VERSION 5.8 ;
BUSBITCHARS "[]" ;
DIVIDERCHAR "/" ;
UNITS
    DATABASE MICRONS 1000 ;
END UNITS

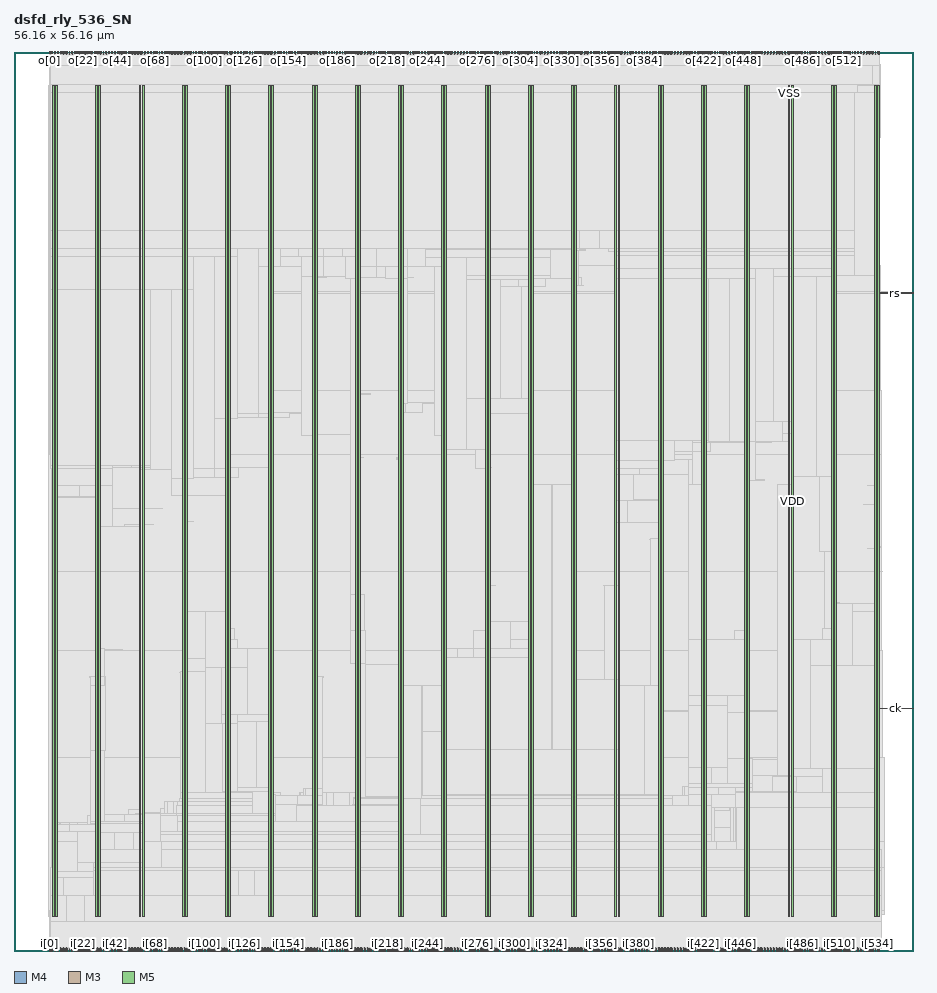
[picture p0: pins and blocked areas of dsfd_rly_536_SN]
MACRO dsfd_rly_536_SN
  FOREIGN dsfd_rly_536_SN 0 0 ;
  CLASS BLOCK ;
  SIZE 56.16 BY 56.16 ;
  PIN ck
    DIRECTION INPUT ;
    USE SIGNAL ;
    PORT
      LAYER M4 ;
        RECT  55.968 15.12 56.16 15.144 ;
    END
    PORT
      LAYER M4 ;
        RECT  54.004 15.12 55.98 15.144 ;
    END
  END ck
  PIN i[0]
    DIRECTION INPUT ;
    USE SIGNAL ;
    PORT
      LAYER M3 ;
        RECT  2.196 0 2.214 0.144 ;
    END
  END i[0]
  PIN i[100]
    DIRECTION INPUT ;
    USE SIGNAL ;
    PORT
      LAYER M3 ;
        RECT  11.88 0 11.898 0.144 ;
    END
  END i[100]
  PIN i[101]
    DIRECTION INPUT ;
    USE SIGNAL ;
    PORT
      LAYER M5 ;
        RECT  11.952 0 11.976 0.192 ;
    END
  END i[101]
  PIN i[102]
    DIRECTION INPUT ;
    USE SIGNAL ;
    PORT
      LAYER M3 ;
        RECT  12.06 0 12.078 0.144 ;
    END
  END i[102]
  PIN i[103]
    DIRECTION INPUT ;
    USE SIGNAL ;
    PORT
      LAYER M5 ;
        RECT  12.144 0 12.168 0.192 ;
    END
  END i[103]
  PIN i[104]
    DIRECTION INPUT ;
    USE SIGNAL ;
    PORT
      LAYER M3 ;
        RECT  12.24 0 12.258 0.144 ;
    END
  END i[104]
  PIN i[105]
    DIRECTION INPUT ;
    USE SIGNAL ;
    PORT
      LAYER M5 ;
        RECT  12.336 0 12.36 0.192 ;
    END
  END i[105]
  PIN i[106]
    DIRECTION INPUT ;
    USE SIGNAL ;
    PORT
      LAYER M3 ;
        RECT  12.456 0 12.474 0.144 ;
    END
  END i[106]
  PIN i[107]
    DIRECTION INPUT ;
    USE SIGNAL ;
    PORT
      LAYER M5 ;
        RECT  12.528 0 12.552 0.192 ;
    END
  END i[107]
  PIN i[108]
    DIRECTION INPUT ;
    USE SIGNAL ;
    PORT
      LAYER M3 ;
        RECT  12.636 0 12.654 0.144 ;
    END
  END i[108]
  PIN i[109]
    DIRECTION INPUT ;
    USE SIGNAL ;
    PORT
      LAYER M5 ;
        RECT  12.72 0 12.744 0.192 ;
    END
  END i[109]
  PIN i[10]
    DIRECTION INPUT ;
    USE SIGNAL ;
    PORT
      LAYER M3 ;
        RECT  3.168 0 3.186 0.144 ;
    END
  END i[10]
  PIN i[110]
    DIRECTION INPUT ;
    USE SIGNAL ;
    PORT
      LAYER M3 ;
        RECT  12.852 0 12.87 0.144 ;
    END
  END i[110]
  PIN i[111]
    DIRECTION INPUT ;
    USE SIGNAL ;
    PORT
      LAYER M5 ;
        RECT  12.912 0 12.936 0.192 ;
    END
  END i[111]
  PIN i[112]
    DIRECTION INPUT ;
    USE SIGNAL ;
    PORT
      LAYER M3 ;
        RECT  13.032 0 13.05 0.144 ;
    END
  END i[112]
  PIN i[113]
    DIRECTION INPUT ;
    USE SIGNAL ;
    PORT
      LAYER M5 ;
        RECT  13.104 0 13.128 0.192 ;
    END
  END i[113]
  PIN i[114]
    DIRECTION INPUT ;
    USE SIGNAL ;
    PORT
      LAYER M3 ;
        RECT  13.212 0 13.23 0.144 ;
    END
  END i[114]
  PIN i[115]
    DIRECTION INPUT ;
    USE SIGNAL ;
    PORT
      LAYER M5 ;
        RECT  13.296 0 13.32 0.192 ;
    END
  END i[115]
  PIN i[116]
    DIRECTION INPUT ;
    USE SIGNAL ;
    PORT
      LAYER M3 ;
        RECT  13.428 0 13.446 0.144 ;
    END
  END i[116]
  PIN i[117]
    DIRECTION INPUT ;
    USE SIGNAL ;
    PORT
      LAYER M5 ;
        RECT  13.536 0 13.56 0.192 ;
    END
  END i[117]
  PIN i[118]
    DIRECTION INPUT ;
    USE SIGNAL ;
    PORT
      LAYER M3 ;
        RECT  13.608 0 13.626 0.144 ;
    END
  END i[118]
  PIN i[119]
    DIRECTION INPUT ;
    USE SIGNAL ;
    PORT
      LAYER M5 ;
        RECT  13.728 0 13.752 0.192 ;
    END
  END i[119]
  PIN i[11]
    DIRECTION INPUT ;
    USE SIGNAL ;
    PORT
      LAYER M5 ;
        RECT  3.264 0 3.288 0.192 ;
    END
  END i[11]
  PIN i[120]
    DIRECTION INPUT ;
    USE SIGNAL ;
    PORT
      LAYER M3 ;
        RECT  13.788 0 13.806 0.144 ;
    END
  END i[120]
  PIN i[121]
    DIRECTION INPUT ;
    USE SIGNAL ;
    PORT
      LAYER M5 ;
        RECT  13.92 0 13.944 0.192 ;
    END
  END i[121]
  PIN i[122]
    DIRECTION INPUT ;
    USE SIGNAL ;
    PORT
      LAYER M3 ;
        RECT  14.004 0 14.022 0.144 ;
    END
  END i[122]
  PIN i[123]
    DIRECTION INPUT ;
    USE SIGNAL ;
    PORT
      LAYER M5 ;
        RECT  14.112 0 14.136 0.192 ;
    END
  END i[123]
  PIN i[124]
    DIRECTION INPUT ;
    USE SIGNAL ;
    PORT
      LAYER M3 ;
        RECT  14.184 0 14.202 0.144 ;
    END
  END i[124]
  PIN i[125]
    DIRECTION INPUT ;
    USE SIGNAL ;
    PORT
      LAYER M5 ;
        RECT  14.304 0 14.328 0.192 ;
    END
  END i[125]
  PIN i[126]
    DIRECTION INPUT ;
    USE SIGNAL ;
    PORT
      LAYER M3 ;
        RECT  14.4 0 14.418 0.144 ;
    END
  END i[126]
  PIN i[127]
    DIRECTION INPUT ;
    USE SIGNAL ;
    PORT
      LAYER M5 ;
        RECT  14.496 0 14.52 0.192 ;
    END
  END i[127]
  PIN i[128]
    DIRECTION INPUT ;
    USE SIGNAL ;
    PORT
      LAYER M3 ;
        RECT  14.58 0 14.598 0.144 ;
    END
  END i[128]
  PIN i[129]
    DIRECTION INPUT ;
    USE SIGNAL ;
    PORT
      LAYER M5 ;
        RECT  14.688 0 14.712 0.192 ;
    END
  END i[129]
  PIN i[12]
    DIRECTION INPUT ;
    USE SIGNAL ;
    PORT
      LAYER M3 ;
        RECT  3.348 0 3.366 0.144 ;
    END
  END i[12]
  PIN i[130]
    DIRECTION INPUT ;
    USE SIGNAL ;
    PORT
      LAYER M3 ;
        RECT  14.76 0 14.778 0.144 ;
    END
  END i[130]
  PIN i[131]
    DIRECTION INPUT ;
    USE SIGNAL ;
    PORT
      LAYER M5 ;
        RECT  14.88 0 14.904 0.192 ;
    END
  END i[131]
  PIN i[132]
    DIRECTION INPUT ;
    USE SIGNAL ;
    PORT
      LAYER M3 ;
        RECT  14.976 0 14.994 0.144 ;
    END
  END i[132]
  PIN i[133]
    DIRECTION INPUT ;
    USE SIGNAL ;
    PORT
      LAYER M5 ;
        RECT  15.072 0 15.096 0.192 ;
    END
  END i[133]
  PIN i[134]
    DIRECTION INPUT ;
    USE SIGNAL ;
    PORT
      LAYER M3 ;
        RECT  15.156 0 15.174 0.144 ;
    END
  END i[134]
  PIN i[135]
    DIRECTION INPUT ;
    USE SIGNAL ;
    PORT
      LAYER M5 ;
        RECT  15.264 0 15.288 0.192 ;
    END
  END i[135]
  PIN i[136]
    DIRECTION INPUT ;
    USE SIGNAL ;
    PORT
      LAYER M3 ;
        RECT  15.336 0 15.354 0.144 ;
    END
  END i[136]
  PIN i[137]
    DIRECTION INPUT ;
    USE SIGNAL ;
    PORT
      LAYER M5 ;
        RECT  15.456 0 15.48 0.192 ;
    END
  END i[137]
  PIN i[138]
    DIRECTION INPUT ;
    USE SIGNAL ;
    PORT
      LAYER M3 ;
        RECT  15.552 0 15.57 0.144 ;
    END
  END i[138]
  PIN i[139]
    DIRECTION INPUT ;
    USE SIGNAL ;
    PORT
      LAYER M5 ;
        RECT  15.648 0 15.672 0.192 ;
    END
  END i[139]
  PIN i[13]
    DIRECTION INPUT ;
    USE SIGNAL ;
    PORT
      LAYER M5 ;
        RECT  3.456 0 3.48 0.192 ;
    END
  END i[13]
  PIN i[140]
    DIRECTION INPUT ;
    USE SIGNAL ;
    PORT
      LAYER M3 ;
        RECT  15.732 0 15.75 0.144 ;
    END
  END i[140]
  PIN i[141]
    DIRECTION INPUT ;
    USE SIGNAL ;
    PORT
      LAYER M5 ;
        RECT  15.84 0 15.864 0.192 ;
    END
  END i[141]
  PIN i[142]
    DIRECTION INPUT ;
    USE SIGNAL ;
    PORT
      LAYER M3 ;
        RECT  15.948 0 15.966 0.144 ;
    END
  END i[142]
  PIN i[143]
    DIRECTION INPUT ;
    USE SIGNAL ;
    PORT
      LAYER M5 ;
        RECT  16.032 0 16.056 0.192 ;
    END
  END i[143]
  PIN i[144]
    DIRECTION INPUT ;
    USE SIGNAL ;
    PORT
      LAYER M3 ;
        RECT  16.128 0 16.146 0.144 ;
    END
  END i[144]
  PIN i[145]
    DIRECTION INPUT ;
    USE SIGNAL ;
    PORT
      LAYER M5 ;
        RECT  16.224 0 16.248 0.192 ;
    END
  END i[145]
  PIN i[146]
    DIRECTION INPUT ;
    USE SIGNAL ;
    PORT
      LAYER M3 ;
        RECT  16.308 0 16.326 0.144 ;
    END
  END i[146]
  PIN i[147]
    DIRECTION INPUT ;
    USE SIGNAL ;
    PORT
      LAYER M5 ;
        RECT  16.416 0 16.44 0.192 ;
    END
  END i[147]
  PIN i[148]
    DIRECTION INPUT ;
    USE SIGNAL ;
    PORT
      LAYER M3 ;
        RECT  16.524 0 16.542 0.144 ;
    END
  END i[148]
  PIN i[149]
    DIRECTION INPUT ;
    USE SIGNAL ;
    PORT
      LAYER M5 ;
        RECT  16.608 0 16.632 0.192 ;
    END
  END i[149]
  PIN i[14]
    DIRECTION INPUT ;
    USE SIGNAL ;
    PORT
      LAYER M3 ;
        RECT  3.564 0 3.582 0.144 ;
    END
  END i[14]
  PIN i[150]
    DIRECTION INPUT ;
    USE SIGNAL ;
    PORT
      LAYER M3 ;
        RECT  16.704 0 16.722 0.144 ;
    END
  END i[150]
  PIN i[151]
    DIRECTION INPUT ;
    USE SIGNAL ;
    PORT
      LAYER M5 ;
        RECT  16.8 0 16.824 0.192 ;
    END
  END i[151]
  PIN i[152]
    DIRECTION INPUT ;
    USE SIGNAL ;
    PORT
      LAYER M3 ;
        RECT  16.884 0 16.902 0.144 ;
    END
  END i[152]
  PIN i[153]
    DIRECTION INPUT ;
    USE SIGNAL ;
    PORT
      LAYER M5 ;
        RECT  16.992 0 17.016 0.192 ;
    END
  END i[153]
  PIN i[154]
    DIRECTION INPUT ;
    USE SIGNAL ;
    PORT
      LAYER M3 ;
        RECT  17.1 0 17.118 0.144 ;
    END
  END i[154]
  PIN i[155]
    DIRECTION INPUT ;
    USE SIGNAL ;
    PORT
      LAYER M5 ;
        RECT  17.184 0 17.208 0.192 ;
    END
  END i[155]
  PIN i[156]
    DIRECTION INPUT ;
    USE SIGNAL ;
    PORT
      LAYER M3 ;
        RECT  17.28 0 17.298 0.144 ;
    END
  END i[156]
  PIN i[157]
    DIRECTION INPUT ;
    USE SIGNAL ;
    PORT
      LAYER M5 ;
        RECT  17.376 0 17.4 0.192 ;
    END
  END i[157]
  PIN i[158]
    DIRECTION INPUT ;
    USE SIGNAL ;
    PORT
      LAYER M3 ;
        RECT  17.496 0 17.514 0.144 ;
    END
  END i[158]
  PIN i[159]
    DIRECTION INPUT ;
    USE SIGNAL ;
    PORT
      LAYER M5 ;
        RECT  17.568 0 17.592 0.192 ;
    END
  END i[159]
  PIN i[15]
    DIRECTION INPUT ;
    USE SIGNAL ;
    PORT
      LAYER M5 ;
        RECT  3.648 0 3.672 0.192 ;
    END
  END i[15]
  PIN i[160]
    DIRECTION INPUT ;
    USE SIGNAL ;
    PORT
      LAYER M3 ;
        RECT  17.676 0 17.694 0.144 ;
    END
  END i[160]
  PIN i[161]
    DIRECTION INPUT ;
    USE SIGNAL ;
    PORT
      LAYER M5 ;
        RECT  17.76 0 17.784 0.192 ;
    END
  END i[161]
  PIN i[162]
    DIRECTION INPUT ;
    USE SIGNAL ;
    PORT
      LAYER M3 ;
        RECT  17.856 0 17.874 0.144 ;
    END
  END i[162]
  PIN i[163]
    DIRECTION INPUT ;
    USE SIGNAL ;
    PORT
      LAYER M5 ;
        RECT  17.952 0 17.976 0.192 ;
    END
  END i[163]
  PIN i[164]
    DIRECTION INPUT ;
    USE SIGNAL ;
    PORT
      LAYER M3 ;
        RECT  18.072 0 18.09 0.144 ;
    END
  END i[164]
  PIN i[165]
    DIRECTION INPUT ;
    USE SIGNAL ;
    PORT
      LAYER M5 ;
        RECT  18.144 0 18.168 0.192 ;
    END
  END i[165]
  PIN i[166]
    DIRECTION INPUT ;
    USE SIGNAL ;
    PORT
      LAYER M3 ;
        RECT  18.252 0 18.27 0.144 ;
    END
  END i[166]
  PIN i[167]
    DIRECTION INPUT ;
    USE SIGNAL ;
    PORT
      LAYER M5 ;
        RECT  18.336 0 18.36 0.192 ;
    END
  END i[167]
  PIN i[168]
    DIRECTION INPUT ;
    USE SIGNAL ;
    PORT
      LAYER M3 ;
        RECT  18.432 0 18.45 0.144 ;
    END
  END i[168]
  PIN i[169]
    DIRECTION INPUT ;
    USE SIGNAL ;
    PORT
      LAYER M5 ;
        RECT  18.528 0 18.552 0.192 ;
    END
  END i[169]
  PIN i[16]
    DIRECTION INPUT ;
    USE SIGNAL ;
    PORT
      LAYER M3 ;
        RECT  3.744 0 3.762 0.144 ;
    END
  END i[16]
  PIN i[170]
    DIRECTION INPUT ;
    USE SIGNAL ;
    PORT
      LAYER M3 ;
        RECT  18.648 0 18.666 0.144 ;
    END
  END i[170]
  PIN i[171]
    DIRECTION INPUT ;
    USE SIGNAL ;
    PORT
      LAYER M5 ;
        RECT  18.72 0 18.744 0.192 ;
    END
  END i[171]
  PIN i[172]
    DIRECTION INPUT ;
    USE SIGNAL ;
    PORT
      LAYER M3 ;
        RECT  18.828 0 18.846 0.144 ;
    END
  END i[172]
  PIN i[173]
    DIRECTION INPUT ;
    USE SIGNAL ;
    PORT
      LAYER M5 ;
        RECT  18.912 0 18.936 0.192 ;
    END
  END i[173]
  PIN i[174]
    DIRECTION INPUT ;
    USE SIGNAL ;
    PORT
      LAYER M3 ;
        RECT  19.044 0 19.062 0.144 ;
    END
  END i[174]
  PIN i[175]
    DIRECTION INPUT ;
    USE SIGNAL ;
    PORT
      LAYER M5 ;
        RECT  19.104 0 19.128 0.192 ;
    END
  END i[175]
  PIN i[176]
    DIRECTION INPUT ;
    USE SIGNAL ;
    PORT
      LAYER M3 ;
        RECT  19.224 0 19.242 0.144 ;
    END
  END i[176]
  PIN i[177]
    DIRECTION INPUT ;
    USE SIGNAL ;
    PORT
      LAYER M5 ;
        RECT  19.296 0 19.32 0.192 ;
    END
  END i[177]
  PIN i[178]
    DIRECTION INPUT ;
    USE SIGNAL ;
    PORT
      LAYER M3 ;
        RECT  19.404 0 19.422 0.144 ;
    END
  END i[178]
  PIN i[179]
    DIRECTION INPUT ;
    USE SIGNAL ;
    PORT
      LAYER M5 ;
        RECT  19.488 0 19.512 0.192 ;
    END
  END i[179]
  PIN i[17]
    DIRECTION INPUT ;
    USE SIGNAL ;
    PORT
      LAYER M5 ;
        RECT  3.84 0 3.864 0.192 ;
    END
  END i[17]
  PIN i[180]
    DIRECTION INPUT ;
    USE SIGNAL ;
    PORT
      LAYER M3 ;
        RECT  19.62 0 19.638 0.144 ;
    END
  END i[180]
  PIN i[181]
    DIRECTION INPUT ;
    USE SIGNAL ;
    PORT
      LAYER M5 ;
        RECT  19.68 0 19.704 0.192 ;
    END
  END i[181]
  PIN i[182]
    DIRECTION INPUT ;
    USE SIGNAL ;
    PORT
      LAYER M3 ;
        RECT  19.8 0 19.818 0.144 ;
    END
  END i[182]
  PIN i[183]
    DIRECTION INPUT ;
    USE SIGNAL ;
    PORT
      LAYER M5 ;
        RECT  19.872 0 19.896 0.192 ;
    END
  END i[183]
  PIN i[184]
    DIRECTION INPUT ;
    USE SIGNAL ;
    PORT
      LAYER M3 ;
        RECT  19.98 0 19.998 0.144 ;
    END
  END i[184]
  PIN i[185]
    DIRECTION INPUT ;
    USE SIGNAL ;
    PORT
      LAYER M5 ;
        RECT  20.112 0 20.136 0.192 ;
    END
  END i[185]
  PIN i[186]
    DIRECTION INPUT ;
    USE SIGNAL ;
    PORT
      LAYER M3 ;
        RECT  20.196 0 20.214 0.144 ;
    END
  END i[186]
  PIN i[187]
    DIRECTION INPUT ;
    USE SIGNAL ;
    PORT
      LAYER M5 ;
        RECT  20.304 0 20.328 0.192 ;
    END
  END i[187]
  PIN i[188]
    DIRECTION INPUT ;
    USE SIGNAL ;
    PORT
      LAYER M3 ;
        RECT  20.376 0 20.394 0.144 ;
    END
  END i[188]
  PIN i[189]
    DIRECTION INPUT ;
    USE SIGNAL ;
    PORT
      LAYER M5 ;
        RECT  20.496 0 20.52 0.192 ;
    END
  END i[189]
  PIN i[18]
    DIRECTION INPUT ;
    USE SIGNAL ;
    PORT
      LAYER M3 ;
        RECT  3.924 0 3.942 0.144 ;
    END
  END i[18]
  PIN i[190]
    DIRECTION INPUT ;
    USE SIGNAL ;
    PORT
      LAYER M3 ;
        RECT  20.592 0 20.61 0.144 ;
    END
  END i[190]
  PIN i[191]
    DIRECTION INPUT ;
    USE SIGNAL ;
    PORT
      LAYER M5 ;
        RECT  20.688 0 20.712 0.192 ;
    END
  END i[191]
  PIN i[192]
    DIRECTION INPUT ;
    USE SIGNAL ;
    PORT
      LAYER M3 ;
        RECT  20.772 0 20.79 0.144 ;
    END
  END i[192]
  PIN i[193]
    DIRECTION INPUT ;
    USE SIGNAL ;
    PORT
      LAYER M5 ;
        RECT  20.88 0 20.904 0.192 ;
    END
  END i[193]
  PIN i[194]
    DIRECTION INPUT ;
    USE SIGNAL ;
    PORT
      LAYER M3 ;
        RECT  20.952 0 20.97 0.144 ;
    END
  END i[194]
  PIN i[195]
    DIRECTION INPUT ;
    USE SIGNAL ;
    PORT
      LAYER M5 ;
        RECT  21.072 0 21.096 0.192 ;
    END
  END i[195]
  PIN i[196]
    DIRECTION INPUT ;
    USE SIGNAL ;
    PORT
      LAYER M3 ;
        RECT  21.168 0 21.186 0.144 ;
    END
  END i[196]
  PIN i[197]
    DIRECTION INPUT ;
    USE SIGNAL ;
    PORT
      LAYER M5 ;
        RECT  21.264 0 21.288 0.192 ;
    END
  END i[197]
  PIN i[198]
    DIRECTION INPUT ;
    USE SIGNAL ;
    PORT
      LAYER M3 ;
        RECT  21.348 0 21.366 0.144 ;
    END
  END i[198]
  PIN i[199]
    DIRECTION INPUT ;
    USE SIGNAL ;
    PORT
      LAYER M5 ;
        RECT  21.456 0 21.48 0.192 ;
    END
  END i[199]
  PIN i[19]
    DIRECTION INPUT ;
    USE SIGNAL ;
    PORT
      LAYER M5 ;
        RECT  4.032 0 4.056 0.192 ;
    END
  END i[19]
  PIN i[1]
    DIRECTION INPUT ;
    USE SIGNAL ;
    PORT
      LAYER M5 ;
        RECT  2.304 0 2.328 0.192 ;
    END
  END i[1]
  PIN i[200]
    DIRECTION INPUT ;
    USE SIGNAL ;
    PORT
      LAYER M3 ;
        RECT  21.528 0 21.546 0.144 ;
    END
  END i[200]
  PIN i[201]
    DIRECTION INPUT ;
    USE SIGNAL ;
    PORT
      LAYER M5 ;
        RECT  21.648 0 21.672 0.192 ;
    END
  END i[201]
  PIN i[202]
    DIRECTION INPUT ;
    USE SIGNAL ;
    PORT
      LAYER M3 ;
        RECT  21.744 0 21.762 0.144 ;
    END
  END i[202]
  PIN i[203]
    DIRECTION INPUT ;
    USE SIGNAL ;
    PORT
      LAYER M5 ;
        RECT  21.84 0 21.864 0.192 ;
    END
  END i[203]
  PIN i[204]
    DIRECTION INPUT ;
    USE SIGNAL ;
    PORT
      LAYER M3 ;
        RECT  21.924 0 21.942 0.144 ;
    END
  END i[204]
  PIN i[205]
    DIRECTION INPUT ;
    USE SIGNAL ;
    PORT
      LAYER M5 ;
        RECT  22.032 0 22.056 0.192 ;
    END
  END i[205]
  PIN i[206]
    DIRECTION INPUT ;
    USE SIGNAL ;
    PORT
      LAYER M3 ;
        RECT  22.14 0 22.158 0.144 ;
    END
  END i[206]
  PIN i[207]
    DIRECTION INPUT ;
    USE SIGNAL ;
    PORT
      LAYER M5 ;
        RECT  22.224 0 22.248 0.192 ;
    END
  END i[207]
  PIN i[208]
    DIRECTION INPUT ;
    USE SIGNAL ;
    PORT
      LAYER M3 ;
        RECT  22.32 0 22.338 0.144 ;
    END
  END i[208]
  PIN i[209]
    DIRECTION INPUT ;
    USE SIGNAL ;
    PORT
      LAYER M5 ;
        RECT  22.416 0 22.44 0.192 ;
    END
  END i[209]
  PIN i[20]
    DIRECTION INPUT ;
    USE SIGNAL ;
    PORT
      LAYER M3 ;
        RECT  4.14 0 4.158 0.144 ;
    END
  END i[20]
  PIN i[210]
    DIRECTION INPUT ;
    USE SIGNAL ;
    PORT
      LAYER M3 ;
        RECT  22.5 0 22.518 0.144 ;
    END
  END i[210]
  PIN i[211]
    DIRECTION INPUT ;
    USE SIGNAL ;
    PORT
      LAYER M5 ;
        RECT  22.608 0 22.632 0.192 ;
    END
  END i[211]
  PIN i[212]
    DIRECTION INPUT ;
    USE SIGNAL ;
    PORT
      LAYER M3 ;
        RECT  22.716 0 22.734 0.144 ;
    END
  END i[212]
  PIN i[213]
    DIRECTION INPUT ;
    USE SIGNAL ;
    PORT
      LAYER M5 ;
        RECT  22.8 0 22.824 0.192 ;
    END
  END i[213]
  PIN i[214]
    DIRECTION INPUT ;
    USE SIGNAL ;
    PORT
      LAYER M3 ;
        RECT  22.896 0 22.914 0.144 ;
    END
  END i[214]
  PIN i[215]
    DIRECTION INPUT ;
    USE SIGNAL ;
    PORT
      LAYER M5 ;
        RECT  22.992 0 23.016 0.192 ;
    END
  END i[215]
  PIN i[216]
    DIRECTION INPUT ;
    USE SIGNAL ;
    PORT
      LAYER M3 ;
        RECT  23.076 0 23.094 0.144 ;
    END
  END i[216]
  PIN i[217]
    DIRECTION INPUT ;
    USE SIGNAL ;
    PORT
      LAYER M5 ;
        RECT  23.184 0 23.208 0.192 ;
    END
  END i[217]
  PIN i[218]
    DIRECTION INPUT ;
    USE SIGNAL ;
    PORT
      LAYER M3 ;
        RECT  23.292 0 23.31 0.144 ;
    END
  END i[218]
  PIN i[219]
    DIRECTION INPUT ;
    USE SIGNAL ;
    PORT
      LAYER M5 ;
        RECT  23.376 0 23.4 0.192 ;
    END
  END i[219]
  PIN i[21]
    DIRECTION INPUT ;
    USE SIGNAL ;
    PORT
      LAYER M5 ;
        RECT  4.224 0 4.248 0.192 ;
    END
  END i[21]
  PIN i[220]
    DIRECTION INPUT ;
    USE SIGNAL ;
    PORT
      LAYER M3 ;
        RECT  23.472 0 23.49 0.144 ;
    END
  END i[220]
  PIN i[221]
    DIRECTION INPUT ;
    USE SIGNAL ;
    PORT
      LAYER M5 ;
        RECT  23.568 0 23.592 0.192 ;
    END
  END i[221]
  PIN i[222]
    DIRECTION INPUT ;
    USE SIGNAL ;
    PORT
      LAYER M3 ;
        RECT  23.688 0 23.706 0.144 ;
    END
  END i[222]
  PIN i[223]
    DIRECTION INPUT ;
    USE SIGNAL ;
    PORT
      LAYER M5 ;
        RECT  23.76 0 23.784 0.192 ;
    END
  END i[223]
  PIN i[224]
    DIRECTION INPUT ;
    USE SIGNAL ;
    PORT
      LAYER M3 ;
        RECT  23.868 0 23.886 0.144 ;
    END
  END i[224]
  PIN i[225]
    DIRECTION INPUT ;
    USE SIGNAL ;
    PORT
      LAYER M5 ;
        RECT  23.952 0 23.976 0.192 ;
    END
  END i[225]
  PIN i[226]
    DIRECTION INPUT ;
    USE SIGNAL ;
    PORT
      LAYER M3 ;
        RECT  24.048 0 24.066 0.144 ;
    END
  END i[226]
  PIN i[227]
    DIRECTION INPUT ;
    USE SIGNAL ;
    PORT
      LAYER M5 ;
        RECT  24.144 0 24.168 0.192 ;
    END
  END i[227]
  PIN i[228]
    DIRECTION INPUT ;
    USE SIGNAL ;
    PORT
      LAYER M3 ;
        RECT  24.264 0 24.282 0.144 ;
    END
  END i[228]
  PIN i[229]
    DIRECTION INPUT ;
    USE SIGNAL ;
    PORT
      LAYER M5 ;
        RECT  24.336 0 24.36 0.192 ;
    END
  END i[229]
  PIN i[22]
    DIRECTION INPUT ;
    USE SIGNAL ;
    PORT
      LAYER M3 ;
        RECT  4.32 0 4.338 0.144 ;
    END
  END i[22]
  PIN i[230]
    DIRECTION INPUT ;
    USE SIGNAL ;
    PORT
      LAYER M3 ;
        RECT  24.444 0 24.462 0.144 ;
    END
  END i[230]
  PIN i[231]
    DIRECTION INPUT ;
    USE SIGNAL ;
    PORT
      LAYER M5 ;
        RECT  24.528 0 24.552 0.192 ;
    END
  END i[231]
  PIN i[232]
    DIRECTION INPUT ;
    USE SIGNAL ;
    PORT
      LAYER M3 ;
        RECT  24.624 0 24.642 0.144 ;
    END
  END i[232]
  PIN i[233]
    DIRECTION INPUT ;
    USE SIGNAL ;
    PORT
      LAYER M5 ;
        RECT  24.72 0 24.744 0.192 ;
    END
  END i[233]
  PIN i[234]
    DIRECTION INPUT ;
    USE SIGNAL ;
    PORT
      LAYER M3 ;
        RECT  24.84 0 24.858 0.144 ;
    END
  END i[234]
  PIN i[235]
    DIRECTION INPUT ;
    USE SIGNAL ;
    PORT
      LAYER M5 ;
        RECT  24.912 0 24.936 0.192 ;
    END
  END i[235]
  PIN i[236]
    DIRECTION INPUT ;
    USE SIGNAL ;
    PORT
      LAYER M3 ;
        RECT  25.02 0 25.038 0.144 ;
    END
  END i[236]
  PIN i[237]
    DIRECTION INPUT ;
    USE SIGNAL ;
    PORT
      LAYER M5 ;
        RECT  25.104 0 25.128 0.192 ;
    END
  END i[237]
  PIN i[238]
    DIRECTION INPUT ;
    USE SIGNAL ;
    PORT
      LAYER M3 ;
        RECT  25.2 0 25.218 0.144 ;
    END
  END i[238]
  PIN i[239]
    DIRECTION INPUT ;
    USE SIGNAL ;
    PORT
      LAYER M5 ;
        RECT  25.296 0 25.32 0.192 ;
    END
  END i[239]
  PIN i[23]
    DIRECTION INPUT ;
    USE SIGNAL ;
    PORT
      LAYER M5 ;
        RECT  4.416 0 4.44 0.192 ;
    END
  END i[23]
  PIN i[240]
    DIRECTION INPUT ;
    USE SIGNAL ;
    PORT
      LAYER M3 ;
        RECT  25.416 0 25.434 0.144 ;
    END
  END i[240]
  PIN i[241]
    DIRECTION INPUT ;
    USE SIGNAL ;
    PORT
      LAYER M5 ;
        RECT  25.488 0 25.512 0.192 ;
    END
  END i[241]
  PIN i[242]
    DIRECTION INPUT ;
    USE SIGNAL ;
    PORT
      LAYER M3 ;
        RECT  25.596 0 25.614 0.144 ;
    END
  END i[242]
  PIN i[243]
    DIRECTION INPUT ;
    USE SIGNAL ;
    PORT
      LAYER M5 ;
        RECT  25.68 0 25.704 0.192 ;
    END
  END i[243]
  PIN i[244]
    DIRECTION INPUT ;
    USE SIGNAL ;
    PORT
      LAYER M3 ;
        RECT  25.812 0 25.83 0.144 ;
    END
  END i[244]
  PIN i[245]
    DIRECTION INPUT ;
    USE SIGNAL ;
    PORT
      LAYER M5 ;
        RECT  25.872 0 25.896 0.192 ;
    END
  END i[245]
  PIN i[246]
    DIRECTION INPUT ;
    USE SIGNAL ;
    PORT
      LAYER M3 ;
        RECT  25.992 0 26.01 0.144 ;
    END
  END i[246]
  PIN i[247]
    DIRECTION INPUT ;
    USE SIGNAL ;
    PORT
      LAYER M5 ;
        RECT  26.064 0 26.088 0.192 ;
    END
  END i[247]
  PIN i[248]
    DIRECTION INPUT ;
    USE SIGNAL ;
    PORT
      LAYER M3 ;
        RECT  26.172 0 26.19 0.144 ;
    END
  END i[248]
  PIN i[249]
    DIRECTION INPUT ;
    USE SIGNAL ;
    PORT
      LAYER M5 ;
        RECT  26.256 0 26.28 0.192 ;
    END
  END i[249]
  PIN i[24]
    DIRECTION INPUT ;
    USE SIGNAL ;
    PORT
      LAYER M3 ;
        RECT  4.536 0 4.554 0.144 ;
    END
  END i[24]
  PIN i[250]
    DIRECTION INPUT ;
    USE SIGNAL ;
    PORT
      LAYER M3 ;
        RECT  26.388 0 26.406 0.144 ;
    END
  END i[250]
  PIN i[251]
    DIRECTION INPUT ;
    USE SIGNAL ;
    PORT
      LAYER M5 ;
        RECT  26.496 0 26.52 0.192 ;
    END
  END i[251]
  PIN i[252]
    DIRECTION INPUT ;
    USE SIGNAL ;
    PORT
      LAYER M3 ;
        RECT  26.568 0 26.586 0.144 ;
    END
  END i[252]
  PIN i[253]
    DIRECTION INPUT ;
    USE SIGNAL ;
    PORT
      LAYER M5 ;
        RECT  26.688 0 26.712 0.192 ;
    END
  END i[253]
  PIN i[254]
    DIRECTION INPUT ;
    USE SIGNAL ;
    PORT
      LAYER M3 ;
        RECT  26.748 0 26.766 0.144 ;
    END
  END i[254]
  PIN i[255]
    DIRECTION INPUT ;
    USE SIGNAL ;
    PORT
      LAYER M5 ;
        RECT  26.88 0 26.904 0.192 ;
    END
  END i[255]
  PIN i[256]
    DIRECTION INPUT ;
    USE SIGNAL ;
    PORT
      LAYER M3 ;
        RECT  26.964 0 26.982 0.144 ;
    END
  END i[256]
  PIN i[257]
    DIRECTION INPUT ;
    USE SIGNAL ;
    PORT
      LAYER M5 ;
        RECT  27.072 0 27.096 0.192 ;
    END
  END i[257]
  PIN i[258]
    DIRECTION INPUT ;
    USE SIGNAL ;
    PORT
      LAYER M3 ;
        RECT  27.144 0 27.162 0.144 ;
    END
  END i[258]
  PIN i[259]
    DIRECTION INPUT ;
    USE SIGNAL ;
    PORT
      LAYER M5 ;
        RECT  27.264 0 27.288 0.192 ;
    END
  END i[259]
  PIN i[25]
    DIRECTION INPUT ;
    USE SIGNAL ;
    PORT
      LAYER M5 ;
        RECT  4.608 0 4.632 0.192 ;
    END
  END i[25]
  PIN i[260]
    DIRECTION INPUT ;
    USE SIGNAL ;
    PORT
      LAYER M3 ;
        RECT  27.36 0 27.378 0.144 ;
    END
  END i[260]
  PIN i[261]
    DIRECTION INPUT ;
    USE SIGNAL ;
    PORT
      LAYER M5 ;
        RECT  27.456 0 27.48 0.192 ;
    END
  END i[261]
  PIN i[262]
    DIRECTION INPUT ;
    USE SIGNAL ;
    PORT
      LAYER M3 ;
        RECT  27.54 0 27.558 0.144 ;
    END
  END i[262]
  PIN i[263]
    DIRECTION INPUT ;
    USE SIGNAL ;
    PORT
      LAYER M5 ;
        RECT  27.648 0 27.672 0.192 ;
    END
  END i[263]
  PIN i[264]
    DIRECTION INPUT ;
    USE SIGNAL ;
    PORT
      LAYER M3 ;
        RECT  27.72 0 27.738 0.144 ;
    END
  END i[264]
  PIN i[265]
    DIRECTION INPUT ;
    USE SIGNAL ;
    PORT
      LAYER M5 ;
        RECT  27.84 0 27.864 0.192 ;
    END
  END i[265]
  PIN i[266]
    DIRECTION INPUT ;
    USE SIGNAL ;
    PORT
      LAYER M3 ;
        RECT  27.936 0 27.954 0.144 ;
    END
  END i[266]
  PIN i[267]
    DIRECTION INPUT ;
    USE SIGNAL ;
    PORT
      LAYER M5 ;
        RECT  28.032 0 28.056 0.192 ;
    END
  END i[267]
  PIN i[268]
    DIRECTION INPUT ;
    USE SIGNAL ;
    PORT
      LAYER M3 ;
        RECT  28.116 0 28.134 0.144 ;
    END
  END i[268]
  PIN i[269]
    DIRECTION INPUT ;
    USE SIGNAL ;
    PORT
      LAYER M5 ;
        RECT  28.224 0 28.248 0.192 ;
    END
  END i[269]
  PIN i[26]
    DIRECTION INPUT ;
    USE SIGNAL ;
    PORT
      LAYER M3 ;
        RECT  4.716 0 4.734 0.144 ;
    END
  END i[26]
  PIN i[270]
    DIRECTION INPUT ;
    USE SIGNAL ;
    PORT
      LAYER M3 ;
        RECT  28.296 0 28.314 0.144 ;
    END
  END i[270]
  PIN i[271]
    DIRECTION INPUT ;
    USE SIGNAL ;
    PORT
      LAYER M5 ;
        RECT  28.416 0 28.44 0.192 ;
    END
  END i[271]
  PIN i[272]
    DIRECTION INPUT ;
    USE SIGNAL ;
    PORT
      LAYER M3 ;
        RECT  28.512 0 28.53 0.144 ;
    END
  END i[272]
  PIN i[273]
    DIRECTION INPUT ;
    USE SIGNAL ;
    PORT
      LAYER M5 ;
        RECT  28.608 0 28.632 0.192 ;
    END
  END i[273]
  PIN i[274]
    DIRECTION INPUT ;
    USE SIGNAL ;
    PORT
      LAYER M3 ;
        RECT  28.692 0 28.71 0.144 ;
    END
  END i[274]
  PIN i[275]
    DIRECTION INPUT ;
    USE SIGNAL ;
    PORT
      LAYER M5 ;
        RECT  28.8 0 28.824 0.192 ;
    END
  END i[275]
  PIN i[276]
    DIRECTION INPUT ;
    USE SIGNAL ;
    PORT
      LAYER M3 ;
        RECT  28.908 0 28.926 0.144 ;
    END
  END i[276]
  PIN i[277]
    DIRECTION INPUT ;
    USE SIGNAL ;
    PORT
      LAYER M5 ;
        RECT  28.992 0 29.016 0.192 ;
    END
  END i[277]
  PIN i[278]
    DIRECTION INPUT ;
    USE SIGNAL ;
    PORT
      LAYER M3 ;
        RECT  29.088 0 29.106 0.144 ;
    END
  END i[278]
  PIN i[279]
    DIRECTION INPUT ;
    USE SIGNAL ;
    PORT
      LAYER M5 ;
        RECT  29.184 0 29.208 0.192 ;
    END
  END i[279]
  PIN i[27]
    DIRECTION INPUT ;
    USE SIGNAL ;
    PORT
      LAYER M5 ;
        RECT  4.8 0 4.824 0.192 ;
    END
  END i[27]
  PIN i[280]
    DIRECTION INPUT ;
    USE SIGNAL ;
    PORT
      LAYER M3 ;
        RECT  29.268 0 29.286 0.144 ;
    END
  END i[280]
  PIN i[281]
    DIRECTION INPUT ;
    USE SIGNAL ;
    PORT
      LAYER M5 ;
        RECT  29.376 0 29.4 0.192 ;
    END
  END i[281]
  PIN i[282]
    DIRECTION INPUT ;
    USE SIGNAL ;
    PORT
      LAYER M3 ;
        RECT  29.484 0 29.502 0.144 ;
    END
  END i[282]
  PIN i[283]
    DIRECTION INPUT ;
    USE SIGNAL ;
    PORT
      LAYER M5 ;
        RECT  29.568 0 29.592 0.192 ;
    END
  END i[283]
  PIN i[284]
    DIRECTION INPUT ;
    USE SIGNAL ;
    PORT
      LAYER M3 ;
        RECT  29.664 0 29.682 0.144 ;
    END
  END i[284]
  PIN i[285]
    DIRECTION INPUT ;
    USE SIGNAL ;
    PORT
      LAYER M5 ;
        RECT  29.76 0 29.784 0.192 ;
    END
  END i[285]
  PIN i[286]
    DIRECTION INPUT ;
    USE SIGNAL ;
    PORT
      LAYER M3 ;
        RECT  29.844 0 29.862 0.144 ;
    END
  END i[286]
  PIN i[287]
    DIRECTION INPUT ;
    USE SIGNAL ;
    PORT
      LAYER M5 ;
        RECT  29.952 0 29.976 0.192 ;
    END
  END i[287]
  PIN i[288]
    DIRECTION INPUT ;
    USE SIGNAL ;
    PORT
      LAYER M3 ;
        RECT  30.06 0 30.078 0.144 ;
    END
  END i[288]
  PIN i[289]
    DIRECTION INPUT ;
    USE SIGNAL ;
    PORT
      LAYER M5 ;
        RECT  30.144 0 30.168 0.192 ;
    END
  END i[289]
  PIN i[28]
    DIRECTION INPUT ;
    USE SIGNAL ;
    PORT
      LAYER M3 ;
        RECT  4.896 0 4.914 0.144 ;
    END
  END i[28]
  PIN i[290]
    DIRECTION INPUT ;
    USE SIGNAL ;
    PORT
      LAYER M3 ;
        RECT  30.24 0 30.258 0.144 ;
    END
  END i[290]
  PIN i[291]
    DIRECTION INPUT ;
    USE SIGNAL ;
    PORT
      LAYER M5 ;
        RECT  30.336 0 30.36 0.192 ;
    END
  END i[291]
  PIN i[292]
    DIRECTION INPUT ;
    USE SIGNAL ;
    PORT
      LAYER M3 ;
        RECT  30.456 0 30.474 0.144 ;
    END
  END i[292]
  PIN i[293]
    DIRECTION INPUT ;
    USE SIGNAL ;
    PORT
      LAYER M5 ;
        RECT  30.528 0 30.552 0.192 ;
    END
  END i[293]
  PIN i[294]
    DIRECTION INPUT ;
    USE SIGNAL ;
    PORT
      LAYER M3 ;
        RECT  30.636 0 30.654 0.144 ;
    END
  END i[294]
  PIN i[295]
    DIRECTION INPUT ;
    USE SIGNAL ;
    PORT
      LAYER M5 ;
        RECT  30.72 0 30.744 0.192 ;
    END
  END i[295]
  PIN i[296]
    DIRECTION INPUT ;
    USE SIGNAL ;
    PORT
      LAYER M3 ;
        RECT  30.816 0 30.834 0.144 ;
    END
  END i[296]
  PIN i[297]
    DIRECTION INPUT ;
    USE SIGNAL ;
    PORT
      LAYER M5 ;
        RECT  30.912 0 30.936 0.192 ;
    END
  END i[297]
  PIN i[298]
    DIRECTION INPUT ;
    USE SIGNAL ;
    PORT
      LAYER M3 ;
        RECT  31.032 0 31.05 0.144 ;
    END
  END i[298]
  PIN i[299]
    DIRECTION INPUT ;
    USE SIGNAL ;
    PORT
      LAYER M5 ;
        RECT  31.104 0 31.128 0.192 ;
    END
  END i[299]
  PIN i[29]
    DIRECTION INPUT ;
    USE SIGNAL ;
    PORT
      LAYER M5 ;
        RECT  4.992 0 5.016 0.192 ;
    END
  END i[29]
  PIN i[2]
    DIRECTION INPUT ;
    USE SIGNAL ;
    PORT
      LAYER M3 ;
        RECT  2.376 0 2.394 0.144 ;
    END
  END i[2]
  PIN i[300]
    DIRECTION INPUT ;
    USE SIGNAL ;
    PORT
      LAYER M3 ;
        RECT  31.212 0 31.23 0.144 ;
    END
  END i[300]
  PIN i[301]
    DIRECTION INPUT ;
    USE SIGNAL ;
    PORT
      LAYER M5 ;
        RECT  31.296 0 31.32 0.192 ;
    END
  END i[301]
  PIN i[302]
    DIRECTION INPUT ;
    USE SIGNAL ;
    PORT
      LAYER M3 ;
        RECT  31.392 0 31.41 0.144 ;
    END
  END i[302]
  PIN i[303]
    DIRECTION INPUT ;
    USE SIGNAL ;
    PORT
      LAYER M5 ;
        RECT  31.488 0 31.512 0.192 ;
    END
  END i[303]
  PIN i[304]
    DIRECTION INPUT ;
    USE SIGNAL ;
    PORT
      LAYER M3 ;
        RECT  31.608 0 31.626 0.144 ;
    END
  END i[304]
  PIN i[305]
    DIRECTION INPUT ;
    USE SIGNAL ;
    PORT
      LAYER M5 ;
        RECT  31.68 0 31.704 0.192 ;
    END
  END i[305]
  PIN i[306]
    DIRECTION INPUT ;
    USE SIGNAL ;
    PORT
      LAYER M3 ;
        RECT  31.788 0 31.806 0.144 ;
    END
  END i[306]
  PIN i[307]
    DIRECTION INPUT ;
    USE SIGNAL ;
    PORT
      LAYER M5 ;
        RECT  31.872 0 31.896 0.192 ;
    END
  END i[307]
  PIN i[308]
    DIRECTION INPUT ;
    USE SIGNAL ;
    PORT
      LAYER M3 ;
        RECT  32.004 0 32.022 0.144 ;
    END
  END i[308]
  PIN i[309]
    DIRECTION INPUT ;
    USE SIGNAL ;
    PORT
      LAYER M5 ;
        RECT  32.064 0 32.088 0.192 ;
    END
  END i[309]
  PIN i[30]
    DIRECTION INPUT ;
    USE SIGNAL ;
    PORT
      LAYER M3 ;
        RECT  5.112 0 5.13 0.144 ;
    END
  END i[30]
  PIN i[310]
    DIRECTION INPUT ;
    USE SIGNAL ;
    PORT
      LAYER M3 ;
        RECT  32.184 0 32.202 0.144 ;
    END
  END i[310]
  PIN i[311]
    DIRECTION INPUT ;
    USE SIGNAL ;
    PORT
      LAYER M5 ;
        RECT  32.256 0 32.28 0.192 ;
    END
  END i[311]
  PIN i[312]
    DIRECTION INPUT ;
    USE SIGNAL ;
    PORT
      LAYER M3 ;
        RECT  32.364 0 32.382 0.144 ;
    END
  END i[312]
  PIN i[313]
    DIRECTION INPUT ;
    USE SIGNAL ;
    PORT
      LAYER M5 ;
        RECT  32.448 0 32.472 0.192 ;
    END
  END i[313]
  PIN i[314]
    DIRECTION INPUT ;
    USE SIGNAL ;
    PORT
      LAYER M3 ;
        RECT  32.58 0 32.598 0.144 ;
    END
  END i[314]
  PIN i[315]
    DIRECTION INPUT ;
    USE SIGNAL ;
    PORT
      LAYER M5 ;
        RECT  32.64 0 32.664 0.192 ;
    END
  END i[315]
  PIN i[316]
    DIRECTION INPUT ;
    USE SIGNAL ;
    PORT
      LAYER M3 ;
        RECT  32.76 0 32.778 0.144 ;
    END
  END i[316]
  PIN i[317]
    DIRECTION INPUT ;
    USE SIGNAL ;
    PORT
      LAYER M5 ;
        RECT  32.832 0 32.856 0.192 ;
    END
  END i[317]
  PIN i[318]
    DIRECTION INPUT ;
    USE SIGNAL ;
    PORT
      LAYER M3 ;
        RECT  32.94 0 32.958 0.144 ;
    END
  END i[318]
  PIN i[319]
    DIRECTION INPUT ;
    USE SIGNAL ;
    PORT
      LAYER M5 ;
        RECT  33.072 0 33.096 0.192 ;
    END
  END i[319]
  PIN i[31]
    DIRECTION INPUT ;
    USE SIGNAL ;
    PORT
      LAYER M5 ;
        RECT  5.184 0 5.208 0.192 ;
    END
  END i[31]
  PIN i[320]
    DIRECTION INPUT ;
    USE SIGNAL ;
    PORT
      LAYER M3 ;
        RECT  33.156 0 33.174 0.144 ;
    END
  END i[320]
  PIN i[321]
    DIRECTION INPUT ;
    USE SIGNAL ;
    PORT
      LAYER M5 ;
        RECT  33.264 0 33.288 0.192 ;
    END
  END i[321]
  PIN i[322]
    DIRECTION INPUT ;
    USE SIGNAL ;
    PORT
      LAYER M3 ;
        RECT  33.336 0 33.354 0.144 ;
    END
  END i[322]
  PIN i[323]
    DIRECTION INPUT ;
    USE SIGNAL ;
    PORT
      LAYER M5 ;
        RECT  33.456 0 33.48 0.192 ;
    END
  END i[323]
  PIN i[324]
    DIRECTION INPUT ;
    USE SIGNAL ;
    PORT
      LAYER M3 ;
        RECT  33.552 0 33.57 0.144 ;
    END
  END i[324]
  PIN i[325]
    DIRECTION INPUT ;
    USE SIGNAL ;
    PORT
      LAYER M5 ;
        RECT  33.648 0 33.672 0.192 ;
    END
  END i[325]
  PIN i[326]
    DIRECTION INPUT ;
    USE SIGNAL ;
    PORT
      LAYER M3 ;
        RECT  33.732 0 33.75 0.144 ;
    END
  END i[326]
  PIN i[327]
    DIRECTION INPUT ;
    USE SIGNAL ;
    PORT
      LAYER M5 ;
        RECT  33.84 0 33.864 0.192 ;
    END
  END i[327]
  PIN i[328]
    DIRECTION INPUT ;
    USE SIGNAL ;
    PORT
      LAYER M3 ;
        RECT  33.912 0 33.93 0.144 ;
    END
  END i[328]
  PIN i[329]
    DIRECTION INPUT ;
    USE SIGNAL ;
    PORT
      LAYER M5 ;
        RECT  34.032 0 34.056 0.192 ;
    END
  END i[329]
  PIN i[32]
    DIRECTION INPUT ;
    USE SIGNAL ;
    PORT
      LAYER M3 ;
        RECT  5.292 0 5.31 0.144 ;
    END
  END i[32]
  PIN i[330]
    DIRECTION INPUT ;
    USE SIGNAL ;
    PORT
      LAYER M3 ;
        RECT  34.128 0 34.146 0.144 ;
    END
  END i[330]
  PIN i[331]
    DIRECTION INPUT ;
    USE SIGNAL ;
    PORT
      LAYER M5 ;
        RECT  34.224 0 34.248 0.192 ;
    END
  END i[331]
  PIN i[332]
    DIRECTION INPUT ;
    USE SIGNAL ;
    PORT
      LAYER M3 ;
        RECT  34.308 0 34.326 0.144 ;
    END
  END i[332]
  PIN i[333]
    DIRECTION INPUT ;
    USE SIGNAL ;
    PORT
      LAYER M5 ;
        RECT  34.416 0 34.44 0.192 ;
    END
  END i[333]
  PIN i[334]
    DIRECTION INPUT ;
    USE SIGNAL ;
    PORT
      LAYER M3 ;
        RECT  34.488 0 34.506 0.144 ;
    END
  END i[334]
  PIN i[335]
    DIRECTION INPUT ;
    USE SIGNAL ;
    PORT
      LAYER M5 ;
        RECT  34.608 0 34.632 0.192 ;
    END
  END i[335]
  PIN i[336]
    DIRECTION INPUT ;
    USE SIGNAL ;
    PORT
      LAYER M3 ;
        RECT  34.704 0 34.722 0.144 ;
    END
  END i[336]
  PIN i[337]
    DIRECTION INPUT ;
    USE SIGNAL ;
    PORT
      LAYER M5 ;
        RECT  34.8 0 34.824 0.192 ;
    END
  END i[337]
  PIN i[338]
    DIRECTION INPUT ;
    USE SIGNAL ;
    PORT
      LAYER M3 ;
        RECT  34.884 0 34.902 0.144 ;
    END
  END i[338]
  PIN i[339]
    DIRECTION INPUT ;
    USE SIGNAL ;
    PORT
      LAYER M5 ;
        RECT  34.992 0 35.016 0.192 ;
    END
  END i[339]
  PIN i[33]
    DIRECTION INPUT ;
    USE SIGNAL ;
    PORT
      LAYER M5 ;
        RECT  5.376 0 5.4 0.192 ;
    END
  END i[33]
  PIN i[340]
    DIRECTION INPUT ;
    USE SIGNAL ;
    PORT
      LAYER M3 ;
        RECT  35.1 0 35.118 0.144 ;
    END
  END i[340]
  PIN i[341]
    DIRECTION INPUT ;
    USE SIGNAL ;
    PORT
      LAYER M5 ;
        RECT  35.184 0 35.208 0.192 ;
    END
  END i[341]
  PIN i[342]
    DIRECTION INPUT ;
    USE SIGNAL ;
    PORT
      LAYER M3 ;
        RECT  35.28 0 35.298 0.144 ;
    END
  END i[342]
  PIN i[343]
    DIRECTION INPUT ;
    USE SIGNAL ;
    PORT
      LAYER M5 ;
        RECT  35.376 0 35.4 0.192 ;
    END
  END i[343]
  PIN i[344]
    DIRECTION INPUT ;
    USE SIGNAL ;
    PORT
      LAYER M3 ;
        RECT  35.46 0 35.478 0.144 ;
    END
  END i[344]
  PIN i[345]
    DIRECTION INPUT ;
    USE SIGNAL ;
    PORT
      LAYER M5 ;
        RECT  35.568 0 35.592 0.192 ;
    END
  END i[345]
  PIN i[346]
    DIRECTION INPUT ;
    USE SIGNAL ;
    PORT
      LAYER M3 ;
        RECT  35.676 0 35.694 0.144 ;
    END
  END i[346]
  PIN i[347]
    DIRECTION INPUT ;
    USE SIGNAL ;
    PORT
      LAYER M5 ;
        RECT  35.76 0 35.784 0.192 ;
    END
  END i[347]
  PIN i[348]
    DIRECTION INPUT ;
    USE SIGNAL ;
    PORT
      LAYER M3 ;
        RECT  35.856 0 35.874 0.144 ;
    END
  END i[348]
  PIN i[349]
    DIRECTION INPUT ;
    USE SIGNAL ;
    PORT
      LAYER M5 ;
        RECT  35.952 0 35.976 0.192 ;
    END
  END i[349]
  PIN i[34]
    DIRECTION INPUT ;
    USE SIGNAL ;
    PORT
      LAYER M3 ;
        RECT  5.472 0 5.49 0.144 ;
    END
  END i[34]
  PIN i[350]
    DIRECTION INPUT ;
    USE SIGNAL ;
    PORT
      LAYER M3 ;
        RECT  36.036 0 36.054 0.144 ;
    END
  END i[350]
  PIN i[351]
    DIRECTION INPUT ;
    USE SIGNAL ;
    PORT
      LAYER M5 ;
        RECT  36.144 0 36.168 0.192 ;
    END
  END i[351]
  PIN i[352]
    DIRECTION INPUT ;
    USE SIGNAL ;
    PORT
      LAYER M3 ;
        RECT  36.252 0 36.27 0.144 ;
    END
  END i[352]
  PIN i[353]
    DIRECTION INPUT ;
    USE SIGNAL ;
    PORT
      LAYER M5 ;
        RECT  36.336 0 36.36 0.192 ;
    END
  END i[353]
  PIN i[354]
    DIRECTION INPUT ;
    USE SIGNAL ;
    PORT
      LAYER M3 ;
        RECT  36.432 0 36.45 0.144 ;
    END
  END i[354]
  PIN i[355]
    DIRECTION INPUT ;
    USE SIGNAL ;
    PORT
      LAYER M5 ;
        RECT  36.528 0 36.552 0.192 ;
    END
  END i[355]
  PIN i[356]
    DIRECTION INPUT ;
    USE SIGNAL ;
    PORT
      LAYER M3 ;
        RECT  36.648 0 36.666 0.144 ;
    END
  END i[356]
  PIN i[357]
    DIRECTION INPUT ;
    USE SIGNAL ;
    PORT
      LAYER M5 ;
        RECT  36.72 0 36.744 0.192 ;
    END
  END i[357]
  PIN i[358]
    DIRECTION INPUT ;
    USE SIGNAL ;
    PORT
      LAYER M3 ;
        RECT  36.828 0 36.846 0.144 ;
    END
  END i[358]
  PIN i[359]
    DIRECTION INPUT ;
    USE SIGNAL ;
    PORT
      LAYER M5 ;
        RECT  36.912 0 36.936 0.192 ;
    END
  END i[359]
  PIN i[35]
    DIRECTION INPUT ;
    USE SIGNAL ;
    PORT
      LAYER M5 ;
        RECT  5.568 0 5.592 0.192 ;
    END
  END i[35]
  PIN i[360]
    DIRECTION INPUT ;
    USE SIGNAL ;
    PORT
      LAYER M3 ;
        RECT  37.008 0 37.026 0.144 ;
    END
  END i[360]
  PIN i[361]
    DIRECTION INPUT ;
    USE SIGNAL ;
    PORT
      LAYER M5 ;
        RECT  37.104 0 37.128 0.192 ;
    END
  END i[361]
  PIN i[362]
    DIRECTION INPUT ;
    USE SIGNAL ;
    PORT
      LAYER M3 ;
        RECT  37.224 0 37.242 0.144 ;
    END
  END i[362]
  PIN i[363]
    DIRECTION INPUT ;
    USE SIGNAL ;
    PORT
      LAYER M5 ;
        RECT  37.296 0 37.32 0.192 ;
    END
  END i[363]
  PIN i[364]
    DIRECTION INPUT ;
    USE SIGNAL ;
    PORT
      LAYER M3 ;
        RECT  37.404 0 37.422 0.144 ;
    END
  END i[364]
  PIN i[365]
    DIRECTION INPUT ;
    USE SIGNAL ;
    PORT
      LAYER M5 ;
        RECT  37.488 0 37.512 0.192 ;
    END
  END i[365]
  PIN i[366]
    DIRECTION INPUT ;
    USE SIGNAL ;
    PORT
      LAYER M3 ;
        RECT  37.584 0 37.602 0.144 ;
    END
  END i[366]
  PIN i[367]
    DIRECTION INPUT ;
    USE SIGNAL ;
    PORT
      LAYER M5 ;
        RECT  37.68 0 37.704 0.192 ;
    END
  END i[367]
  PIN i[368]
    DIRECTION INPUT ;
    USE SIGNAL ;
    PORT
      LAYER M3 ;
        RECT  37.8 0 37.818 0.144 ;
    END
  END i[368]
  PIN i[369]
    DIRECTION INPUT ;
    USE SIGNAL ;
    PORT
      LAYER M5 ;
        RECT  37.872 0 37.896 0.192 ;
    END
  END i[369]
  PIN i[36]
    DIRECTION INPUT ;
    USE SIGNAL ;
    PORT
      LAYER M3 ;
        RECT  5.688 0 5.706 0.144 ;
    END
  END i[36]
  PIN i[370]
    DIRECTION INPUT ;
    USE SIGNAL ;
    PORT
      LAYER M3 ;
        RECT  37.98 0 37.998 0.144 ;
    END
  END i[370]
  PIN i[371]
    DIRECTION INPUT ;
    USE SIGNAL ;
    PORT
      LAYER M5 ;
        RECT  38.064 0 38.088 0.192 ;
    END
  END i[371]
  PIN i[372]
    DIRECTION INPUT ;
    USE SIGNAL ;
    PORT
      LAYER M3 ;
        RECT  38.16 0 38.178 0.144 ;
    END
  END i[372]
  PIN i[373]
    DIRECTION INPUT ;
    USE SIGNAL ;
    PORT
      LAYER M5 ;
        RECT  38.256 0 38.28 0.192 ;
    END
  END i[373]
  PIN i[374]
    DIRECTION INPUT ;
    USE SIGNAL ;
    PORT
      LAYER M3 ;
        RECT  38.376 0 38.394 0.144 ;
    END
  END i[374]
  PIN i[375]
    DIRECTION INPUT ;
    USE SIGNAL ;
    PORT
      LAYER M5 ;
        RECT  38.448 0 38.472 0.192 ;
    END
  END i[375]
  PIN i[376]
    DIRECTION INPUT ;
    USE SIGNAL ;
    PORT
      LAYER M3 ;
        RECT  38.556 0 38.574 0.144 ;
    END
  END i[376]
  PIN i[377]
    DIRECTION INPUT ;
    USE SIGNAL ;
    PORT
      LAYER M5 ;
        RECT  38.64 0 38.664 0.192 ;
    END
  END i[377]
  PIN i[378]
    DIRECTION INPUT ;
    USE SIGNAL ;
    PORT
      LAYER M3 ;
        RECT  38.772 0 38.79 0.144 ;
    END
  END i[378]
  PIN i[379]
    DIRECTION INPUT ;
    USE SIGNAL ;
    PORT
      LAYER M5 ;
        RECT  38.832 0 38.856 0.192 ;
    END
  END i[379]
  PIN i[37]
    DIRECTION INPUT ;
    USE SIGNAL ;
    PORT
      LAYER M5 ;
        RECT  5.76 0 5.784 0.192 ;
    END
  END i[37]
  PIN i[380]
    DIRECTION INPUT ;
    USE SIGNAL ;
    PORT
      LAYER M3 ;
        RECT  38.952 0 38.97 0.144 ;
    END
  END i[380]
  PIN i[381]
    DIRECTION INPUT ;
    USE SIGNAL ;
    PORT
      LAYER M5 ;
        RECT  39.024 0 39.048 0.192 ;
    END
  END i[381]
  PIN i[382]
    DIRECTION INPUT ;
    USE SIGNAL ;
    PORT
      LAYER M3 ;
        RECT  39.132 0 39.15 0.144 ;
    END
  END i[382]
  PIN i[383]
    DIRECTION INPUT ;
    USE SIGNAL ;
    PORT
      LAYER M5 ;
        RECT  39.216 0 39.24 0.192 ;
    END
  END i[383]
  PIN i[384]
    DIRECTION INPUT ;
    USE SIGNAL ;
    PORT
      LAYER M3 ;
        RECT  39.348 0 39.366 0.144 ;
    END
  END i[384]
  PIN i[385]
    DIRECTION INPUT ;
    USE SIGNAL ;
    PORT
      LAYER M5 ;
        RECT  39.456 0 39.48 0.192 ;
    END
  END i[385]
  PIN i[386]
    DIRECTION INPUT ;
    USE SIGNAL ;
    PORT
      LAYER M3 ;
        RECT  39.528 0 39.546 0.144 ;
    END
  END i[386]
  PIN i[387]
    DIRECTION INPUT ;
    USE SIGNAL ;
    PORT
      LAYER M5 ;
        RECT  39.648 0 39.672 0.192 ;
    END
  END i[387]
  PIN i[388]
    DIRECTION INPUT ;
    USE SIGNAL ;
    PORT
      LAYER M3 ;
        RECT  39.708 0 39.726 0.144 ;
    END
  END i[388]
  PIN i[389]
    DIRECTION INPUT ;
    USE SIGNAL ;
    PORT
      LAYER M5 ;
        RECT  39.84 0 39.864 0.192 ;
    END
  END i[389]
  PIN i[38]
    DIRECTION INPUT ;
    USE SIGNAL ;
    PORT
      LAYER M3 ;
        RECT  5.868 0 5.886 0.144 ;
    END
  END i[38]
  PIN i[390]
    DIRECTION INPUT ;
    USE SIGNAL ;
    PORT
      LAYER M3 ;
        RECT  39.924 0 39.942 0.144 ;
    END
  END i[390]
  PIN i[391]
    DIRECTION INPUT ;
    USE SIGNAL ;
    PORT
      LAYER M5 ;
        RECT  40.032 0 40.056 0.192 ;
    END
  END i[391]
  PIN i[392]
    DIRECTION INPUT ;
    USE SIGNAL ;
    PORT
      LAYER M3 ;
        RECT  40.104 0 40.122 0.144 ;
    END
  END i[392]
  PIN i[393]
    DIRECTION INPUT ;
    USE SIGNAL ;
    PORT
      LAYER M5 ;
        RECT  40.224 0 40.248 0.192 ;
    END
  END i[393]
  PIN i[394]
    DIRECTION INPUT ;
    USE SIGNAL ;
    PORT
      LAYER M3 ;
        RECT  40.32 0 40.338 0.144 ;
    END
  END i[394]
  PIN i[395]
    DIRECTION INPUT ;
    USE SIGNAL ;
    PORT
      LAYER M5 ;
        RECT  40.416 0 40.44 0.192 ;
    END
  END i[395]
  PIN i[396]
    DIRECTION INPUT ;
    USE SIGNAL ;
    PORT
      LAYER M3 ;
        RECT  40.5 0 40.518 0.144 ;
    END
  END i[396]
  PIN i[397]
    DIRECTION INPUT ;
    USE SIGNAL ;
    PORT
      LAYER M5 ;
        RECT  40.608 0 40.632 0.192 ;
    END
  END i[397]
  PIN i[398]
    DIRECTION INPUT ;
    USE SIGNAL ;
    PORT
      LAYER M3 ;
        RECT  40.68 0 40.698 0.144 ;
    END
  END i[398]
  PIN i[399]
    DIRECTION INPUT ;
    USE SIGNAL ;
    PORT
      LAYER M5 ;
        RECT  40.8 0 40.824 0.192 ;
    END
  END i[399]
  PIN i[39]
    DIRECTION INPUT ;
    USE SIGNAL ;
    PORT
      LAYER M5 ;
        RECT  5.952 0 5.976 0.192 ;
    END
  END i[39]
  PIN i[3]
    DIRECTION INPUT ;
    USE SIGNAL ;
    PORT
      LAYER M5 ;
        RECT  2.496 0 2.52 0.192 ;
    END
  END i[3]
  PIN i[400]
    DIRECTION INPUT ;
    USE SIGNAL ;
    PORT
      LAYER M3 ;
        RECT  40.896 0 40.914 0.144 ;
    END
  END i[400]
  PIN i[401]
    DIRECTION INPUT ;
    USE SIGNAL ;
    PORT
      LAYER M5 ;
        RECT  40.992 0 41.016 0.192 ;
    END
  END i[401]
  PIN i[402]
    DIRECTION INPUT ;
    USE SIGNAL ;
    PORT
      LAYER M3 ;
        RECT  41.076 0 41.094 0.144 ;
    END
  END i[402]
  PIN i[403]
    DIRECTION INPUT ;
    USE SIGNAL ;
    PORT
      LAYER M5 ;
        RECT  41.184 0 41.208 0.192 ;
    END
  END i[403]
  PIN i[404]
    DIRECTION INPUT ;
    USE SIGNAL ;
    PORT
      LAYER M3 ;
        RECT  41.256 0 41.274 0.144 ;
    END
  END i[404]
  PIN i[405]
    DIRECTION INPUT ;
    USE SIGNAL ;
    PORT
      LAYER M5 ;
        RECT  41.376 0 41.4 0.192 ;
    END
  END i[405]
  PIN i[406]
    DIRECTION INPUT ;
    USE SIGNAL ;
    PORT
      LAYER M3 ;
        RECT  41.472 0 41.49 0.144 ;
    END
  END i[406]
  PIN i[407]
    DIRECTION INPUT ;
    USE SIGNAL ;
    PORT
      LAYER M5 ;
        RECT  41.568 0 41.592 0.192 ;
    END
  END i[407]
  PIN i[408]
    DIRECTION INPUT ;
    USE SIGNAL ;
    PORT
      LAYER M3 ;
        RECT  41.652 0 41.67 0.144 ;
    END
  END i[408]
  PIN i[409]
    DIRECTION INPUT ;
    USE SIGNAL ;
    PORT
      LAYER M5 ;
        RECT  41.76 0 41.784 0.192 ;
    END
  END i[409]
  PIN i[40]
    DIRECTION INPUT ;
    USE SIGNAL ;
    PORT
      LAYER M3 ;
        RECT  6.084 0 6.102 0.144 ;
    END
  END i[40]
  PIN i[410]
    DIRECTION INPUT ;
    USE SIGNAL ;
    PORT
      LAYER M3 ;
        RECT  41.868 0 41.886 0.144 ;
    END
  END i[410]
  PIN i[411]
    DIRECTION INPUT ;
    USE SIGNAL ;
    PORT
      LAYER M5 ;
        RECT  41.952 0 41.976 0.192 ;
    END
  END i[411]
  PIN i[412]
    DIRECTION INPUT ;
    USE SIGNAL ;
    PORT
      LAYER M3 ;
        RECT  42.048 0 42.066 0.144 ;
    END
  END i[412]
  PIN i[413]
    DIRECTION INPUT ;
    USE SIGNAL ;
    PORT
      LAYER M5 ;
        RECT  42.144 0 42.168 0.192 ;
    END
  END i[413]
  PIN i[414]
    DIRECTION INPUT ;
    USE SIGNAL ;
    PORT
      LAYER M3 ;
        RECT  42.228 0 42.246 0.144 ;
    END
  END i[414]
  PIN i[415]
    DIRECTION INPUT ;
    USE SIGNAL ;
    PORT
      LAYER M5 ;
        RECT  42.336 0 42.36 0.192 ;
    END
  END i[415]
  PIN i[416]
    DIRECTION INPUT ;
    USE SIGNAL ;
    PORT
      LAYER M3 ;
        RECT  42.444 0 42.462 0.144 ;
    END
  END i[416]
  PIN i[417]
    DIRECTION INPUT ;
    USE SIGNAL ;
    PORT
      LAYER M5 ;
        RECT  42.528 0 42.552 0.192 ;
    END
  END i[417]
  PIN i[418]
    DIRECTION INPUT ;
    USE SIGNAL ;
    PORT
      LAYER M3 ;
        RECT  42.624 0 42.642 0.144 ;
    END
  END i[418]
  PIN i[419]
    DIRECTION INPUT ;
    USE SIGNAL ;
    PORT
      LAYER M5 ;
        RECT  42.72 0 42.744 0.192 ;
    END
  END i[419]
  PIN i[41]
    DIRECTION INPUT ;
    USE SIGNAL ;
    PORT
      LAYER M5 ;
        RECT  6.144 0 6.168 0.192 ;
    END
  END i[41]
  PIN i[420]
    DIRECTION INPUT ;
    USE SIGNAL ;
    PORT
      LAYER M3 ;
        RECT  42.804 0 42.822 0.144 ;
    END
  END i[420]
  PIN i[421]
    DIRECTION INPUT ;
    USE SIGNAL ;
    PORT
      LAYER M5 ;
        RECT  42.912 0 42.936 0.192 ;
    END
  END i[421]
  PIN i[422]
    DIRECTION INPUT ;
    USE SIGNAL ;
    PORT
      LAYER M3 ;
        RECT  43.02 0 43.038 0.144 ;
    END
  END i[422]
  PIN i[423]
    DIRECTION INPUT ;
    USE SIGNAL ;
    PORT
      LAYER M5 ;
        RECT  43.104 0 43.128 0.192 ;
    END
  END i[423]
  PIN i[424]
    DIRECTION INPUT ;
    USE SIGNAL ;
    PORT
      LAYER M3 ;
        RECT  43.2 0 43.218 0.144 ;
    END
  END i[424]
  PIN i[425]
    DIRECTION INPUT ;
    USE SIGNAL ;
    PORT
      LAYER M5 ;
        RECT  43.296 0 43.32 0.192 ;
    END
  END i[425]
  PIN i[426]
    DIRECTION INPUT ;
    USE SIGNAL ;
    PORT
      LAYER M3 ;
        RECT  43.416 0 43.434 0.144 ;
    END
  END i[426]
  PIN i[427]
    DIRECTION INPUT ;
    USE SIGNAL ;
    PORT
      LAYER M5 ;
        RECT  43.488 0 43.512 0.192 ;
    END
  END i[427]
  PIN i[428]
    DIRECTION INPUT ;
    USE SIGNAL ;
    PORT
      LAYER M3 ;
        RECT  43.596 0 43.614 0.144 ;
    END
  END i[428]
  PIN i[429]
    DIRECTION INPUT ;
    USE SIGNAL ;
    PORT
      LAYER M5 ;
        RECT  43.68 0 43.704 0.192 ;
    END
  END i[429]
  PIN i[42]
    DIRECTION INPUT ;
    USE SIGNAL ;
    PORT
      LAYER M3 ;
        RECT  6.264 0 6.282 0.144 ;
    END
  END i[42]
  PIN i[430]
    DIRECTION INPUT ;
    USE SIGNAL ;
    PORT
      LAYER M3 ;
        RECT  43.776 0 43.794 0.144 ;
    END
  END i[430]
  PIN i[431]
    DIRECTION INPUT ;
    USE SIGNAL ;
    PORT
      LAYER M5 ;
        RECT  43.872 0 43.896 0.192 ;
    END
  END i[431]
  PIN i[432]
    DIRECTION INPUT ;
    USE SIGNAL ;
    PORT
      LAYER M3 ;
        RECT  43.992 0 44.01 0.144 ;
    END
  END i[432]
  PIN i[433]
    DIRECTION INPUT ;
    USE SIGNAL ;
    PORT
      LAYER M5 ;
        RECT  44.064 0 44.088 0.192 ;
    END
  END i[433]
  PIN i[434]
    DIRECTION INPUT ;
    USE SIGNAL ;
    PORT
      LAYER M3 ;
        RECT  44.172 0 44.19 0.144 ;
    END
  END i[434]
  PIN i[435]
    DIRECTION INPUT ;
    USE SIGNAL ;
    PORT
      LAYER M5 ;
        RECT  44.256 0 44.28 0.192 ;
    END
  END i[435]
  PIN i[436]
    DIRECTION INPUT ;
    USE SIGNAL ;
    PORT
      LAYER M3 ;
        RECT  44.352 0 44.37 0.144 ;
    END
  END i[436]
  PIN i[437]
    DIRECTION INPUT ;
    USE SIGNAL ;
    PORT
      LAYER M5 ;
        RECT  44.448 0 44.472 0.192 ;
    END
  END i[437]
  PIN i[438]
    DIRECTION INPUT ;
    USE SIGNAL ;
    PORT
      LAYER M3 ;
        RECT  44.568 0 44.586 0.144 ;
    END
  END i[438]
  PIN i[439]
    DIRECTION INPUT ;
    USE SIGNAL ;
    PORT
      LAYER M5 ;
        RECT  44.64 0 44.664 0.192 ;
    END
  END i[439]
  PIN i[43]
    DIRECTION INPUT ;
    USE SIGNAL ;
    PORT
      LAYER M5 ;
        RECT  6.336 0 6.36 0.192 ;
    END
  END i[43]
  PIN i[440]
    DIRECTION INPUT ;
    USE SIGNAL ;
    PORT
      LAYER M3 ;
        RECT  44.748 0 44.766 0.144 ;
    END
  END i[440]
  PIN i[441]
    DIRECTION INPUT ;
    USE SIGNAL ;
    PORT
      LAYER M5 ;
        RECT  44.832 0 44.856 0.192 ;
    END
  END i[441]
  PIN i[442]
    DIRECTION INPUT ;
    USE SIGNAL ;
    PORT
      LAYER M3 ;
        RECT  44.964 0 44.982 0.144 ;
    END
  END i[442]
  PIN i[443]
    DIRECTION INPUT ;
    USE SIGNAL ;
    PORT
      LAYER M5 ;
        RECT  45.024 0 45.048 0.192 ;
    END
  END i[443]
  PIN i[444]
    DIRECTION INPUT ;
    USE SIGNAL ;
    PORT
      LAYER M3 ;
        RECT  45.144 0 45.162 0.144 ;
    END
  END i[444]
  PIN i[445]
    DIRECTION INPUT ;
    USE SIGNAL ;
    PORT
      LAYER M5 ;
        RECT  45.216 0 45.24 0.192 ;
    END
  END i[445]
  PIN i[446]
    DIRECTION INPUT ;
    USE SIGNAL ;
    PORT
      LAYER M3 ;
        RECT  45.324 0 45.342 0.144 ;
    END
  END i[446]
  PIN i[447]
    DIRECTION INPUT ;
    USE SIGNAL ;
    PORT
      LAYER M5 ;
        RECT  45.408 0 45.432 0.192 ;
    END
  END i[447]
  PIN i[448]
    DIRECTION INPUT ;
    USE SIGNAL ;
    PORT
      LAYER M3 ;
        RECT  45.54 0 45.558 0.144 ;
    END
  END i[448]
  PIN i[449]
    DIRECTION INPUT ;
    USE SIGNAL ;
    PORT
      LAYER M5 ;
        RECT  45.6 0 45.624 0.192 ;
    END
  END i[449]
  PIN i[44]
    DIRECTION INPUT ;
    USE SIGNAL ;
    PORT
      LAYER M3 ;
        RECT  6.444 0 6.462 0.144 ;
    END
  END i[44]
  PIN i[450]
    DIRECTION INPUT ;
    USE SIGNAL ;
    PORT
      LAYER M3 ;
        RECT  45.72 0 45.738 0.144 ;
    END
  END i[450]
  PIN i[451]
    DIRECTION INPUT ;
    USE SIGNAL ;
    PORT
      LAYER M5 ;
        RECT  45.792 0 45.816 0.192 ;
    END
  END i[451]
  PIN i[452]
    DIRECTION INPUT ;
    USE SIGNAL ;
    PORT
      LAYER M3 ;
        RECT  45.9 0 45.918 0.144 ;
    END
  END i[452]
  PIN i[453]
    DIRECTION INPUT ;
    USE SIGNAL ;
    PORT
      LAYER M5 ;
        RECT  46.032 0 46.056 0.192 ;
    END
  END i[453]
  PIN i[454]
    DIRECTION INPUT ;
    USE SIGNAL ;
    PORT
      LAYER M3 ;
        RECT  46.116 0 46.134 0.144 ;
    END
  END i[454]
  PIN i[455]
    DIRECTION INPUT ;
    USE SIGNAL ;
    PORT
      LAYER M5 ;
        RECT  46.224 0 46.248 0.192 ;
    END
  END i[455]
  PIN i[456]
    DIRECTION INPUT ;
    USE SIGNAL ;
    PORT
      LAYER M3 ;
        RECT  46.296 0 46.314 0.144 ;
    END
  END i[456]
  PIN i[457]
    DIRECTION INPUT ;
    USE SIGNAL ;
    PORT
      LAYER M5 ;
        RECT  46.416 0 46.44 0.192 ;
    END
  END i[457]
  PIN i[458]
    DIRECTION INPUT ;
    USE SIGNAL ;
    PORT
      LAYER M3 ;
        RECT  46.512 0 46.53 0.144 ;
    END
  END i[458]
  PIN i[459]
    DIRECTION INPUT ;
    USE SIGNAL ;
    PORT
      LAYER M5 ;
        RECT  46.608 0 46.632 0.192 ;
    END
  END i[459]
  PIN i[45]
    DIRECTION INPUT ;
    USE SIGNAL ;
    PORT
      LAYER M5 ;
        RECT  6.528 0 6.552 0.192 ;
    END
  END i[45]
  PIN i[460]
    DIRECTION INPUT ;
    USE SIGNAL ;
    PORT
      LAYER M3 ;
        RECT  46.692 0 46.71 0.144 ;
    END
  END i[460]
  PIN i[461]
    DIRECTION INPUT ;
    USE SIGNAL ;
    PORT
      LAYER M5 ;
        RECT  46.8 0 46.824 0.192 ;
    END
  END i[461]
  PIN i[462]
    DIRECTION INPUT ;
    USE SIGNAL ;
    PORT
      LAYER M3 ;
        RECT  46.872 0 46.89 0.144 ;
    END
  END i[462]
  PIN i[463]
    DIRECTION INPUT ;
    USE SIGNAL ;
    PORT
      LAYER M5 ;
        RECT  46.992 0 47.016 0.192 ;
    END
  END i[463]
  PIN i[464]
    DIRECTION INPUT ;
    USE SIGNAL ;
    PORT
      LAYER M3 ;
        RECT  47.088 0 47.106 0.144 ;
    END
  END i[464]
  PIN i[465]
    DIRECTION INPUT ;
    USE SIGNAL ;
    PORT
      LAYER M5 ;
        RECT  47.184 0 47.208 0.192 ;
    END
  END i[465]
  PIN i[466]
    DIRECTION INPUT ;
    USE SIGNAL ;
    PORT
      LAYER M3 ;
        RECT  47.268 0 47.286 0.144 ;
    END
  END i[466]
  PIN i[467]
    DIRECTION INPUT ;
    USE SIGNAL ;
    PORT
      LAYER M5 ;
        RECT  47.376 0 47.4 0.192 ;
    END
  END i[467]
  PIN i[468]
    DIRECTION INPUT ;
    USE SIGNAL ;
    PORT
      LAYER M3 ;
        RECT  47.448 0 47.466 0.144 ;
    END
  END i[468]
  PIN i[469]
    DIRECTION INPUT ;
    USE SIGNAL ;
    PORT
      LAYER M5 ;
        RECT  47.568 0 47.592 0.192 ;
    END
  END i[469]
  PIN i[46]
    DIRECTION INPUT ;
    USE SIGNAL ;
    PORT
      LAYER M3 ;
        RECT  6.66 0 6.678 0.144 ;
    END
  END i[46]
  PIN i[470]
    DIRECTION INPUT ;
    USE SIGNAL ;
    PORT
      LAYER M3 ;
        RECT  47.664 0 47.682 0.144 ;
    END
  END i[470]
  PIN i[471]
    DIRECTION INPUT ;
    USE SIGNAL ;
    PORT
      LAYER M5 ;
        RECT  47.76 0 47.784 0.192 ;
    END
  END i[471]
  PIN i[472]
    DIRECTION INPUT ;
    USE SIGNAL ;
    PORT
      LAYER M3 ;
        RECT  47.844 0 47.862 0.144 ;
    END
  END i[472]
  PIN i[473]
    DIRECTION INPUT ;
    USE SIGNAL ;
    PORT
      LAYER M5 ;
        RECT  47.952 0 47.976 0.192 ;
    END
  END i[473]
  PIN i[474]
    DIRECTION INPUT ;
    USE SIGNAL ;
    PORT
      LAYER M3 ;
        RECT  48.06 0 48.078 0.144 ;
    END
  END i[474]
  PIN i[475]
    DIRECTION INPUT ;
    USE SIGNAL ;
    PORT
      LAYER M5 ;
        RECT  48.144 0 48.168 0.192 ;
    END
  END i[475]
  PIN i[476]
    DIRECTION INPUT ;
    USE SIGNAL ;
    PORT
      LAYER M3 ;
        RECT  48.24 0 48.258 0.144 ;
    END
  END i[476]
  PIN i[477]
    DIRECTION INPUT ;
    USE SIGNAL ;
    PORT
      LAYER M5 ;
        RECT  48.336 0 48.36 0.192 ;
    END
  END i[477]
  PIN i[478]
    DIRECTION INPUT ;
    USE SIGNAL ;
    PORT
      LAYER M3 ;
        RECT  48.42 0 48.438 0.144 ;
    END
  END i[478]
  PIN i[479]
    DIRECTION INPUT ;
    USE SIGNAL ;
    PORT
      LAYER M5 ;
        RECT  48.528 0 48.552 0.192 ;
    END
  END i[479]
  PIN i[47]
    DIRECTION INPUT ;
    USE SIGNAL ;
    PORT
      LAYER M5 ;
        RECT  6.72 0 6.744 0.192 ;
    END
  END i[47]
  PIN i[480]
    DIRECTION INPUT ;
    USE SIGNAL ;
    PORT
      LAYER M3 ;
        RECT  48.636 0 48.654 0.144 ;
    END
  END i[480]
  PIN i[481]
    DIRECTION INPUT ;
    USE SIGNAL ;
    PORT
      LAYER M5 ;
        RECT  48.72 0 48.744 0.192 ;
    END
  END i[481]
  PIN i[482]
    DIRECTION INPUT ;
    USE SIGNAL ;
    PORT
      LAYER M3 ;
        RECT  48.816 0 48.834 0.144 ;
    END
  END i[482]
  PIN i[483]
    DIRECTION INPUT ;
    USE SIGNAL ;
    PORT
      LAYER M5 ;
        RECT  48.912 0 48.936 0.192 ;
    END
  END i[483]
  PIN i[484]
    DIRECTION INPUT ;
    USE SIGNAL ;
    PORT
      LAYER M3 ;
        RECT  48.996 0 49.014 0.144 ;
    END
  END i[484]
  PIN i[485]
    DIRECTION INPUT ;
    USE SIGNAL ;
    PORT
      LAYER M5 ;
        RECT  49.104 0 49.128 0.192 ;
    END
  END i[485]
  PIN i[486]
    DIRECTION INPUT ;
    USE SIGNAL ;
    PORT
      LAYER M3 ;
        RECT  49.212 0 49.23 0.144 ;
    END
  END i[486]
  PIN i[487]
    DIRECTION INPUT ;
    USE SIGNAL ;
    PORT
      LAYER M5 ;
        RECT  49.296 0 49.32 0.192 ;
    END
  END i[487]
  PIN i[488]
    DIRECTION INPUT ;
    USE SIGNAL ;
    PORT
      LAYER M3 ;
        RECT  49.392 0 49.41 0.144 ;
    END
  END i[488]
  PIN i[489]
    DIRECTION INPUT ;
    USE SIGNAL ;
    PORT
      LAYER M5 ;
        RECT  49.488 0 49.512 0.192 ;
    END
  END i[489]
  PIN i[48]
    DIRECTION INPUT ;
    USE SIGNAL ;
    PORT
      LAYER M3 ;
        RECT  6.84 0 6.858 0.144 ;
    END
  END i[48]
  PIN i[490]
    DIRECTION INPUT ;
    USE SIGNAL ;
    PORT
      LAYER M3 ;
        RECT  49.608 0 49.626 0.144 ;
    END
  END i[490]
  PIN i[491]
    DIRECTION INPUT ;
    USE SIGNAL ;
    PORT
      LAYER M5 ;
        RECT  49.68 0 49.704 0.192 ;
    END
  END i[491]
  PIN i[492]
    DIRECTION INPUT ;
    USE SIGNAL ;
    PORT
      LAYER M3 ;
        RECT  49.788 0 49.806 0.144 ;
    END
  END i[492]
  PIN i[493]
    DIRECTION INPUT ;
    USE SIGNAL ;
    PORT
      LAYER M5 ;
        RECT  49.872 0 49.896 0.192 ;
    END
  END i[493]
  PIN i[494]
    DIRECTION INPUT ;
    USE SIGNAL ;
    PORT
      LAYER M3 ;
        RECT  49.968 0 49.986 0.144 ;
    END
  END i[494]
  PIN i[495]
    DIRECTION INPUT ;
    USE SIGNAL ;
    PORT
      LAYER M5 ;
        RECT  50.064 0 50.088 0.192 ;
    END
  END i[495]
  PIN i[496]
    DIRECTION INPUT ;
    USE SIGNAL ;
    PORT
      LAYER M3 ;
        RECT  50.184 0 50.202 0.144 ;
    END
  END i[496]
  PIN i[497]
    DIRECTION INPUT ;
    USE SIGNAL ;
    PORT
      LAYER M5 ;
        RECT  50.256 0 50.28 0.192 ;
    END
  END i[497]
  PIN i[498]
    DIRECTION INPUT ;
    USE SIGNAL ;
    PORT
      LAYER M3 ;
        RECT  50.364 0 50.382 0.144 ;
    END
  END i[498]
  PIN i[499]
    DIRECTION INPUT ;
    USE SIGNAL ;
    PORT
      LAYER M5 ;
        RECT  50.448 0 50.472 0.192 ;
    END
  END i[499]
  PIN i[49]
    DIRECTION INPUT ;
    USE SIGNAL ;
    PORT
      LAYER M5 ;
        RECT  6.912 0 6.936 0.192 ;
    END
  END i[49]
  PIN i[4]
    DIRECTION INPUT ;
    USE SIGNAL ;
    PORT
      LAYER M3 ;
        RECT  2.592 0 2.61 0.144 ;
    END
  END i[4]
  PIN i[500]
    DIRECTION INPUT ;
    USE SIGNAL ;
    PORT
      LAYER M3 ;
        RECT  50.544 0 50.562 0.144 ;
    END
  END i[500]
  PIN i[501]
    DIRECTION INPUT ;
    USE SIGNAL ;
    PORT
      LAYER M5 ;
        RECT  50.64 0 50.664 0.192 ;
    END
  END i[501]
  PIN i[502]
    DIRECTION INPUT ;
    USE SIGNAL ;
    PORT
      LAYER M3 ;
        RECT  50.76 0 50.778 0.144 ;
    END
  END i[502]
  PIN i[503]
    DIRECTION INPUT ;
    USE SIGNAL ;
    PORT
      LAYER M5 ;
        RECT  50.832 0 50.856 0.192 ;
    END
  END i[503]
  PIN i[504]
    DIRECTION INPUT ;
    USE SIGNAL ;
    PORT
      LAYER M3 ;
        RECT  50.94 0 50.958 0.144 ;
    END
  END i[504]
  PIN i[505]
    DIRECTION INPUT ;
    USE SIGNAL ;
    PORT
      LAYER M5 ;
        RECT  51.024 0 51.048 0.192 ;
    END
  END i[505]
  PIN i[506]
    DIRECTION INPUT ;
    USE SIGNAL ;
    PORT
      LAYER M3 ;
        RECT  51.12 0 51.138 0.144 ;
    END
  END i[506]
  PIN i[507]
    DIRECTION INPUT ;
    USE SIGNAL ;
    PORT
      LAYER M5 ;
        RECT  51.216 0 51.24 0.192 ;
    END
  END i[507]
  PIN i[508]
    DIRECTION INPUT ;
    USE SIGNAL ;
    PORT
      LAYER M3 ;
        RECT  51.336 0 51.354 0.144 ;
    END
  END i[508]
  PIN i[509]
    DIRECTION INPUT ;
    USE SIGNAL ;
    PORT
      LAYER M5 ;
        RECT  51.408 0 51.432 0.192 ;
    END
  END i[509]
  PIN i[50]
    DIRECTION INPUT ;
    USE SIGNAL ;
    PORT
      LAYER M3 ;
        RECT  7.02 0 7.038 0.144 ;
    END
  END i[50]
  PIN i[510]
    DIRECTION INPUT ;
    USE SIGNAL ;
    PORT
      LAYER M3 ;
        RECT  51.516 0 51.534 0.144 ;
    END
  END i[510]
  PIN i[511]
    DIRECTION INPUT ;
    USE SIGNAL ;
    PORT
      LAYER M5 ;
        RECT  51.6 0 51.624 0.192 ;
    END
  END i[511]
  PIN i[512]
    DIRECTION INPUT ;
    USE SIGNAL ;
    PORT
      LAYER M3 ;
        RECT  51.732 0 51.75 0.144 ;
    END
  END i[512]
  PIN i[513]
    DIRECTION INPUT ;
    USE SIGNAL ;
    PORT
      LAYER M5 ;
        RECT  51.792 0 51.816 0.192 ;
    END
  END i[513]
  PIN i[514]
    DIRECTION INPUT ;
    USE SIGNAL ;
    PORT
      LAYER M3 ;
        RECT  51.912 0 51.93 0.144 ;
    END
  END i[514]
  PIN i[515]
    DIRECTION INPUT ;
    USE SIGNAL ;
    PORT
      LAYER M5 ;
        RECT  51.984 0 52.008 0.192 ;
    END
  END i[515]
  PIN i[516]
    DIRECTION INPUT ;
    USE SIGNAL ;
    PORT
      LAYER M3 ;
        RECT  52.092 0 52.11 0.144 ;
    END
  END i[516]
  PIN i[517]
    DIRECTION INPUT ;
    USE SIGNAL ;
    PORT
      LAYER M5 ;
        RECT  52.176 0 52.2 0.192 ;
    END
  END i[517]
  PIN i[518]
    DIRECTION INPUT ;
    USE SIGNAL ;
    PORT
      LAYER M3 ;
        RECT  52.308 0 52.326 0.144 ;
    END
  END i[518]
  PIN i[519]
    DIRECTION INPUT ;
    USE SIGNAL ;
    PORT
      LAYER M5 ;
        RECT  52.416 0 52.44 0.192 ;
    END
  END i[519]
  PIN i[51]
    DIRECTION INPUT ;
    USE SIGNAL ;
    PORT
      LAYER M5 ;
        RECT  7.152 0 7.176 0.192 ;
    END
  END i[51]
  PIN i[520]
    DIRECTION INPUT ;
    USE SIGNAL ;
    PORT
      LAYER M3 ;
        RECT  52.488 0 52.506 0.144 ;
    END
  END i[520]
  PIN i[521]
    DIRECTION INPUT ;
    USE SIGNAL ;
    PORT
      LAYER M5 ;
        RECT  52.608 0 52.632 0.192 ;
    END
  END i[521]
  PIN i[522]
    DIRECTION INPUT ;
    USE SIGNAL ;
    PORT
      LAYER M3 ;
        RECT  52.668 0 52.686 0.144 ;
    END
  END i[522]
  PIN i[523]
    DIRECTION INPUT ;
    USE SIGNAL ;
    PORT
      LAYER M5 ;
        RECT  52.8 0 52.824 0.192 ;
    END
  END i[523]
  PIN i[524]
    DIRECTION INPUT ;
    USE SIGNAL ;
    PORT
      LAYER M3 ;
        RECT  52.884 0 52.902 0.144 ;
    END
  END i[524]
  PIN i[525]
    DIRECTION INPUT ;
    USE SIGNAL ;
    PORT
      LAYER M5 ;
        RECT  52.992 0 53.016 0.192 ;
    END
  END i[525]
  PIN i[526]
    DIRECTION INPUT ;
    USE SIGNAL ;
    PORT
      LAYER M3 ;
        RECT  53.064 0 53.082 0.144 ;
    END
  END i[526]
  PIN i[527]
    DIRECTION INPUT ;
    USE SIGNAL ;
    PORT
      LAYER M5 ;
        RECT  53.184 0 53.208 0.192 ;
    END
  END i[527]
  PIN i[528]
    DIRECTION INPUT ;
    USE SIGNAL ;
    PORT
      LAYER M3 ;
        RECT  53.28 0 53.298 0.144 ;
    END
  END i[528]
  PIN i[529]
    DIRECTION INPUT ;
    USE SIGNAL ;
    PORT
      LAYER M5 ;
        RECT  53.376 0 53.4 0.192 ;
    END
  END i[529]
  PIN i[52]
    DIRECTION INPUT ;
    USE SIGNAL ;
    PORT
      LAYER M3 ;
        RECT  7.236 0 7.254 0.144 ;
    END
  END i[52]
  PIN i[530]
    DIRECTION INPUT ;
    USE SIGNAL ;
    PORT
      LAYER M3 ;
        RECT  53.46 0 53.478 0.144 ;
    END
  END i[530]
  PIN i[531]
    DIRECTION INPUT ;
    USE SIGNAL ;
    PORT
      LAYER M5 ;
        RECT  53.568 0 53.592 0.192 ;
    END
  END i[531]
  PIN i[532]
    DIRECTION INPUT ;
    USE SIGNAL ;
    PORT
      LAYER M3 ;
        RECT  53.64 0 53.658 0.144 ;
    END
  END i[532]
  PIN i[533]
    DIRECTION INPUT ;
    USE SIGNAL ;
    PORT
      LAYER M5 ;
        RECT  53.76 0 53.784 0.192 ;
    END
  END i[533]
  PIN i[534]
    DIRECTION INPUT ;
    USE SIGNAL ;
    PORT
      LAYER M3 ;
        RECT  53.856 0 53.874 0.144 ;
    END
  END i[534]
  PIN i[535]
    DIRECTION INPUT ;
    USE SIGNAL ;
    PORT
      LAYER M5 ;
        RECT  53.952 0 53.976 0.192 ;
    END
  END i[535]
  PIN i[53]
    DIRECTION INPUT ;
    USE SIGNAL ;
    PORT
      LAYER M5 ;
        RECT  7.344 0 7.368 0.192 ;
    END
  END i[53]
  PIN i[54]
    DIRECTION INPUT ;
    USE SIGNAL ;
    PORT
      LAYER M3 ;
        RECT  7.416 0 7.434 0.144 ;
    END
  END i[54]
  PIN i[55]
    DIRECTION INPUT ;
    USE SIGNAL ;
    PORT
      LAYER M5 ;
        RECT  7.536 0 7.56 0.192 ;
    END
  END i[55]
  PIN i[56]
    DIRECTION INPUT ;
    USE SIGNAL ;
    PORT
      LAYER M3 ;
        RECT  7.632 0 7.65 0.144 ;
    END
  END i[56]
  PIN i[57]
    DIRECTION INPUT ;
    USE SIGNAL ;
    PORT
      LAYER M5 ;
        RECT  7.728 0 7.752 0.192 ;
    END
  END i[57]
  PIN i[58]
    DIRECTION INPUT ;
    USE SIGNAL ;
    PORT
      LAYER M3 ;
        RECT  7.812 0 7.83 0.144 ;
    END
  END i[58]
  PIN i[59]
    DIRECTION INPUT ;
    USE SIGNAL ;
    PORT
      LAYER M5 ;
        RECT  7.92 0 7.944 0.192 ;
    END
  END i[59]
  PIN i[5]
    DIRECTION INPUT ;
    USE SIGNAL ;
    PORT
      LAYER M5 ;
        RECT  2.688 0 2.712 0.192 ;
    END
  END i[5]
  PIN i[60]
    DIRECTION INPUT ;
    USE SIGNAL ;
    PORT
      LAYER M3 ;
        RECT  7.992 0 8.01 0.144 ;
    END
  END i[60]
  PIN i[61]
    DIRECTION INPUT ;
    USE SIGNAL ;
    PORT
      LAYER M5 ;
        RECT  8.112 0 8.136 0.192 ;
    END
  END i[61]
  PIN i[62]
    DIRECTION INPUT ;
    USE SIGNAL ;
    PORT
      LAYER M3 ;
        RECT  8.208 0 8.226 0.144 ;
    END
  END i[62]
  PIN i[63]
    DIRECTION INPUT ;
    USE SIGNAL ;
    PORT
      LAYER M5 ;
        RECT  8.304 0 8.328 0.192 ;
    END
  END i[63]
  PIN i[64]
    DIRECTION INPUT ;
    USE SIGNAL ;
    PORT
      LAYER M3 ;
        RECT  8.388 0 8.406 0.144 ;
    END
  END i[64]
  PIN i[65]
    DIRECTION INPUT ;
    USE SIGNAL ;
    PORT
      LAYER M5 ;
        RECT  8.496 0 8.52 0.192 ;
    END
  END i[65]
  PIN i[66]
    DIRECTION INPUT ;
    USE SIGNAL ;
    PORT
      LAYER M3 ;
        RECT  8.568 0 8.586 0.144 ;
    END
  END i[66]
  PIN i[67]
    DIRECTION INPUT ;
    USE SIGNAL ;
    PORT
      LAYER M5 ;
        RECT  8.688 0 8.712 0.192 ;
    END
  END i[67]
  PIN i[68]
    DIRECTION INPUT ;
    USE SIGNAL ;
    PORT
      LAYER M3 ;
        RECT  8.784 0 8.802 0.144 ;
    END
  END i[68]
  PIN i[69]
    DIRECTION INPUT ;
    USE SIGNAL ;
    PORT
      LAYER M5 ;
        RECT  8.88 0 8.904 0.192 ;
    END
  END i[69]
  PIN i[6]
    DIRECTION INPUT ;
    USE SIGNAL ;
    PORT
      LAYER M3 ;
        RECT  2.772 0 2.79 0.144 ;
    END
  END i[6]
  PIN i[70]
    DIRECTION INPUT ;
    USE SIGNAL ;
    PORT
      LAYER M3 ;
        RECT  8.964 0 8.982 0.144 ;
    END
  END i[70]
  PIN i[71]
    DIRECTION INPUT ;
    USE SIGNAL ;
    PORT
      LAYER M5 ;
        RECT  9.072 0 9.096 0.192 ;
    END
  END i[71]
  PIN i[72]
    DIRECTION INPUT ;
    USE SIGNAL ;
    PORT
      LAYER M3 ;
        RECT  9.18 0 9.198 0.144 ;
    END
  END i[72]
  PIN i[73]
    DIRECTION INPUT ;
    USE SIGNAL ;
    PORT
      LAYER M5 ;
        RECT  9.264 0 9.288 0.192 ;
    END
  END i[73]
  PIN i[74]
    DIRECTION INPUT ;
    USE SIGNAL ;
    PORT
      LAYER M3 ;
        RECT  9.36 0 9.378 0.144 ;
    END
  END i[74]
  PIN i[75]
    DIRECTION INPUT ;
    USE SIGNAL ;
    PORT
      LAYER M5 ;
        RECT  9.456 0 9.48 0.192 ;
    END
  END i[75]
  PIN i[76]
    DIRECTION INPUT ;
    USE SIGNAL ;
    PORT
      LAYER M3 ;
        RECT  9.54 0 9.558 0.144 ;
    END
  END i[76]
  PIN i[77]
    DIRECTION INPUT ;
    USE SIGNAL ;
    PORT
      LAYER M5 ;
        RECT  9.648 0 9.672 0.192 ;
    END
  END i[77]
  PIN i[78]
    DIRECTION INPUT ;
    USE SIGNAL ;
    PORT
      LAYER M3 ;
        RECT  9.756 0 9.774 0.144 ;
    END
  END i[78]
  PIN i[79]
    DIRECTION INPUT ;
    USE SIGNAL ;
    PORT
      LAYER M5 ;
        RECT  9.84 0 9.864 0.192 ;
    END
  END i[79]
  PIN i[7]
    DIRECTION INPUT ;
    USE SIGNAL ;
    PORT
      LAYER M5 ;
        RECT  2.88 0 2.904 0.192 ;
    END
  END i[7]
  PIN i[80]
    DIRECTION INPUT ;
    USE SIGNAL ;
    PORT
      LAYER M3 ;
        RECT  9.936 0 9.954 0.144 ;
    END
  END i[80]
  PIN i[81]
    DIRECTION INPUT ;
    USE SIGNAL ;
    PORT
      LAYER M5 ;
        RECT  10.032 0 10.056 0.192 ;
    END
  END i[81]
  PIN i[82]
    DIRECTION INPUT ;
    USE SIGNAL ;
    PORT
      LAYER M3 ;
        RECT  10.116 0 10.134 0.144 ;
    END
  END i[82]
  PIN i[83]
    DIRECTION INPUT ;
    USE SIGNAL ;
    PORT
      LAYER M5 ;
        RECT  10.224 0 10.248 0.192 ;
    END
  END i[83]
  PIN i[84]
    DIRECTION INPUT ;
    USE SIGNAL ;
    PORT
      LAYER M3 ;
        RECT  10.332 0 10.35 0.144 ;
    END
  END i[84]
  PIN i[85]
    DIRECTION INPUT ;
    USE SIGNAL ;
    PORT
      LAYER M5 ;
        RECT  10.416 0 10.44 0.192 ;
    END
  END i[85]
  PIN i[86]
    DIRECTION INPUT ;
    USE SIGNAL ;
    PORT
      LAYER M3 ;
        RECT  10.512 0 10.53 0.144 ;
    END
  END i[86]
  PIN i[87]
    DIRECTION INPUT ;
    USE SIGNAL ;
    PORT
      LAYER M5 ;
        RECT  10.608 0 10.632 0.192 ;
    END
  END i[87]
  PIN i[88]
    DIRECTION INPUT ;
    USE SIGNAL ;
    PORT
      LAYER M3 ;
        RECT  10.728 0 10.746 0.144 ;
    END
  END i[88]
  PIN i[89]
    DIRECTION INPUT ;
    USE SIGNAL ;
    PORT
      LAYER M5 ;
        RECT  10.8 0 10.824 0.192 ;
    END
  END i[89]
  PIN i[8]
    DIRECTION INPUT ;
    USE SIGNAL ;
    PORT
      LAYER M3 ;
        RECT  2.988 0 3.006 0.144 ;
    END
  END i[8]
  PIN i[90]
    DIRECTION INPUT ;
    USE SIGNAL ;
    PORT
      LAYER M3 ;
        RECT  10.908 0 10.926 0.144 ;
    END
  END i[90]
  PIN i[91]
    DIRECTION INPUT ;
    USE SIGNAL ;
    PORT
      LAYER M5 ;
        RECT  10.992 0 11.016 0.192 ;
    END
  END i[91]
  PIN i[92]
    DIRECTION INPUT ;
    USE SIGNAL ;
    PORT
      LAYER M3 ;
        RECT  11.088 0 11.106 0.144 ;
    END
  END i[92]
  PIN i[93]
    DIRECTION INPUT ;
    USE SIGNAL ;
    PORT
      LAYER M5 ;
        RECT  11.184 0 11.208 0.192 ;
    END
  END i[93]
  PIN i[94]
    DIRECTION INPUT ;
    USE SIGNAL ;
    PORT
      LAYER M3 ;
        RECT  11.304 0 11.322 0.144 ;
    END
  END i[94]
  PIN i[95]
    DIRECTION INPUT ;
    USE SIGNAL ;
    PORT
      LAYER M5 ;
        RECT  11.376 0 11.4 0.192 ;
    END
  END i[95]
  PIN i[96]
    DIRECTION INPUT ;
    USE SIGNAL ;
    PORT
      LAYER M3 ;
        RECT  11.484 0 11.502 0.144 ;
    END
  END i[96]
  PIN i[97]
    DIRECTION INPUT ;
    USE SIGNAL ;
    PORT
      LAYER M5 ;
        RECT  11.568 0 11.592 0.192 ;
    END
  END i[97]
  PIN i[98]
    DIRECTION INPUT ;
    USE SIGNAL ;
    PORT
      LAYER M3 ;
        RECT  11.664 0 11.682 0.144 ;
    END
  END i[98]
  PIN i[99]
    DIRECTION INPUT ;
    USE SIGNAL ;
    PORT
      LAYER M5 ;
        RECT  11.76 0 11.784 0.192 ;
    END
  END i[99]
  PIN i[9]
    DIRECTION INPUT ;
    USE SIGNAL ;
    PORT
      LAYER M5 ;
        RECT  3.072 0 3.096 0.192 ;
    END
  END i[9]
  PIN o[0]
    DIRECTION OUTPUT ;
    USE SIGNAL ;
    PORT
      LAYER M3 ;
        RECT  2.196 56.016 2.214 56.16 ;
    END
  END o[0]
  PIN o[100]
    DIRECTION OUTPUT ;
    USE SIGNAL ;
    PORT
      LAYER M3 ;
        RECT  11.88 56.016 11.898 56.16 ;
    END
  END o[100]
  PIN o[101]
    DIRECTION OUTPUT ;
    USE SIGNAL ;
    PORT
      LAYER M5 ;
        RECT  11.952 55.968 11.976 56.16 ;
    END
  END o[101]
  PIN o[102]
    DIRECTION OUTPUT ;
    USE SIGNAL ;
    PORT
      LAYER M3 ;
        RECT  12.06 56.016 12.078 56.16 ;
    END
  END o[102]
  PIN o[103]
    DIRECTION OUTPUT ;
    USE SIGNAL ;
    PORT
      LAYER M5 ;
        RECT  12.144 55.968 12.168 56.16 ;
    END
  END o[103]
  PIN o[104]
    DIRECTION OUTPUT ;
    USE SIGNAL ;
    PORT
      LAYER M3 ;
        RECT  12.24 56.016 12.258 56.16 ;
    END
  END o[104]
  PIN o[105]
    DIRECTION OUTPUT ;
    USE SIGNAL ;
    PORT
      LAYER M5 ;
        RECT  12.336 55.968 12.36 56.16 ;
    END
  END o[105]
  PIN o[106]
    DIRECTION OUTPUT ;
    USE SIGNAL ;
    PORT
      LAYER M3 ;
        RECT  12.456 56.016 12.474 56.16 ;
    END
  END o[106]
  PIN o[107]
    DIRECTION OUTPUT ;
    USE SIGNAL ;
    PORT
      LAYER M5 ;
        RECT  12.528 55.968 12.552 56.16 ;
    END
  END o[107]
  PIN o[108]
    DIRECTION OUTPUT ;
    USE SIGNAL ;
    PORT
      LAYER M3 ;
        RECT  12.636 56.016 12.654 56.16 ;
    END
  END o[108]
  PIN o[109]
    DIRECTION OUTPUT ;
    USE SIGNAL ;
    PORT
      LAYER M5 ;
        RECT  12.72 55.968 12.744 56.16 ;
    END
  END o[109]
  PIN o[10]
    DIRECTION OUTPUT ;
    USE SIGNAL ;
    PORT
      LAYER M3 ;
        RECT  3.168 56.016 3.186 56.16 ;
    END
  END o[10]
  PIN o[110]
    DIRECTION OUTPUT ;
    USE SIGNAL ;
    PORT
      LAYER M3 ;
        RECT  12.852 56.016 12.87 56.16 ;
    END
  END o[110]
  PIN o[111]
    DIRECTION OUTPUT ;
    USE SIGNAL ;
    PORT
      LAYER M5 ;
        RECT  12.912 55.968 12.936 56.16 ;
    END
  END o[111]
  PIN o[112]
    DIRECTION OUTPUT ;
    USE SIGNAL ;
    PORT
      LAYER M3 ;
        RECT  13.032 56.016 13.05 56.16 ;
    END
  END o[112]
  PIN o[113]
    DIRECTION OUTPUT ;
    USE SIGNAL ;
    PORT
      LAYER M5 ;
        RECT  13.104 55.968 13.128 56.16 ;
    END
  END o[113]
  PIN o[114]
    DIRECTION OUTPUT ;
    USE SIGNAL ;
    PORT
      LAYER M3 ;
        RECT  13.212 56.016 13.23 56.16 ;
    END
  END o[114]
  PIN o[115]
    DIRECTION OUTPUT ;
    USE SIGNAL ;
    PORT
      LAYER M5 ;
        RECT  13.296 55.968 13.32 56.16 ;
    END
  END o[115]
  PIN o[116]
    DIRECTION OUTPUT ;
    USE SIGNAL ;
    PORT
      LAYER M3 ;
        RECT  13.428 56.016 13.446 56.16 ;
    END
  END o[116]
  PIN o[117]
    DIRECTION OUTPUT ;
    USE SIGNAL ;
    PORT
      LAYER M5 ;
        RECT  13.536 55.968 13.56 56.16 ;
    END
  END o[117]
  PIN o[118]
    DIRECTION OUTPUT ;
    USE SIGNAL ;
    PORT
      LAYER M3 ;
        RECT  13.608 56.016 13.626 56.16 ;
    END
  END o[118]
  PIN o[119]
    DIRECTION OUTPUT ;
    USE SIGNAL ;
    PORT
      LAYER M5 ;
        RECT  13.728 55.968 13.752 56.16 ;
    END
  END o[119]
  PIN o[11]
    DIRECTION OUTPUT ;
    USE SIGNAL ;
    PORT
      LAYER M5 ;
        RECT  3.264 55.968 3.288 56.16 ;
    END
  END o[11]
  PIN o[120]
    DIRECTION OUTPUT ;
    USE SIGNAL ;
    PORT
      LAYER M3 ;
        RECT  13.788 56.016 13.806 56.16 ;
    END
  END o[120]
  PIN o[121]
    DIRECTION OUTPUT ;
    USE SIGNAL ;
    PORT
      LAYER M5 ;
        RECT  13.92 55.968 13.944 56.16 ;
    END
  END o[121]
  PIN o[122]
    DIRECTION OUTPUT ;
    USE SIGNAL ;
    PORT
      LAYER M3 ;
        RECT  14.004 56.016 14.022 56.16 ;
    END
  END o[122]
  PIN o[123]
    DIRECTION OUTPUT ;
    USE SIGNAL ;
    PORT
      LAYER M5 ;
        RECT  14.112 55.968 14.136 56.16 ;
    END
  END o[123]
  PIN o[124]
    DIRECTION OUTPUT ;
    USE SIGNAL ;
    PORT
      LAYER M3 ;
        RECT  14.184 56.016 14.202 56.16 ;
    END
  END o[124]
  PIN o[125]
    DIRECTION OUTPUT ;
    USE SIGNAL ;
    PORT
      LAYER M5 ;
        RECT  14.304 55.968 14.328 56.16 ;
    END
  END o[125]
  PIN o[126]
    DIRECTION OUTPUT ;
    USE SIGNAL ;
    PORT
      LAYER M3 ;
        RECT  14.4 56.016 14.418 56.16 ;
    END
  END o[126]
  PIN o[127]
    DIRECTION OUTPUT ;
    USE SIGNAL ;
    PORT
      LAYER M5 ;
        RECT  14.496 55.968 14.52 56.16 ;
    END
  END o[127]
  PIN o[128]
    DIRECTION OUTPUT ;
    USE SIGNAL ;
    PORT
      LAYER M3 ;
        RECT  14.58 56.016 14.598 56.16 ;
    END
  END o[128]
  PIN o[129]
    DIRECTION OUTPUT ;
    USE SIGNAL ;
    PORT
      LAYER M5 ;
        RECT  14.688 55.968 14.712 56.16 ;
    END
  END o[129]
  PIN o[12]
    DIRECTION OUTPUT ;
    USE SIGNAL ;
    PORT
      LAYER M3 ;
        RECT  3.348 56.016 3.366 56.16 ;
    END
  END o[12]
  PIN o[130]
    DIRECTION OUTPUT ;
    USE SIGNAL ;
    PORT
      LAYER M3 ;
        RECT  14.76 56.016 14.778 56.16 ;
    END
  END o[130]
  PIN o[131]
    DIRECTION OUTPUT ;
    USE SIGNAL ;
    PORT
      LAYER M5 ;
        RECT  14.88 55.968 14.904 56.16 ;
    END
  END o[131]
  PIN o[132]
    DIRECTION OUTPUT ;
    USE SIGNAL ;
    PORT
      LAYER M3 ;
        RECT  14.976 56.016 14.994 56.16 ;
    END
  END o[132]
  PIN o[133]
    DIRECTION OUTPUT ;
    USE SIGNAL ;
    PORT
      LAYER M5 ;
        RECT  15.072 55.968 15.096 56.16 ;
    END
  END o[133]
  PIN o[134]
    DIRECTION OUTPUT ;
    USE SIGNAL ;
    PORT
      LAYER M3 ;
        RECT  15.156 56.016 15.174 56.16 ;
    END
  END o[134]
  PIN o[135]
    DIRECTION OUTPUT ;
    USE SIGNAL ;
    PORT
      LAYER M5 ;
        RECT  15.264 55.968 15.288 56.16 ;
    END
  END o[135]
  PIN o[136]
    DIRECTION OUTPUT ;
    USE SIGNAL ;
    PORT
      LAYER M3 ;
        RECT  15.336 56.016 15.354 56.16 ;
    END
  END o[136]
  PIN o[137]
    DIRECTION OUTPUT ;
    USE SIGNAL ;
    PORT
      LAYER M5 ;
        RECT  15.456 55.968 15.48 56.16 ;
    END
  END o[137]
  PIN o[138]
    DIRECTION OUTPUT ;
    USE SIGNAL ;
    PORT
      LAYER M3 ;
        RECT  15.552 56.016 15.57 56.16 ;
    END
  END o[138]
  PIN o[139]
    DIRECTION OUTPUT ;
    USE SIGNAL ;
    PORT
      LAYER M5 ;
        RECT  15.648 55.968 15.672 56.16 ;
    END
  END o[139]
  PIN o[13]
    DIRECTION OUTPUT ;
    USE SIGNAL ;
    PORT
      LAYER M5 ;
        RECT  3.456 55.968 3.48 56.16 ;
    END
  END o[13]
  PIN o[140]
    DIRECTION OUTPUT ;
    USE SIGNAL ;
    PORT
      LAYER M3 ;
        RECT  15.732 56.016 15.75 56.16 ;
    END
  END o[140]
  PIN o[141]
    DIRECTION OUTPUT ;
    USE SIGNAL ;
    PORT
      LAYER M5 ;
        RECT  15.84 55.968 15.864 56.16 ;
    END
  END o[141]
  PIN o[142]
    DIRECTION OUTPUT ;
    USE SIGNAL ;
    PORT
      LAYER M3 ;
        RECT  15.948 56.016 15.966 56.16 ;
    END
  END o[142]
  PIN o[143]
    DIRECTION OUTPUT ;
    USE SIGNAL ;
    PORT
      LAYER M5 ;
        RECT  16.032 55.968 16.056 56.16 ;
    END
  END o[143]
  PIN o[144]
    DIRECTION OUTPUT ;
    USE SIGNAL ;
    PORT
      LAYER M3 ;
        RECT  16.128 56.016 16.146 56.16 ;
    END
  END o[144]
  PIN o[145]
    DIRECTION OUTPUT ;
    USE SIGNAL ;
    PORT
      LAYER M5 ;
        RECT  16.224 55.968 16.248 56.16 ;
    END
  END o[145]
  PIN o[146]
    DIRECTION OUTPUT ;
    USE SIGNAL ;
    PORT
      LAYER M3 ;
        RECT  16.308 56.016 16.326 56.16 ;
    END
  END o[146]
  PIN o[147]
    DIRECTION OUTPUT ;
    USE SIGNAL ;
    PORT
      LAYER M5 ;
        RECT  16.416 55.968 16.44 56.16 ;
    END
  END o[147]
  PIN o[148]
    DIRECTION OUTPUT ;
    USE SIGNAL ;
    PORT
      LAYER M3 ;
        RECT  16.524 56.016 16.542 56.16 ;
    END
  END o[148]
  PIN o[149]
    DIRECTION OUTPUT ;
    USE SIGNAL ;
    PORT
      LAYER M5 ;
        RECT  16.608 55.968 16.632 56.16 ;
    END
  END o[149]
  PIN o[14]
    DIRECTION OUTPUT ;
    USE SIGNAL ;
    PORT
      LAYER M3 ;
        RECT  3.564 56.016 3.582 56.16 ;
    END
  END o[14]
  PIN o[150]
    DIRECTION OUTPUT ;
    USE SIGNAL ;
    PORT
      LAYER M3 ;
        RECT  16.704 56.016 16.722 56.16 ;
    END
  END o[150]
  PIN o[151]
    DIRECTION OUTPUT ;
    USE SIGNAL ;
    PORT
      LAYER M5 ;
        RECT  16.8 55.968 16.824 56.16 ;
    END
  END o[151]
  PIN o[152]
    DIRECTION OUTPUT ;
    USE SIGNAL ;
    PORT
      LAYER M3 ;
        RECT  16.884 56.016 16.902 56.16 ;
    END
  END o[152]
  PIN o[153]
    DIRECTION OUTPUT ;
    USE SIGNAL ;
    PORT
      LAYER M5 ;
        RECT  16.992 55.968 17.016 56.16 ;
    END
  END o[153]
  PIN o[154]
    DIRECTION OUTPUT ;
    USE SIGNAL ;
    PORT
      LAYER M3 ;
        RECT  17.1 56.016 17.118 56.16 ;
    END
  END o[154]
  PIN o[155]
    DIRECTION OUTPUT ;
    USE SIGNAL ;
    PORT
      LAYER M5 ;
        RECT  17.184 55.968 17.208 56.16 ;
    END
  END o[155]
  PIN o[156]
    DIRECTION OUTPUT ;
    USE SIGNAL ;
    PORT
      LAYER M3 ;
        RECT  17.28 56.016 17.298 56.16 ;
    END
  END o[156]
  PIN o[157]
    DIRECTION OUTPUT ;
    USE SIGNAL ;
    PORT
      LAYER M5 ;
        RECT  17.376 55.968 17.4 56.16 ;
    END
  END o[157]
  PIN o[158]
    DIRECTION OUTPUT ;
    USE SIGNAL ;
    PORT
      LAYER M3 ;
        RECT  17.496 56.016 17.514 56.16 ;
    END
  END o[158]
  PIN o[159]
    DIRECTION OUTPUT ;
    USE SIGNAL ;
    PORT
      LAYER M5 ;
        RECT  17.568 55.968 17.592 56.16 ;
    END
  END o[159]
  PIN o[15]
    DIRECTION OUTPUT ;
    USE SIGNAL ;
    PORT
      LAYER M5 ;
        RECT  3.648 55.968 3.672 56.16 ;
    END
  END o[15]
  PIN o[160]
    DIRECTION OUTPUT ;
    USE SIGNAL ;
    PORT
      LAYER M3 ;
        RECT  17.676 56.016 17.694 56.16 ;
    END
  END o[160]
  PIN o[161]
    DIRECTION OUTPUT ;
    USE SIGNAL ;
    PORT
      LAYER M5 ;
        RECT  17.76 55.968 17.784 56.16 ;
    END
  END o[161]
  PIN o[162]
    DIRECTION OUTPUT ;
    USE SIGNAL ;
    PORT
      LAYER M3 ;
        RECT  17.856 56.016 17.874 56.16 ;
    END
  END o[162]
  PIN o[163]
    DIRECTION OUTPUT ;
    USE SIGNAL ;
    PORT
      LAYER M5 ;
        RECT  17.952 55.968 17.976 56.16 ;
    END
  END o[163]
  PIN o[164]
    DIRECTION OUTPUT ;
    USE SIGNAL ;
    PORT
      LAYER M3 ;
        RECT  18.072 56.016 18.09 56.16 ;
    END
  END o[164]
  PIN o[165]
    DIRECTION OUTPUT ;
    USE SIGNAL ;
    PORT
      LAYER M5 ;
        RECT  18.144 55.968 18.168 56.16 ;
    END
  END o[165]
  PIN o[166]
    DIRECTION OUTPUT ;
    USE SIGNAL ;
    PORT
      LAYER M3 ;
        RECT  18.252 56.016 18.27 56.16 ;
    END
  END o[166]
  PIN o[167]
    DIRECTION OUTPUT ;
    USE SIGNAL ;
    PORT
      LAYER M5 ;
        RECT  18.336 55.968 18.36 56.16 ;
    END
  END o[167]
  PIN o[168]
    DIRECTION OUTPUT ;
    USE SIGNAL ;
    PORT
      LAYER M3 ;
        RECT  18.432 56.016 18.45 56.16 ;
    END
  END o[168]
  PIN o[169]
    DIRECTION OUTPUT ;
    USE SIGNAL ;
    PORT
      LAYER M5 ;
        RECT  18.528 55.968 18.552 56.16 ;
    END
  END o[169]
  PIN o[16]
    DIRECTION OUTPUT ;
    USE SIGNAL ;
    PORT
      LAYER M3 ;
        RECT  3.744 56.016 3.762 56.16 ;
    END
  END o[16]
  PIN o[170]
    DIRECTION OUTPUT ;
    USE SIGNAL ;
    PORT
      LAYER M3 ;
        RECT  18.648 56.016 18.666 56.16 ;
    END
  END o[170]
  PIN o[171]
    DIRECTION OUTPUT ;
    USE SIGNAL ;
    PORT
      LAYER M5 ;
        RECT  18.72 55.968 18.744 56.16 ;
    END
  END o[171]
  PIN o[172]
    DIRECTION OUTPUT ;
    USE SIGNAL ;
    PORT
      LAYER M3 ;
        RECT  18.828 56.016 18.846 56.16 ;
    END
  END o[172]
  PIN o[173]
    DIRECTION OUTPUT ;
    USE SIGNAL ;
    PORT
      LAYER M5 ;
        RECT  18.912 55.968 18.936 56.16 ;
    END
  END o[173]
  PIN o[174]
    DIRECTION OUTPUT ;
    USE SIGNAL ;
    PORT
      LAYER M3 ;
        RECT  19.044 56.016 19.062 56.16 ;
    END
  END o[174]
  PIN o[175]
    DIRECTION OUTPUT ;
    USE SIGNAL ;
    PORT
      LAYER M5 ;
        RECT  19.104 55.968 19.128 56.16 ;
    END
  END o[175]
  PIN o[176]
    DIRECTION OUTPUT ;
    USE SIGNAL ;
    PORT
      LAYER M3 ;
        RECT  19.224 56.016 19.242 56.16 ;
    END
  END o[176]
  PIN o[177]
    DIRECTION OUTPUT ;
    USE SIGNAL ;
    PORT
      LAYER M5 ;
        RECT  19.296 55.968 19.32 56.16 ;
    END
  END o[177]
  PIN o[178]
    DIRECTION OUTPUT ;
    USE SIGNAL ;
    PORT
      LAYER M3 ;
        RECT  19.404 56.016 19.422 56.16 ;
    END
  END o[178]
  PIN o[179]
    DIRECTION OUTPUT ;
    USE SIGNAL ;
    PORT
      LAYER M5 ;
        RECT  19.488 55.968 19.512 56.16 ;
    END
  END o[179]
  PIN o[17]
    DIRECTION OUTPUT ;
    USE SIGNAL ;
    PORT
      LAYER M5 ;
        RECT  3.84 55.968 3.864 56.16 ;
    END
  END o[17]
  PIN o[180]
    DIRECTION OUTPUT ;
    USE SIGNAL ;
    PORT
      LAYER M3 ;
        RECT  19.62 56.016 19.638 56.16 ;
    END
  END o[180]
  PIN o[181]
    DIRECTION OUTPUT ;
    USE SIGNAL ;
    PORT
      LAYER M5 ;
        RECT  19.68 55.968 19.704 56.16 ;
    END
  END o[181]
  PIN o[182]
    DIRECTION OUTPUT ;
    USE SIGNAL ;
    PORT
      LAYER M3 ;
        RECT  19.8 56.016 19.818 56.16 ;
    END
  END o[182]
  PIN o[183]
    DIRECTION OUTPUT ;
    USE SIGNAL ;
    PORT
      LAYER M5 ;
        RECT  19.872 55.968 19.896 56.16 ;
    END
  END o[183]
  PIN o[184]
    DIRECTION OUTPUT ;
    USE SIGNAL ;
    PORT
      LAYER M3 ;
        RECT  19.98 56.016 19.998 56.16 ;
    END
  END o[184]
  PIN o[185]
    DIRECTION OUTPUT ;
    USE SIGNAL ;
    PORT
      LAYER M5 ;
        RECT  20.112 55.968 20.136 56.16 ;
    END
  END o[185]
  PIN o[186]
    DIRECTION OUTPUT ;
    USE SIGNAL ;
    PORT
      LAYER M3 ;
        RECT  20.196 56.016 20.214 56.16 ;
    END
  END o[186]
  PIN o[187]
    DIRECTION OUTPUT ;
    USE SIGNAL ;
    PORT
      LAYER M5 ;
        RECT  20.304 55.968 20.328 56.16 ;
    END
  END o[187]
  PIN o[188]
    DIRECTION OUTPUT ;
    USE SIGNAL ;
    PORT
      LAYER M3 ;
        RECT  20.376 56.016 20.394 56.16 ;
    END
  END o[188]
  PIN o[189]
    DIRECTION OUTPUT ;
    USE SIGNAL ;
    PORT
      LAYER M5 ;
        RECT  20.496 55.968 20.52 56.16 ;
    END
  END o[189]
  PIN o[18]
    DIRECTION OUTPUT ;
    USE SIGNAL ;
    PORT
      LAYER M3 ;
        RECT  3.924 56.016 3.942 56.16 ;
    END
  END o[18]
  PIN o[190]
    DIRECTION OUTPUT ;
    USE SIGNAL ;
    PORT
      LAYER M3 ;
        RECT  20.592 56.016 20.61 56.16 ;
    END
  END o[190]
  PIN o[191]
    DIRECTION OUTPUT ;
    USE SIGNAL ;
    PORT
      LAYER M5 ;
        RECT  20.688 55.968 20.712 56.16 ;
    END
  END o[191]
  PIN o[192]
    DIRECTION OUTPUT ;
    USE SIGNAL ;
    PORT
      LAYER M3 ;
        RECT  20.772 56.016 20.79 56.16 ;
    END
  END o[192]
  PIN o[193]
    DIRECTION OUTPUT ;
    USE SIGNAL ;
    PORT
      LAYER M5 ;
        RECT  20.88 55.968 20.904 56.16 ;
    END
  END o[193]
  PIN o[194]
    DIRECTION OUTPUT ;
    USE SIGNAL ;
    PORT
      LAYER M3 ;
        RECT  20.952 56.016 20.97 56.16 ;
    END
  END o[194]
  PIN o[195]
    DIRECTION OUTPUT ;
    USE SIGNAL ;
    PORT
      LAYER M5 ;
        RECT  21.072 55.968 21.096 56.16 ;
    END
  END o[195]
  PIN o[196]
    DIRECTION OUTPUT ;
    USE SIGNAL ;
    PORT
      LAYER M3 ;
        RECT  21.168 56.016 21.186 56.16 ;
    END
  END o[196]
  PIN o[197]
    DIRECTION OUTPUT ;
    USE SIGNAL ;
    PORT
      LAYER M5 ;
        RECT  21.264 55.968 21.288 56.16 ;
    END
  END o[197]
  PIN o[198]
    DIRECTION OUTPUT ;
    USE SIGNAL ;
    PORT
      LAYER M3 ;
        RECT  21.348 56.016 21.366 56.16 ;
    END
  END o[198]
  PIN o[199]
    DIRECTION OUTPUT ;
    USE SIGNAL ;
    PORT
      LAYER M5 ;
        RECT  21.456 55.968 21.48 56.16 ;
    END
  END o[199]
  PIN o[19]
    DIRECTION OUTPUT ;
    USE SIGNAL ;
    PORT
      LAYER M5 ;
        RECT  4.032 55.968 4.056 56.16 ;
    END
  END o[19]
  PIN o[1]
    DIRECTION OUTPUT ;
    USE SIGNAL ;
    PORT
      LAYER M5 ;
        RECT  2.304 55.968 2.328 56.16 ;
    END
  END o[1]
  PIN o[200]
    DIRECTION OUTPUT ;
    USE SIGNAL ;
    PORT
      LAYER M3 ;
        RECT  21.528 56.016 21.546 56.16 ;
    END
  END o[200]
  PIN o[201]
    DIRECTION OUTPUT ;
    USE SIGNAL ;
    PORT
      LAYER M5 ;
        RECT  21.648 55.968 21.672 56.16 ;
    END
  END o[201]
  PIN o[202]
    DIRECTION OUTPUT ;
    USE SIGNAL ;
    PORT
      LAYER M3 ;
        RECT  21.744 56.016 21.762 56.16 ;
    END
  END o[202]
  PIN o[203]
    DIRECTION OUTPUT ;
    USE SIGNAL ;
    PORT
      LAYER M5 ;
        RECT  21.84 55.968 21.864 56.16 ;
    END
  END o[203]
  PIN o[204]
    DIRECTION OUTPUT ;
    USE SIGNAL ;
    PORT
      LAYER M3 ;
        RECT  21.924 56.016 21.942 56.16 ;
    END
  END o[204]
  PIN o[205]
    DIRECTION OUTPUT ;
    USE SIGNAL ;
    PORT
      LAYER M5 ;
        RECT  22.032 55.968 22.056 56.16 ;
    END
  END o[205]
  PIN o[206]
    DIRECTION OUTPUT ;
    USE SIGNAL ;
    PORT
      LAYER M3 ;
        RECT  22.14 56.016 22.158 56.16 ;
    END
  END o[206]
  PIN o[207]
    DIRECTION OUTPUT ;
    USE SIGNAL ;
    PORT
      LAYER M5 ;
        RECT  22.224 55.968 22.248 56.16 ;
    END
  END o[207]
  PIN o[208]
    DIRECTION OUTPUT ;
    USE SIGNAL ;
    PORT
      LAYER M3 ;
        RECT  22.32 56.016 22.338 56.16 ;
    END
  END o[208]
  PIN o[209]
    DIRECTION OUTPUT ;
    USE SIGNAL ;
    PORT
      LAYER M5 ;
        RECT  22.416 55.968 22.44 56.16 ;
    END
  END o[209]
  PIN o[20]
    DIRECTION OUTPUT ;
    USE SIGNAL ;
    PORT
      LAYER M3 ;
        RECT  4.14 56.016 4.158 56.16 ;
    END
  END o[20]
  PIN o[210]
    DIRECTION OUTPUT ;
    USE SIGNAL ;
    PORT
      LAYER M3 ;
        RECT  22.5 56.016 22.518 56.16 ;
    END
  END o[210]
  PIN o[211]
    DIRECTION OUTPUT ;
    USE SIGNAL ;
    PORT
      LAYER M5 ;
        RECT  22.608 55.968 22.632 56.16 ;
    END
  END o[211]
  PIN o[212]
    DIRECTION OUTPUT ;
    USE SIGNAL ;
    PORT
      LAYER M3 ;
        RECT  22.716 56.016 22.734 56.16 ;
    END
  END o[212]
  PIN o[213]
    DIRECTION OUTPUT ;
    USE SIGNAL ;
    PORT
      LAYER M5 ;
        RECT  22.8 55.968 22.824 56.16 ;
    END
  END o[213]
  PIN o[214]
    DIRECTION OUTPUT ;
    USE SIGNAL ;
    PORT
      LAYER M3 ;
        RECT  22.896 56.016 22.914 56.16 ;
    END
  END o[214]
  PIN o[215]
    DIRECTION OUTPUT ;
    USE SIGNAL ;
    PORT
      LAYER M5 ;
        RECT  22.992 55.968 23.016 56.16 ;
    END
  END o[215]
  PIN o[216]
    DIRECTION OUTPUT ;
    USE SIGNAL ;
    PORT
      LAYER M3 ;
        RECT  23.076 56.016 23.094 56.16 ;
    END
  END o[216]
  PIN o[217]
    DIRECTION OUTPUT ;
    USE SIGNAL ;
    PORT
      LAYER M5 ;
        RECT  23.184 55.968 23.208 56.16 ;
    END
  END o[217]
  PIN o[218]
    DIRECTION OUTPUT ;
    USE SIGNAL ;
    PORT
      LAYER M3 ;
        RECT  23.292 56.016 23.31 56.16 ;
    END
  END o[218]
  PIN o[219]
    DIRECTION OUTPUT ;
    USE SIGNAL ;
    PORT
      LAYER M5 ;
        RECT  23.376 55.968 23.4 56.16 ;
    END
  END o[219]
  PIN o[21]
    DIRECTION OUTPUT ;
    USE SIGNAL ;
    PORT
      LAYER M5 ;
        RECT  4.224 55.968 4.248 56.16 ;
    END
  END o[21]
  PIN o[220]
    DIRECTION OUTPUT ;
    USE SIGNAL ;
    PORT
      LAYER M3 ;
        RECT  23.472 56.016 23.49 56.16 ;
    END
  END o[220]
  PIN o[221]
    DIRECTION OUTPUT ;
    USE SIGNAL ;
    PORT
      LAYER M5 ;
        RECT  23.568 55.968 23.592 56.16 ;
    END
  END o[221]
  PIN o[222]
    DIRECTION OUTPUT ;
    USE SIGNAL ;
    PORT
      LAYER M3 ;
        RECT  23.688 56.016 23.706 56.16 ;
    END
  END o[222]
  PIN o[223]
    DIRECTION OUTPUT ;
    USE SIGNAL ;
    PORT
      LAYER M5 ;
        RECT  23.76 55.968 23.784 56.16 ;
    END
  END o[223]
  PIN o[224]
    DIRECTION OUTPUT ;
    USE SIGNAL ;
    PORT
      LAYER M3 ;
        RECT  23.868 56.016 23.886 56.16 ;
    END
  END o[224]
  PIN o[225]
    DIRECTION OUTPUT ;
    USE SIGNAL ;
    PORT
      LAYER M5 ;
        RECT  23.952 55.968 23.976 56.16 ;
    END
  END o[225]
  PIN o[226]
    DIRECTION OUTPUT ;
    USE SIGNAL ;
    PORT
      LAYER M3 ;
        RECT  24.048 56.016 24.066 56.16 ;
    END
  END o[226]
  PIN o[227]
    DIRECTION OUTPUT ;
    USE SIGNAL ;
    PORT
      LAYER M5 ;
        RECT  24.144 55.968 24.168 56.16 ;
    END
  END o[227]
  PIN o[228]
    DIRECTION OUTPUT ;
    USE SIGNAL ;
    PORT
      LAYER M3 ;
        RECT  24.264 56.016 24.282 56.16 ;
    END
  END o[228]
  PIN o[229]
    DIRECTION OUTPUT ;
    USE SIGNAL ;
    PORT
      LAYER M5 ;
        RECT  24.336 55.968 24.36 56.16 ;
    END
  END o[229]
  PIN o[22]
    DIRECTION OUTPUT ;
    USE SIGNAL ;
    PORT
      LAYER M3 ;
        RECT  4.32 56.016 4.338 56.16 ;
    END
  END o[22]
  PIN o[230]
    DIRECTION OUTPUT ;
    USE SIGNAL ;
    PORT
      LAYER M3 ;
        RECT  24.444 56.016 24.462 56.16 ;
    END
  END o[230]
  PIN o[231]
    DIRECTION OUTPUT ;
    USE SIGNAL ;
    PORT
      LAYER M5 ;
        RECT  24.528 55.968 24.552 56.16 ;
    END
  END o[231]
  PIN o[232]
    DIRECTION OUTPUT ;
    USE SIGNAL ;
    PORT
      LAYER M3 ;
        RECT  24.624 56.016 24.642 56.16 ;
    END
  END o[232]
  PIN o[233]
    DIRECTION OUTPUT ;
    USE SIGNAL ;
    PORT
      LAYER M5 ;
        RECT  24.72 55.968 24.744 56.16 ;
    END
  END o[233]
  PIN o[234]
    DIRECTION OUTPUT ;
    USE SIGNAL ;
    PORT
      LAYER M3 ;
        RECT  24.84 56.016 24.858 56.16 ;
    END
  END o[234]
  PIN o[235]
    DIRECTION OUTPUT ;
    USE SIGNAL ;
    PORT
      LAYER M5 ;
        RECT  24.912 55.968 24.936 56.16 ;
    END
  END o[235]
  PIN o[236]
    DIRECTION OUTPUT ;
    USE SIGNAL ;
    PORT
      LAYER M3 ;
        RECT  25.02 56.016 25.038 56.16 ;
    END
  END o[236]
  PIN o[237]
    DIRECTION OUTPUT ;
    USE SIGNAL ;
    PORT
      LAYER M5 ;
        RECT  25.104 55.968 25.128 56.16 ;
    END
  END o[237]
  PIN o[238]
    DIRECTION OUTPUT ;
    USE SIGNAL ;
    PORT
      LAYER M3 ;
        RECT  25.2 56.016 25.218 56.16 ;
    END
  END o[238]
  PIN o[239]
    DIRECTION OUTPUT ;
    USE SIGNAL ;
    PORT
      LAYER M5 ;
        RECT  25.296 55.968 25.32 56.16 ;
    END
  END o[239]
  PIN o[23]
    DIRECTION OUTPUT ;
    USE SIGNAL ;
    PORT
      LAYER M5 ;
        RECT  4.416 55.968 4.44 56.16 ;
    END
  END o[23]
  PIN o[240]
    DIRECTION OUTPUT ;
    USE SIGNAL ;
    PORT
      LAYER M3 ;
        RECT  25.416 56.016 25.434 56.16 ;
    END
  END o[240]
  PIN o[241]
    DIRECTION OUTPUT ;
    USE SIGNAL ;
    PORT
      LAYER M5 ;
        RECT  25.488 55.968 25.512 56.16 ;
    END
  END o[241]
  PIN o[242]
    DIRECTION OUTPUT ;
    USE SIGNAL ;
    PORT
      LAYER M3 ;
        RECT  25.596 56.016 25.614 56.16 ;
    END
  END o[242]
  PIN o[243]
    DIRECTION OUTPUT ;
    USE SIGNAL ;
    PORT
      LAYER M5 ;
        RECT  25.68 55.968 25.704 56.16 ;
    END
  END o[243]
  PIN o[244]
    DIRECTION OUTPUT ;
    USE SIGNAL ;
    PORT
      LAYER M3 ;
        RECT  25.812 56.016 25.83 56.16 ;
    END
  END o[244]
  PIN o[245]
    DIRECTION OUTPUT ;
    USE SIGNAL ;
    PORT
      LAYER M5 ;
        RECT  25.872 55.968 25.896 56.16 ;
    END
  END o[245]
  PIN o[246]
    DIRECTION OUTPUT ;
    USE SIGNAL ;
    PORT
      LAYER M3 ;
        RECT  25.992 56.016 26.01 56.16 ;
    END
  END o[246]
  PIN o[247]
    DIRECTION OUTPUT ;
    USE SIGNAL ;
    PORT
      LAYER M5 ;
        RECT  26.064 55.968 26.088 56.16 ;
    END
  END o[247]
  PIN o[248]
    DIRECTION OUTPUT ;
    USE SIGNAL ;
    PORT
      LAYER M3 ;
        RECT  26.172 56.016 26.19 56.16 ;
    END
  END o[248]
  PIN o[249]
    DIRECTION OUTPUT ;
    USE SIGNAL ;
    PORT
      LAYER M5 ;
        RECT  26.256 55.968 26.28 56.16 ;
    END
  END o[249]
  PIN o[24]
    DIRECTION OUTPUT ;
    USE SIGNAL ;
    PORT
      LAYER M3 ;
        RECT  4.536 56.016 4.554 56.16 ;
    END
  END o[24]
  PIN o[250]
    DIRECTION OUTPUT ;
    USE SIGNAL ;
    PORT
      LAYER M3 ;
        RECT  26.388 56.016 26.406 56.16 ;
    END
  END o[250]
  PIN o[251]
    DIRECTION OUTPUT ;
    USE SIGNAL ;
    PORT
      LAYER M5 ;
        RECT  26.496 55.968 26.52 56.16 ;
    END
  END o[251]
  PIN o[252]
    DIRECTION OUTPUT ;
    USE SIGNAL ;
    PORT
      LAYER M3 ;
        RECT  26.568 56.016 26.586 56.16 ;
    END
  END o[252]
  PIN o[253]
    DIRECTION OUTPUT ;
    USE SIGNAL ;
    PORT
      LAYER M5 ;
        RECT  26.688 55.968 26.712 56.16 ;
    END
  END o[253]
  PIN o[254]
    DIRECTION OUTPUT ;
    USE SIGNAL ;
    PORT
      LAYER M3 ;
        RECT  26.748 56.016 26.766 56.16 ;
    END
  END o[254]
  PIN o[255]
    DIRECTION OUTPUT ;
    USE SIGNAL ;
    PORT
      LAYER M5 ;
        RECT  26.88 55.968 26.904 56.16 ;
    END
  END o[255]
  PIN o[256]
    DIRECTION OUTPUT ;
    USE SIGNAL ;
    PORT
      LAYER M3 ;
        RECT  26.964 56.016 26.982 56.16 ;
    END
  END o[256]
  PIN o[257]
    DIRECTION OUTPUT ;
    USE SIGNAL ;
    PORT
      LAYER M5 ;
        RECT  27.072 55.968 27.096 56.16 ;
    END
  END o[257]
  PIN o[258]
    DIRECTION OUTPUT ;
    USE SIGNAL ;
    PORT
      LAYER M3 ;
        RECT  27.144 56.016 27.162 56.16 ;
    END
  END o[258]
  PIN o[259]
    DIRECTION OUTPUT ;
    USE SIGNAL ;
    PORT
      LAYER M5 ;
        RECT  27.264 55.968 27.288 56.16 ;
    END
  END o[259]
  PIN o[25]
    DIRECTION OUTPUT ;
    USE SIGNAL ;
    PORT
      LAYER M5 ;
        RECT  4.608 55.968 4.632 56.16 ;
    END
  END o[25]
  PIN o[260]
    DIRECTION OUTPUT ;
    USE SIGNAL ;
    PORT
      LAYER M3 ;
        RECT  27.36 56.016 27.378 56.16 ;
    END
  END o[260]
  PIN o[261]
    DIRECTION OUTPUT ;
    USE SIGNAL ;
    PORT
      LAYER M5 ;
        RECT  27.456 55.968 27.48 56.16 ;
    END
  END o[261]
  PIN o[262]
    DIRECTION OUTPUT ;
    USE SIGNAL ;
    PORT
      LAYER M3 ;
        RECT  27.54 56.016 27.558 56.16 ;
    END
  END o[262]
  PIN o[263]
    DIRECTION OUTPUT ;
    USE SIGNAL ;
    PORT
      LAYER M5 ;
        RECT  27.648 55.968 27.672 56.16 ;
    END
  END o[263]
  PIN o[264]
    DIRECTION OUTPUT ;
    USE SIGNAL ;
    PORT
      LAYER M3 ;
        RECT  27.72 56.016 27.738 56.16 ;
    END
  END o[264]
  PIN o[265]
    DIRECTION OUTPUT ;
    USE SIGNAL ;
    PORT
      LAYER M5 ;
        RECT  27.84 55.968 27.864 56.16 ;
    END
  END o[265]
  PIN o[266]
    DIRECTION OUTPUT ;
    USE SIGNAL ;
    PORT
      LAYER M3 ;
        RECT  27.936 56.016 27.954 56.16 ;
    END
  END o[266]
  PIN o[267]
    DIRECTION OUTPUT ;
    USE SIGNAL ;
    PORT
      LAYER M5 ;
        RECT  28.032 55.968 28.056 56.16 ;
    END
  END o[267]
  PIN o[268]
    DIRECTION OUTPUT ;
    USE SIGNAL ;
    PORT
      LAYER M3 ;
        RECT  28.116 56.016 28.134 56.16 ;
    END
  END o[268]
  PIN o[269]
    DIRECTION OUTPUT ;
    USE SIGNAL ;
    PORT
      LAYER M5 ;
        RECT  28.224 55.968 28.248 56.16 ;
    END
  END o[269]
  PIN o[26]
    DIRECTION OUTPUT ;
    USE SIGNAL ;
    PORT
      LAYER M3 ;
        RECT  4.716 56.016 4.734 56.16 ;
    END
  END o[26]
  PIN o[270]
    DIRECTION OUTPUT ;
    USE SIGNAL ;
    PORT
      LAYER M3 ;
        RECT  28.296 56.016 28.314 56.16 ;
    END
  END o[270]
  PIN o[271]
    DIRECTION OUTPUT ;
    USE SIGNAL ;
    PORT
      LAYER M5 ;
        RECT  28.416 55.968 28.44 56.16 ;
    END
  END o[271]
  PIN o[272]
    DIRECTION OUTPUT ;
    USE SIGNAL ;
    PORT
      LAYER M3 ;
        RECT  28.512 56.016 28.53 56.16 ;
    END
  END o[272]
  PIN o[273]
    DIRECTION OUTPUT ;
    USE SIGNAL ;
    PORT
      LAYER M5 ;
        RECT  28.608 55.968 28.632 56.16 ;
    END
  END o[273]
  PIN o[274]
    DIRECTION OUTPUT ;
    USE SIGNAL ;
    PORT
      LAYER M3 ;
        RECT  28.692 56.016 28.71 56.16 ;
    END
  END o[274]
  PIN o[275]
    DIRECTION OUTPUT ;
    USE SIGNAL ;
    PORT
      LAYER M5 ;
        RECT  28.8 55.968 28.824 56.16 ;
    END
  END o[275]
  PIN o[276]
    DIRECTION OUTPUT ;
    USE SIGNAL ;
    PORT
      LAYER M3 ;
        RECT  28.908 56.016 28.926 56.16 ;
    END
  END o[276]
  PIN o[277]
    DIRECTION OUTPUT ;
    USE SIGNAL ;
    PORT
      LAYER M5 ;
        RECT  28.992 55.968 29.016 56.16 ;
    END
  END o[277]
  PIN o[278]
    DIRECTION OUTPUT ;
    USE SIGNAL ;
    PORT
      LAYER M3 ;
        RECT  29.088 56.016 29.106 56.16 ;
    END
  END o[278]
  PIN o[279]
    DIRECTION OUTPUT ;
    USE SIGNAL ;
    PORT
      LAYER M5 ;
        RECT  29.184 55.968 29.208 56.16 ;
    END
  END o[279]
  PIN o[27]
    DIRECTION OUTPUT ;
    USE SIGNAL ;
    PORT
      LAYER M5 ;
        RECT  4.8 55.968 4.824 56.16 ;
    END
  END o[27]
  PIN o[280]
    DIRECTION OUTPUT ;
    USE SIGNAL ;
    PORT
      LAYER M3 ;
        RECT  29.268 56.016 29.286 56.16 ;
    END
  END o[280]
  PIN o[281]
    DIRECTION OUTPUT ;
    USE SIGNAL ;
    PORT
      LAYER M5 ;
        RECT  29.376 55.968 29.4 56.16 ;
    END
  END o[281]
  PIN o[282]
    DIRECTION OUTPUT ;
    USE SIGNAL ;
    PORT
      LAYER M3 ;
        RECT  29.484 56.016 29.502 56.16 ;
    END
  END o[282]
  PIN o[283]
    DIRECTION OUTPUT ;
    USE SIGNAL ;
    PORT
      LAYER M5 ;
        RECT  29.568 55.968 29.592 56.16 ;
    END
  END o[283]
  PIN o[284]
    DIRECTION OUTPUT ;
    USE SIGNAL ;
    PORT
      LAYER M3 ;
        RECT  29.664 56.016 29.682 56.16 ;
    END
  END o[284]
  PIN o[285]
    DIRECTION OUTPUT ;
    USE SIGNAL ;
    PORT
      LAYER M5 ;
        RECT  29.76 55.968 29.784 56.16 ;
    END
  END o[285]
  PIN o[286]
    DIRECTION OUTPUT ;
    USE SIGNAL ;
    PORT
      LAYER M3 ;
        RECT  29.844 56.016 29.862 56.16 ;
    END
  END o[286]
  PIN o[287]
    DIRECTION OUTPUT ;
    USE SIGNAL ;
    PORT
      LAYER M5 ;
        RECT  29.952 55.968 29.976 56.16 ;
    END
  END o[287]
  PIN o[288]
    DIRECTION OUTPUT ;
    USE SIGNAL ;
    PORT
      LAYER M3 ;
        RECT  30.06 56.016 30.078 56.16 ;
    END
  END o[288]
  PIN o[289]
    DIRECTION OUTPUT ;
    USE SIGNAL ;
    PORT
      LAYER M5 ;
        RECT  30.144 55.968 30.168 56.16 ;
    END
  END o[289]
  PIN o[28]
    DIRECTION OUTPUT ;
    USE SIGNAL ;
    PORT
      LAYER M3 ;
        RECT  4.896 56.016 4.914 56.16 ;
    END
  END o[28]
  PIN o[290]
    DIRECTION OUTPUT ;
    USE SIGNAL ;
    PORT
      LAYER M3 ;
        RECT  30.24 56.016 30.258 56.16 ;
    END
  END o[290]
  PIN o[291]
    DIRECTION OUTPUT ;
    USE SIGNAL ;
    PORT
      LAYER M5 ;
        RECT  30.336 55.968 30.36 56.16 ;
    END
  END o[291]
  PIN o[292]
    DIRECTION OUTPUT ;
    USE SIGNAL ;
    PORT
      LAYER M3 ;
        RECT  30.456 56.016 30.474 56.16 ;
    END
  END o[292]
  PIN o[293]
    DIRECTION OUTPUT ;
    USE SIGNAL ;
    PORT
      LAYER M5 ;
        RECT  30.528 55.968 30.552 56.16 ;
    END
  END o[293]
  PIN o[294]
    DIRECTION OUTPUT ;
    USE SIGNAL ;
    PORT
      LAYER M3 ;
        RECT  30.636 56.016 30.654 56.16 ;
    END
  END o[294]
  PIN o[295]
    DIRECTION OUTPUT ;
    USE SIGNAL ;
    PORT
      LAYER M5 ;
        RECT  30.72 55.968 30.744 56.16 ;
    END
  END o[295]
  PIN o[296]
    DIRECTION OUTPUT ;
    USE SIGNAL ;
    PORT
      LAYER M3 ;
        RECT  30.816 56.016 30.834 56.16 ;
    END
  END o[296]
  PIN o[297]
    DIRECTION OUTPUT ;
    USE SIGNAL ;
    PORT
      LAYER M5 ;
        RECT  30.912 55.968 30.936 56.16 ;
    END
  END o[297]
  PIN o[298]
    DIRECTION OUTPUT ;
    USE SIGNAL ;
    PORT
      LAYER M3 ;
        RECT  31.032 56.016 31.05 56.16 ;
    END
  END o[298]
  PIN o[299]
    DIRECTION OUTPUT ;
    USE SIGNAL ;
    PORT
      LAYER M5 ;
        RECT  31.104 55.968 31.128 56.16 ;
    END
  END o[299]
  PIN o[29]
    DIRECTION OUTPUT ;
    USE SIGNAL ;
    PORT
      LAYER M5 ;
        RECT  4.992 55.968 5.016 56.16 ;
    END
  END o[29]
  PIN o[2]
    DIRECTION OUTPUT ;
    USE SIGNAL ;
    PORT
      LAYER M3 ;
        RECT  2.376 56.016 2.394 56.16 ;
    END
  END o[2]
  PIN o[300]
    DIRECTION OUTPUT ;
    USE SIGNAL ;
    PORT
      LAYER M3 ;
        RECT  31.212 56.016 31.23 56.16 ;
    END
  END o[300]
  PIN o[301]
    DIRECTION OUTPUT ;
    USE SIGNAL ;
    PORT
      LAYER M5 ;
        RECT  31.296 55.968 31.32 56.16 ;
    END
  END o[301]
  PIN o[302]
    DIRECTION OUTPUT ;
    USE SIGNAL ;
    PORT
      LAYER M3 ;
        RECT  31.392 56.016 31.41 56.16 ;
    END
  END o[302]
  PIN o[303]
    DIRECTION OUTPUT ;
    USE SIGNAL ;
    PORT
      LAYER M5 ;
        RECT  31.488 55.968 31.512 56.16 ;
    END
  END o[303]
  PIN o[304]
    DIRECTION OUTPUT ;
    USE SIGNAL ;
    PORT
      LAYER M3 ;
        RECT  31.608 56.016 31.626 56.16 ;
    END
  END o[304]
  PIN o[305]
    DIRECTION OUTPUT ;
    USE SIGNAL ;
    PORT
      LAYER M5 ;
        RECT  31.68 55.968 31.704 56.16 ;
    END
  END o[305]
  PIN o[306]
    DIRECTION OUTPUT ;
    USE SIGNAL ;
    PORT
      LAYER M3 ;
        RECT  31.788 56.016 31.806 56.16 ;
    END
  END o[306]
  PIN o[307]
    DIRECTION OUTPUT ;
    USE SIGNAL ;
    PORT
      LAYER M5 ;
        RECT  31.872 55.968 31.896 56.16 ;
    END
  END o[307]
  PIN o[308]
    DIRECTION OUTPUT ;
    USE SIGNAL ;
    PORT
      LAYER M3 ;
        RECT  32.004 56.016 32.022 56.16 ;
    END
  END o[308]
  PIN o[309]
    DIRECTION OUTPUT ;
    USE SIGNAL ;
    PORT
      LAYER M5 ;
        RECT  32.064 55.968 32.088 56.16 ;
    END
  END o[309]
  PIN o[30]
    DIRECTION OUTPUT ;
    USE SIGNAL ;
    PORT
      LAYER M3 ;
        RECT  5.112 56.016 5.13 56.16 ;
    END
  END o[30]
  PIN o[310]
    DIRECTION OUTPUT ;
    USE SIGNAL ;
    PORT
      LAYER M3 ;
        RECT  32.184 56.016 32.202 56.16 ;
    END
  END o[310]
  PIN o[311]
    DIRECTION OUTPUT ;
    USE SIGNAL ;
    PORT
      LAYER M5 ;
        RECT  32.256 55.968 32.28 56.16 ;
    END
  END o[311]
  PIN o[312]
    DIRECTION OUTPUT ;
    USE SIGNAL ;
    PORT
      LAYER M3 ;
        RECT  32.364 56.016 32.382 56.16 ;
    END
  END o[312]
  PIN o[313]
    DIRECTION OUTPUT ;
    USE SIGNAL ;
    PORT
      LAYER M5 ;
        RECT  32.448 55.968 32.472 56.16 ;
    END
  END o[313]
  PIN o[314]
    DIRECTION OUTPUT ;
    USE SIGNAL ;
    PORT
      LAYER M3 ;
        RECT  32.58 56.016 32.598 56.16 ;
    END
  END o[314]
  PIN o[315]
    DIRECTION OUTPUT ;
    USE SIGNAL ;
    PORT
      LAYER M5 ;
        RECT  32.64 55.968 32.664 56.16 ;
    END
  END o[315]
  PIN o[316]
    DIRECTION OUTPUT ;
    USE SIGNAL ;
    PORT
      LAYER M3 ;
        RECT  32.76 56.016 32.778 56.16 ;
    END
  END o[316]
  PIN o[317]
    DIRECTION OUTPUT ;
    USE SIGNAL ;
    PORT
      LAYER M5 ;
        RECT  32.832 55.968 32.856 56.16 ;
    END
  END o[317]
  PIN o[318]
    DIRECTION OUTPUT ;
    USE SIGNAL ;
    PORT
      LAYER M3 ;
        RECT  32.94 56.016 32.958 56.16 ;
    END
  END o[318]
  PIN o[319]
    DIRECTION OUTPUT ;
    USE SIGNAL ;
    PORT
      LAYER M5 ;
        RECT  33.072 55.968 33.096 56.16 ;
    END
  END o[319]
  PIN o[31]
    DIRECTION OUTPUT ;
    USE SIGNAL ;
    PORT
      LAYER M5 ;
        RECT  5.184 55.968 5.208 56.16 ;
    END
  END o[31]
  PIN o[320]
    DIRECTION OUTPUT ;
    USE SIGNAL ;
    PORT
      LAYER M3 ;
        RECT  33.156 56.016 33.174 56.16 ;
    END
  END o[320]
  PIN o[321]
    DIRECTION OUTPUT ;
    USE SIGNAL ;
    PORT
      LAYER M5 ;
        RECT  33.264 55.968 33.288 56.16 ;
    END
  END o[321]
  PIN o[322]
    DIRECTION OUTPUT ;
    USE SIGNAL ;
    PORT
      LAYER M3 ;
        RECT  33.336 56.016 33.354 56.16 ;
    END
  END o[322]
  PIN o[323]
    DIRECTION OUTPUT ;
    USE SIGNAL ;
    PORT
      LAYER M5 ;
        RECT  33.456 55.968 33.48 56.16 ;
    END
  END o[323]
  PIN o[324]
    DIRECTION OUTPUT ;
    USE SIGNAL ;
    PORT
      LAYER M3 ;
        RECT  33.552 56.016 33.57 56.16 ;
    END
  END o[324]
  PIN o[325]
    DIRECTION OUTPUT ;
    USE SIGNAL ;
    PORT
      LAYER M5 ;
        RECT  33.648 55.968 33.672 56.16 ;
    END
  END o[325]
  PIN o[326]
    DIRECTION OUTPUT ;
    USE SIGNAL ;
    PORT
      LAYER M3 ;
        RECT  33.732 56.016 33.75 56.16 ;
    END
  END o[326]
  PIN o[327]
    DIRECTION OUTPUT ;
    USE SIGNAL ;
    PORT
      LAYER M5 ;
        RECT  33.84 55.968 33.864 56.16 ;
    END
  END o[327]
  PIN o[328]
    DIRECTION OUTPUT ;
    USE SIGNAL ;
    PORT
      LAYER M3 ;
        RECT  33.912 56.016 33.93 56.16 ;
    END
  END o[328]
  PIN o[329]
    DIRECTION OUTPUT ;
    USE SIGNAL ;
    PORT
      LAYER M5 ;
        RECT  34.032 55.968 34.056 56.16 ;
    END
  END o[329]
  PIN o[32]
    DIRECTION OUTPUT ;
    USE SIGNAL ;
    PORT
      LAYER M3 ;
        RECT  5.292 56.016 5.31 56.16 ;
    END
  END o[32]
  PIN o[330]
    DIRECTION OUTPUT ;
    USE SIGNAL ;
    PORT
      LAYER M3 ;
        RECT  34.128 56.016 34.146 56.16 ;
    END
  END o[330]
  PIN o[331]
    DIRECTION OUTPUT ;
    USE SIGNAL ;
    PORT
      LAYER M5 ;
        RECT  34.224 55.968 34.248 56.16 ;
    END
  END o[331]
  PIN o[332]
    DIRECTION OUTPUT ;
    USE SIGNAL ;
    PORT
      LAYER M3 ;
        RECT  34.308 56.016 34.326 56.16 ;
    END
  END o[332]
  PIN o[333]
    DIRECTION OUTPUT ;
    USE SIGNAL ;
    PORT
      LAYER M5 ;
        RECT  34.416 55.968 34.44 56.16 ;
    END
  END o[333]
  PIN o[334]
    DIRECTION OUTPUT ;
    USE SIGNAL ;
    PORT
      LAYER M3 ;
        RECT  34.488 56.016 34.506 56.16 ;
    END
  END o[334]
  PIN o[335]
    DIRECTION OUTPUT ;
    USE SIGNAL ;
    PORT
      LAYER M5 ;
        RECT  34.608 55.968 34.632 56.16 ;
    END
  END o[335]
  PIN o[336]
    DIRECTION OUTPUT ;
    USE SIGNAL ;
    PORT
      LAYER M3 ;
        RECT  34.704 56.016 34.722 56.16 ;
    END
  END o[336]
  PIN o[337]
    DIRECTION OUTPUT ;
    USE SIGNAL ;
    PORT
      LAYER M5 ;
        RECT  34.8 55.968 34.824 56.16 ;
    END
  END o[337]
  PIN o[338]
    DIRECTION OUTPUT ;
    USE SIGNAL ;
    PORT
      LAYER M3 ;
        RECT  34.884 56.016 34.902 56.16 ;
    END
  END o[338]
  PIN o[339]
    DIRECTION OUTPUT ;
    USE SIGNAL ;
    PORT
      LAYER M5 ;
        RECT  34.992 55.968 35.016 56.16 ;
    END
  END o[339]
  PIN o[33]
    DIRECTION OUTPUT ;
    USE SIGNAL ;
    PORT
      LAYER M5 ;
        RECT  5.376 55.968 5.4 56.16 ;
    END
  END o[33]
  PIN o[340]
    DIRECTION OUTPUT ;
    USE SIGNAL ;
    PORT
      LAYER M3 ;
        RECT  35.1 56.016 35.118 56.16 ;
    END
  END o[340]
  PIN o[341]
    DIRECTION OUTPUT ;
    USE SIGNAL ;
    PORT
      LAYER M5 ;
        RECT  35.184 55.968 35.208 56.16 ;
    END
  END o[341]
  PIN o[342]
    DIRECTION OUTPUT ;
    USE SIGNAL ;
    PORT
      LAYER M3 ;
        RECT  35.28 56.016 35.298 56.16 ;
    END
  END o[342]
  PIN o[343]
    DIRECTION OUTPUT ;
    USE SIGNAL ;
    PORT
      LAYER M5 ;
        RECT  35.376 55.968 35.4 56.16 ;
    END
  END o[343]
  PIN o[344]
    DIRECTION OUTPUT ;
    USE SIGNAL ;
    PORT
      LAYER M3 ;
        RECT  35.46 56.016 35.478 56.16 ;
    END
  END o[344]
  PIN o[345]
    DIRECTION OUTPUT ;
    USE SIGNAL ;
    PORT
      LAYER M5 ;
        RECT  35.568 55.968 35.592 56.16 ;
    END
  END o[345]
  PIN o[346]
    DIRECTION OUTPUT ;
    USE SIGNAL ;
    PORT
      LAYER M3 ;
        RECT  35.676 56.016 35.694 56.16 ;
    END
  END o[346]
  PIN o[347]
    DIRECTION OUTPUT ;
    USE SIGNAL ;
    PORT
      LAYER M5 ;
        RECT  35.76 55.968 35.784 56.16 ;
    END
  END o[347]
  PIN o[348]
    DIRECTION OUTPUT ;
    USE SIGNAL ;
    PORT
      LAYER M3 ;
        RECT  35.856 56.016 35.874 56.16 ;
    END
  END o[348]
  PIN o[349]
    DIRECTION OUTPUT ;
    USE SIGNAL ;
    PORT
      LAYER M5 ;
        RECT  35.952 55.968 35.976 56.16 ;
    END
  END o[349]
  PIN o[34]
    DIRECTION OUTPUT ;
    USE SIGNAL ;
    PORT
      LAYER M3 ;
        RECT  5.472 56.016 5.49 56.16 ;
    END
  END o[34]
  PIN o[350]
    DIRECTION OUTPUT ;
    USE SIGNAL ;
    PORT
      LAYER M3 ;
        RECT  36.036 56.016 36.054 56.16 ;
    END
  END o[350]
  PIN o[351]
    DIRECTION OUTPUT ;
    USE SIGNAL ;
    PORT
      LAYER M5 ;
        RECT  36.144 55.968 36.168 56.16 ;
    END
  END o[351]
  PIN o[352]
    DIRECTION OUTPUT ;
    USE SIGNAL ;
    PORT
      LAYER M3 ;
        RECT  36.252 56.016 36.27 56.16 ;
    END
  END o[352]
  PIN o[353]
    DIRECTION OUTPUT ;
    USE SIGNAL ;
    PORT
      LAYER M5 ;
        RECT  36.336 55.968 36.36 56.16 ;
    END
  END o[353]
  PIN o[354]
    DIRECTION OUTPUT ;
    USE SIGNAL ;
    PORT
      LAYER M3 ;
        RECT  36.432 56.016 36.45 56.16 ;
    END
  END o[354]
  PIN o[355]
    DIRECTION OUTPUT ;
    USE SIGNAL ;
    PORT
      LAYER M5 ;
        RECT  36.528 55.968 36.552 56.16 ;
    END
  END o[355]
  PIN o[356]
    DIRECTION OUTPUT ;
    USE SIGNAL ;
    PORT
      LAYER M3 ;
        RECT  36.648 56.016 36.666 56.16 ;
    END
  END o[356]
  PIN o[357]
    DIRECTION OUTPUT ;
    USE SIGNAL ;
    PORT
      LAYER M5 ;
        RECT  36.72 55.968 36.744 56.16 ;
    END
  END o[357]
  PIN o[358]
    DIRECTION OUTPUT ;
    USE SIGNAL ;
    PORT
      LAYER M3 ;
        RECT  36.828 56.016 36.846 56.16 ;
    END
  END o[358]
  PIN o[359]
    DIRECTION OUTPUT ;
    USE SIGNAL ;
    PORT
      LAYER M5 ;
        RECT  36.912 55.968 36.936 56.16 ;
    END
  END o[359]
  PIN o[35]
    DIRECTION OUTPUT ;
    USE SIGNAL ;
    PORT
      LAYER M5 ;
        RECT  5.568 55.968 5.592 56.16 ;
    END
  END o[35]
  PIN o[360]
    DIRECTION OUTPUT ;
    USE SIGNAL ;
    PORT
      LAYER M3 ;
        RECT  37.008 56.016 37.026 56.16 ;
    END
  END o[360]
  PIN o[361]
    DIRECTION OUTPUT ;
    USE SIGNAL ;
    PORT
      LAYER M5 ;
        RECT  37.104 55.968 37.128 56.16 ;
    END
  END o[361]
  PIN o[362]
    DIRECTION OUTPUT ;
    USE SIGNAL ;
    PORT
      LAYER M3 ;
        RECT  37.224 56.016 37.242 56.16 ;
    END
  END o[362]
  PIN o[363]
    DIRECTION OUTPUT ;
    USE SIGNAL ;
    PORT
      LAYER M5 ;
        RECT  37.296 55.968 37.32 56.16 ;
    END
  END o[363]
  PIN o[364]
    DIRECTION OUTPUT ;
    USE SIGNAL ;
    PORT
      LAYER M3 ;
        RECT  37.404 56.016 37.422 56.16 ;
    END
  END o[364]
  PIN o[365]
    DIRECTION OUTPUT ;
    USE SIGNAL ;
    PORT
      LAYER M5 ;
        RECT  37.488 55.968 37.512 56.16 ;
    END
  END o[365]
  PIN o[366]
    DIRECTION OUTPUT ;
    USE SIGNAL ;
    PORT
      LAYER M3 ;
        RECT  37.584 56.016 37.602 56.16 ;
    END
  END o[366]
  PIN o[367]
    DIRECTION OUTPUT ;
    USE SIGNAL ;
    PORT
      LAYER M5 ;
        RECT  37.68 55.968 37.704 56.16 ;
    END
  END o[367]
  PIN o[368]
    DIRECTION OUTPUT ;
    USE SIGNAL ;
    PORT
      LAYER M3 ;
        RECT  37.8 56.016 37.818 56.16 ;
    END
  END o[368]
  PIN o[369]
    DIRECTION OUTPUT ;
    USE SIGNAL ;
    PORT
      LAYER M5 ;
        RECT  37.872 55.968 37.896 56.16 ;
    END
  END o[369]
  PIN o[36]
    DIRECTION OUTPUT ;
    USE SIGNAL ;
    PORT
      LAYER M3 ;
        RECT  5.688 56.016 5.706 56.16 ;
    END
  END o[36]
  PIN o[370]
    DIRECTION OUTPUT ;
    USE SIGNAL ;
    PORT
      LAYER M3 ;
        RECT  37.98 56.016 37.998 56.16 ;
    END
  END o[370]
  PIN o[371]
    DIRECTION OUTPUT ;
    USE SIGNAL ;
    PORT
      LAYER M5 ;
        RECT  38.064 55.968 38.088 56.16 ;
    END
  END o[371]
  PIN o[372]
    DIRECTION OUTPUT ;
    USE SIGNAL ;
    PORT
      LAYER M3 ;
        RECT  38.16 56.016 38.178 56.16 ;
    END
  END o[372]
  PIN o[373]
    DIRECTION OUTPUT ;
    USE SIGNAL ;
    PORT
      LAYER M5 ;
        RECT  38.256 55.968 38.28 56.16 ;
    END
  END o[373]
  PIN o[374]
    DIRECTION OUTPUT ;
    USE SIGNAL ;
    PORT
      LAYER M3 ;
        RECT  38.376 56.016 38.394 56.16 ;
    END
  END o[374]
  PIN o[375]
    DIRECTION OUTPUT ;
    USE SIGNAL ;
    PORT
      LAYER M5 ;
        RECT  38.448 55.968 38.472 56.16 ;
    END
  END o[375]
  PIN o[376]
    DIRECTION OUTPUT ;
    USE SIGNAL ;
    PORT
      LAYER M3 ;
        RECT  38.556 56.016 38.574 56.16 ;
    END
  END o[376]
  PIN o[377]
    DIRECTION OUTPUT ;
    USE SIGNAL ;
    PORT
      LAYER M5 ;
        RECT  38.64 55.968 38.664 56.16 ;
    END
  END o[377]
  PIN o[378]
    DIRECTION OUTPUT ;
    USE SIGNAL ;
    PORT
      LAYER M3 ;
        RECT  38.772 56.016 38.79 56.16 ;
    END
  END o[378]
  PIN o[379]
    DIRECTION OUTPUT ;
    USE SIGNAL ;
    PORT
      LAYER M5 ;
        RECT  38.832 55.968 38.856 56.16 ;
    END
  END o[379]
  PIN o[37]
    DIRECTION OUTPUT ;
    USE SIGNAL ;
    PORT
      LAYER M5 ;
        RECT  5.76 55.968 5.784 56.16 ;
    END
  END o[37]
  PIN o[380]
    DIRECTION OUTPUT ;
    USE SIGNAL ;
    PORT
      LAYER M3 ;
        RECT  38.952 56.016 38.97 56.16 ;
    END
  END o[380]
  PIN o[381]
    DIRECTION OUTPUT ;
    USE SIGNAL ;
    PORT
      LAYER M5 ;
        RECT  39.024 55.968 39.048 56.16 ;
    END
  END o[381]
  PIN o[382]
    DIRECTION OUTPUT ;
    USE SIGNAL ;
    PORT
      LAYER M3 ;
        RECT  39.132 56.016 39.15 56.16 ;
    END
  END o[382]
  PIN o[383]
    DIRECTION OUTPUT ;
    USE SIGNAL ;
    PORT
      LAYER M5 ;
        RECT  39.216 55.968 39.24 56.16 ;
    END
  END o[383]
  PIN o[384]
    DIRECTION OUTPUT ;
    USE SIGNAL ;
    PORT
      LAYER M3 ;
        RECT  39.348 56.016 39.366 56.16 ;
    END
  END o[384]
  PIN o[385]
    DIRECTION OUTPUT ;
    USE SIGNAL ;
    PORT
      LAYER M5 ;
        RECT  39.456 55.968 39.48 56.16 ;
    END
  END o[385]
  PIN o[386]
    DIRECTION OUTPUT ;
    USE SIGNAL ;
    PORT
      LAYER M3 ;
        RECT  39.528 56.016 39.546 56.16 ;
    END
  END o[386]
  PIN o[387]
    DIRECTION OUTPUT ;
    USE SIGNAL ;
    PORT
      LAYER M5 ;
        RECT  39.648 55.968 39.672 56.16 ;
    END
  END o[387]
  PIN o[388]
    DIRECTION OUTPUT ;
    USE SIGNAL ;
    PORT
      LAYER M3 ;
        RECT  39.708 56.016 39.726 56.16 ;
    END
  END o[388]
  PIN o[389]
    DIRECTION OUTPUT ;
    USE SIGNAL ;
    PORT
      LAYER M5 ;
        RECT  39.84 55.968 39.864 56.16 ;
    END
  END o[389]
  PIN o[38]
    DIRECTION OUTPUT ;
    USE SIGNAL ;
    PORT
      LAYER M3 ;
        RECT  5.868 56.016 5.886 56.16 ;
    END
  END o[38]
  PIN o[390]
    DIRECTION OUTPUT ;
    USE SIGNAL ;
    PORT
      LAYER M3 ;
        RECT  39.924 56.016 39.942 56.16 ;
    END
  END o[390]
  PIN o[391]
    DIRECTION OUTPUT ;
    USE SIGNAL ;
    PORT
      LAYER M5 ;
        RECT  40.032 55.968 40.056 56.16 ;
    END
  END o[391]
  PIN o[392]
    DIRECTION OUTPUT ;
    USE SIGNAL ;
    PORT
      LAYER M3 ;
        RECT  40.104 56.016 40.122 56.16 ;
    END
  END o[392]
  PIN o[393]
    DIRECTION OUTPUT ;
    USE SIGNAL ;
    PORT
      LAYER M5 ;
        RECT  40.224 55.968 40.248 56.16 ;
    END
  END o[393]
  PIN o[394]
    DIRECTION OUTPUT ;
    USE SIGNAL ;
    PORT
      LAYER M3 ;
        RECT  40.32 56.016 40.338 56.16 ;
    END
  END o[394]
  PIN o[395]
    DIRECTION OUTPUT ;
    USE SIGNAL ;
    PORT
      LAYER M5 ;
        RECT  40.416 55.968 40.44 56.16 ;
    END
  END o[395]
  PIN o[396]
    DIRECTION OUTPUT ;
    USE SIGNAL ;
    PORT
      LAYER M3 ;
        RECT  40.5 56.016 40.518 56.16 ;
    END
  END o[396]
  PIN o[397]
    DIRECTION OUTPUT ;
    USE SIGNAL ;
    PORT
      LAYER M5 ;
        RECT  40.608 55.968 40.632 56.16 ;
    END
  END o[397]
  PIN o[398]
    DIRECTION OUTPUT ;
    USE SIGNAL ;
    PORT
      LAYER M3 ;
        RECT  40.68 56.016 40.698 56.16 ;
    END
  END o[398]
  PIN o[399]
    DIRECTION OUTPUT ;
    USE SIGNAL ;
    PORT
      LAYER M5 ;
        RECT  40.8 55.968 40.824 56.16 ;
    END
  END o[399]
  PIN o[39]
    DIRECTION OUTPUT ;
    USE SIGNAL ;
    PORT
      LAYER M5 ;
        RECT  5.952 55.968 5.976 56.16 ;
    END
  END o[39]
  PIN o[3]
    DIRECTION OUTPUT ;
    USE SIGNAL ;
    PORT
      LAYER M5 ;
        RECT  2.496 55.968 2.52 56.16 ;
    END
  END o[3]
  PIN o[400]
    DIRECTION OUTPUT ;
    USE SIGNAL ;
    PORT
      LAYER M3 ;
        RECT  40.896 56.016 40.914 56.16 ;
    END
  END o[400]
  PIN o[401]
    DIRECTION OUTPUT ;
    USE SIGNAL ;
    PORT
      LAYER M5 ;
        RECT  40.992 55.968 41.016 56.16 ;
    END
  END o[401]
  PIN o[402]
    DIRECTION OUTPUT ;
    USE SIGNAL ;
    PORT
      LAYER M3 ;
        RECT  41.076 56.016 41.094 56.16 ;
    END
  END o[402]
  PIN o[403]
    DIRECTION OUTPUT ;
    USE SIGNAL ;
    PORT
      LAYER M5 ;
        RECT  41.184 55.968 41.208 56.16 ;
    END
  END o[403]
  PIN o[404]
    DIRECTION OUTPUT ;
    USE SIGNAL ;
    PORT
      LAYER M3 ;
        RECT  41.256 56.016 41.274 56.16 ;
    END
  END o[404]
  PIN o[405]
    DIRECTION OUTPUT ;
    USE SIGNAL ;
    PORT
      LAYER M5 ;
        RECT  41.376 55.968 41.4 56.16 ;
    END
  END o[405]
  PIN o[406]
    DIRECTION OUTPUT ;
    USE SIGNAL ;
    PORT
      LAYER M3 ;
        RECT  41.472 56.016 41.49 56.16 ;
    END
  END o[406]
  PIN o[407]
    DIRECTION OUTPUT ;
    USE SIGNAL ;
    PORT
      LAYER M5 ;
        RECT  41.568 55.968 41.592 56.16 ;
    END
  END o[407]
  PIN o[408]
    DIRECTION OUTPUT ;
    USE SIGNAL ;
    PORT
      LAYER M3 ;
        RECT  41.652 56.016 41.67 56.16 ;
    END
  END o[408]
  PIN o[409]
    DIRECTION OUTPUT ;
    USE SIGNAL ;
    PORT
      LAYER M5 ;
        RECT  41.76 55.968 41.784 56.16 ;
    END
  END o[409]
  PIN o[40]
    DIRECTION OUTPUT ;
    USE SIGNAL ;
    PORT
      LAYER M3 ;
        RECT  6.084 56.016 6.102 56.16 ;
    END
  END o[40]
  PIN o[410]
    DIRECTION OUTPUT ;
    USE SIGNAL ;
    PORT
      LAYER M3 ;
        RECT  41.868 56.016 41.886 56.16 ;
    END
  END o[410]
  PIN o[411]
    DIRECTION OUTPUT ;
    USE SIGNAL ;
    PORT
      LAYER M5 ;
        RECT  41.952 55.968 41.976 56.16 ;
    END
  END o[411]
  PIN o[412]
    DIRECTION OUTPUT ;
    USE SIGNAL ;
    PORT
      LAYER M3 ;
        RECT  42.048 56.016 42.066 56.16 ;
    END
  END o[412]
  PIN o[413]
    DIRECTION OUTPUT ;
    USE SIGNAL ;
    PORT
      LAYER M5 ;
        RECT  42.144 55.968 42.168 56.16 ;
    END
  END o[413]
  PIN o[414]
    DIRECTION OUTPUT ;
    USE SIGNAL ;
    PORT
      LAYER M3 ;
        RECT  42.228 56.016 42.246 56.16 ;
    END
  END o[414]
  PIN o[415]
    DIRECTION OUTPUT ;
    USE SIGNAL ;
    PORT
      LAYER M5 ;
        RECT  42.336 55.968 42.36 56.16 ;
    END
  END o[415]
  PIN o[416]
    DIRECTION OUTPUT ;
    USE SIGNAL ;
    PORT
      LAYER M3 ;
        RECT  42.444 56.016 42.462 56.16 ;
    END
  END o[416]
  PIN o[417]
    DIRECTION OUTPUT ;
    USE SIGNAL ;
    PORT
      LAYER M5 ;
        RECT  42.528 55.968 42.552 56.16 ;
    END
  END o[417]
  PIN o[418]
    DIRECTION OUTPUT ;
    USE SIGNAL ;
    PORT
      LAYER M3 ;
        RECT  42.624 56.016 42.642 56.16 ;
    END
  END o[418]
  PIN o[419]
    DIRECTION OUTPUT ;
    USE SIGNAL ;
    PORT
      LAYER M5 ;
        RECT  42.72 55.968 42.744 56.16 ;
    END
  END o[419]
  PIN o[41]
    DIRECTION OUTPUT ;
    USE SIGNAL ;
    PORT
      LAYER M5 ;
        RECT  6.144 55.968 6.168 56.16 ;
    END
  END o[41]
  PIN o[420]
    DIRECTION OUTPUT ;
    USE SIGNAL ;
    PORT
      LAYER M3 ;
        RECT  42.804 56.016 42.822 56.16 ;
    END
  END o[420]
  PIN o[421]
    DIRECTION OUTPUT ;
    USE SIGNAL ;
    PORT
      LAYER M5 ;
        RECT  42.912 55.968 42.936 56.16 ;
    END
  END o[421]
  PIN o[422]
    DIRECTION OUTPUT ;
    USE SIGNAL ;
    PORT
      LAYER M3 ;
        RECT  43.02 56.016 43.038 56.16 ;
    END
  END o[422]
  PIN o[423]
    DIRECTION OUTPUT ;
    USE SIGNAL ;
    PORT
      LAYER M5 ;
        RECT  43.104 55.968 43.128 56.16 ;
    END
  END o[423]
  PIN o[424]
    DIRECTION OUTPUT ;
    USE SIGNAL ;
    PORT
      LAYER M3 ;
        RECT  43.2 56.016 43.218 56.16 ;
    END
  END o[424]
  PIN o[425]
    DIRECTION OUTPUT ;
    USE SIGNAL ;
    PORT
      LAYER M5 ;
        RECT  43.296 55.968 43.32 56.16 ;
    END
  END o[425]
  PIN o[426]
    DIRECTION OUTPUT ;
    USE SIGNAL ;
    PORT
      LAYER M3 ;
        RECT  43.416 56.016 43.434 56.16 ;
    END
  END o[426]
  PIN o[427]
    DIRECTION OUTPUT ;
    USE SIGNAL ;
    PORT
      LAYER M5 ;
        RECT  43.488 55.968 43.512 56.16 ;
    END
  END o[427]
  PIN o[428]
    DIRECTION OUTPUT ;
    USE SIGNAL ;
    PORT
      LAYER M3 ;
        RECT  43.596 56.016 43.614 56.16 ;
    END
  END o[428]
  PIN o[429]
    DIRECTION OUTPUT ;
    USE SIGNAL ;
    PORT
      LAYER M5 ;
        RECT  43.68 55.968 43.704 56.16 ;
    END
  END o[429]
  PIN o[42]
    DIRECTION OUTPUT ;
    USE SIGNAL ;
    PORT
      LAYER M3 ;
        RECT  6.264 56.016 6.282 56.16 ;
    END
  END o[42]
  PIN o[430]
    DIRECTION OUTPUT ;
    USE SIGNAL ;
    PORT
      LAYER M3 ;
        RECT  43.776 56.016 43.794 56.16 ;
    END
  END o[430]
  PIN o[431]
    DIRECTION OUTPUT ;
    USE SIGNAL ;
    PORT
      LAYER M5 ;
        RECT  43.872 55.968 43.896 56.16 ;
    END
  END o[431]
  PIN o[432]
    DIRECTION OUTPUT ;
    USE SIGNAL ;
    PORT
      LAYER M3 ;
        RECT  43.992 56.016 44.01 56.16 ;
    END
  END o[432]
  PIN o[433]
    DIRECTION OUTPUT ;
    USE SIGNAL ;
    PORT
      LAYER M5 ;
        RECT  44.064 55.968 44.088 56.16 ;
    END
  END o[433]
  PIN o[434]
    DIRECTION OUTPUT ;
    USE SIGNAL ;
    PORT
      LAYER M3 ;
        RECT  44.172 56.016 44.19 56.16 ;
    END
  END o[434]
  PIN o[435]
    DIRECTION OUTPUT ;
    USE SIGNAL ;
    PORT
      LAYER M5 ;
        RECT  44.256 55.968 44.28 56.16 ;
    END
  END o[435]
  PIN o[436]
    DIRECTION OUTPUT ;
    USE SIGNAL ;
    PORT
      LAYER M3 ;
        RECT  44.352 56.016 44.37 56.16 ;
    END
  END o[436]
  PIN o[437]
    DIRECTION OUTPUT ;
    USE SIGNAL ;
    PORT
      LAYER M5 ;
        RECT  44.448 55.968 44.472 56.16 ;
    END
  END o[437]
  PIN o[438]
    DIRECTION OUTPUT ;
    USE SIGNAL ;
    PORT
      LAYER M3 ;
        RECT  44.568 56.016 44.586 56.16 ;
    END
  END o[438]
  PIN o[439]
    DIRECTION OUTPUT ;
    USE SIGNAL ;
    PORT
      LAYER M5 ;
        RECT  44.64 55.968 44.664 56.16 ;
    END
  END o[439]
  PIN o[43]
    DIRECTION OUTPUT ;
    USE SIGNAL ;
    PORT
      LAYER M5 ;
        RECT  6.336 55.968 6.36 56.16 ;
    END
  END o[43]
  PIN o[440]
    DIRECTION OUTPUT ;
    USE SIGNAL ;
    PORT
      LAYER M3 ;
        RECT  44.748 56.016 44.766 56.16 ;
    END
  END o[440]
  PIN o[441]
    DIRECTION OUTPUT ;
    USE SIGNAL ;
    PORT
      LAYER M5 ;
        RECT  44.832 55.968 44.856 56.16 ;
    END
  END o[441]
  PIN o[442]
    DIRECTION OUTPUT ;
    USE SIGNAL ;
    PORT
      LAYER M3 ;
        RECT  44.964 56.016 44.982 56.16 ;
    END
  END o[442]
  PIN o[443]
    DIRECTION OUTPUT ;
    USE SIGNAL ;
    PORT
      LAYER M5 ;
        RECT  45.024 55.968 45.048 56.16 ;
    END
  END o[443]
  PIN o[444]
    DIRECTION OUTPUT ;
    USE SIGNAL ;
    PORT
      LAYER M3 ;
        RECT  45.144 56.016 45.162 56.16 ;
    END
  END o[444]
  PIN o[445]
    DIRECTION OUTPUT ;
    USE SIGNAL ;
    PORT
      LAYER M5 ;
        RECT  45.216 55.968 45.24 56.16 ;
    END
  END o[445]
  PIN o[446]
    DIRECTION OUTPUT ;
    USE SIGNAL ;
    PORT
      LAYER M3 ;
        RECT  45.324 56.016 45.342 56.16 ;
    END
  END o[446]
  PIN o[447]
    DIRECTION OUTPUT ;
    USE SIGNAL ;
    PORT
      LAYER M5 ;
        RECT  45.408 55.968 45.432 56.16 ;
    END
  END o[447]
  PIN o[448]
    DIRECTION OUTPUT ;
    USE SIGNAL ;
    PORT
      LAYER M3 ;
        RECT  45.54 56.016 45.558 56.16 ;
    END
  END o[448]
  PIN o[449]
    DIRECTION OUTPUT ;
    USE SIGNAL ;
    PORT
      LAYER M5 ;
        RECT  45.6 55.968 45.624 56.16 ;
    END
  END o[449]
  PIN o[44]
    DIRECTION OUTPUT ;
    USE SIGNAL ;
    PORT
      LAYER M3 ;
        RECT  6.444 56.016 6.462 56.16 ;
    END
  END o[44]
  PIN o[450]
    DIRECTION OUTPUT ;
    USE SIGNAL ;
    PORT
      LAYER M3 ;
        RECT  45.72 56.016 45.738 56.16 ;
    END
  END o[450]
  PIN o[451]
    DIRECTION OUTPUT ;
    USE SIGNAL ;
    PORT
      LAYER M5 ;
        RECT  45.792 55.968 45.816 56.16 ;
    END
  END o[451]
  PIN o[452]
    DIRECTION OUTPUT ;
    USE SIGNAL ;
    PORT
      LAYER M3 ;
        RECT  45.9 56.016 45.918 56.16 ;
    END
  END o[452]
  PIN o[453]
    DIRECTION OUTPUT ;
    USE SIGNAL ;
    PORT
      LAYER M5 ;
        RECT  46.032 55.968 46.056 56.16 ;
    END
  END o[453]
  PIN o[454]
    DIRECTION OUTPUT ;
    USE SIGNAL ;
    PORT
      LAYER M3 ;
        RECT  46.116 56.016 46.134 56.16 ;
    END
  END o[454]
  PIN o[455]
    DIRECTION OUTPUT ;
    USE SIGNAL ;
    PORT
      LAYER M5 ;
        RECT  46.224 55.968 46.248 56.16 ;
    END
  END o[455]
  PIN o[456]
    DIRECTION OUTPUT ;
    USE SIGNAL ;
    PORT
      LAYER M3 ;
        RECT  46.296 56.016 46.314 56.16 ;
    END
  END o[456]
  PIN o[457]
    DIRECTION OUTPUT ;
    USE SIGNAL ;
    PORT
      LAYER M5 ;
        RECT  46.416 55.968 46.44 56.16 ;
    END
  END o[457]
  PIN o[458]
    DIRECTION OUTPUT ;
    USE SIGNAL ;
    PORT
      LAYER M3 ;
        RECT  46.512 56.016 46.53 56.16 ;
    END
  END o[458]
  PIN o[459]
    DIRECTION OUTPUT ;
    USE SIGNAL ;
    PORT
      LAYER M5 ;
        RECT  46.608 55.968 46.632 56.16 ;
    END
  END o[459]
  PIN o[45]
    DIRECTION OUTPUT ;
    USE SIGNAL ;
    PORT
      LAYER M5 ;
        RECT  6.528 55.968 6.552 56.16 ;
    END
  END o[45]
  PIN o[460]
    DIRECTION OUTPUT ;
    USE SIGNAL ;
    PORT
      LAYER M3 ;
        RECT  46.692 56.016 46.71 56.16 ;
    END
  END o[460]
  PIN o[461]
    DIRECTION OUTPUT ;
    USE SIGNAL ;
    PORT
      LAYER M5 ;
        RECT  46.8 55.968 46.824 56.16 ;
    END
  END o[461]
  PIN o[462]
    DIRECTION OUTPUT ;
    USE SIGNAL ;
    PORT
      LAYER M3 ;
        RECT  46.872 56.016 46.89 56.16 ;
    END
  END o[462]
  PIN o[463]
    DIRECTION OUTPUT ;
    USE SIGNAL ;
    PORT
      LAYER M5 ;
        RECT  46.992 55.968 47.016 56.16 ;
    END
  END o[463]
  PIN o[464]
    DIRECTION OUTPUT ;
    USE SIGNAL ;
    PORT
      LAYER M3 ;
        RECT  47.088 56.016 47.106 56.16 ;
    END
  END o[464]
  PIN o[465]
    DIRECTION OUTPUT ;
    USE SIGNAL ;
    PORT
      LAYER M5 ;
        RECT  47.184 55.968 47.208 56.16 ;
    END
  END o[465]
  PIN o[466]
    DIRECTION OUTPUT ;
    USE SIGNAL ;
    PORT
      LAYER M3 ;
        RECT  47.268 56.016 47.286 56.16 ;
    END
  END o[466]
  PIN o[467]
    DIRECTION OUTPUT ;
    USE SIGNAL ;
    PORT
      LAYER M5 ;
        RECT  47.376 55.968 47.4 56.16 ;
    END
  END o[467]
  PIN o[468]
    DIRECTION OUTPUT ;
    USE SIGNAL ;
    PORT
      LAYER M3 ;
        RECT  47.448 56.016 47.466 56.16 ;
    END
  END o[468]
  PIN o[469]
    DIRECTION OUTPUT ;
    USE SIGNAL ;
    PORT
      LAYER M5 ;
        RECT  47.568 55.968 47.592 56.16 ;
    END
  END o[469]
  PIN o[46]
    DIRECTION OUTPUT ;
    USE SIGNAL ;
    PORT
      LAYER M3 ;
        RECT  6.66 56.016 6.678 56.16 ;
    END
  END o[46]
  PIN o[470]
    DIRECTION OUTPUT ;
    USE SIGNAL ;
    PORT
      LAYER M3 ;
        RECT  47.664 56.016 47.682 56.16 ;
    END
  END o[470]
  PIN o[471]
    DIRECTION OUTPUT ;
    USE SIGNAL ;
    PORT
      LAYER M5 ;
        RECT  47.76 55.968 47.784 56.16 ;
    END
  END o[471]
  PIN o[472]
    DIRECTION OUTPUT ;
    USE SIGNAL ;
    PORT
      LAYER M3 ;
        RECT  47.844 56.016 47.862 56.16 ;
    END
  END o[472]
  PIN o[473]
    DIRECTION OUTPUT ;
    USE SIGNAL ;
    PORT
      LAYER M5 ;
        RECT  47.952 55.968 47.976 56.16 ;
    END
  END o[473]
  PIN o[474]
    DIRECTION OUTPUT ;
    USE SIGNAL ;
    PORT
      LAYER M3 ;
        RECT  48.06 56.016 48.078 56.16 ;
    END
  END o[474]
  PIN o[475]
    DIRECTION OUTPUT ;
    USE SIGNAL ;
    PORT
      LAYER M5 ;
        RECT  48.144 55.968 48.168 56.16 ;
    END
  END o[475]
  PIN o[476]
    DIRECTION OUTPUT ;
    USE SIGNAL ;
    PORT
      LAYER M3 ;
        RECT  48.24 56.016 48.258 56.16 ;
    END
  END o[476]
  PIN o[477]
    DIRECTION OUTPUT ;
    USE SIGNAL ;
    PORT
      LAYER M5 ;
        RECT  48.336 55.968 48.36 56.16 ;
    END
  END o[477]
  PIN o[478]
    DIRECTION OUTPUT ;
    USE SIGNAL ;
    PORT
      LAYER M3 ;
        RECT  48.42 56.016 48.438 56.16 ;
    END
  END o[478]
  PIN o[479]
    DIRECTION OUTPUT ;
    USE SIGNAL ;
    PORT
      LAYER M5 ;
        RECT  48.528 55.968 48.552 56.16 ;
    END
  END o[479]
  PIN o[47]
    DIRECTION OUTPUT ;
    USE SIGNAL ;
    PORT
      LAYER M5 ;
        RECT  6.72 55.968 6.744 56.16 ;
    END
  END o[47]
  PIN o[480]
    DIRECTION OUTPUT ;
    USE SIGNAL ;
    PORT
      LAYER M3 ;
        RECT  48.636 56.016 48.654 56.16 ;
    END
  END o[480]
  PIN o[481]
    DIRECTION OUTPUT ;
    USE SIGNAL ;
    PORT
      LAYER M5 ;
        RECT  48.72 55.968 48.744 56.16 ;
    END
  END o[481]
  PIN o[482]
    DIRECTION OUTPUT ;
    USE SIGNAL ;
    PORT
      LAYER M3 ;
        RECT  48.816 56.016 48.834 56.16 ;
    END
  END o[482]
  PIN o[483]
    DIRECTION OUTPUT ;
    USE SIGNAL ;
    PORT
      LAYER M5 ;
        RECT  48.912 55.968 48.936 56.16 ;
    END
  END o[483]
  PIN o[484]
    DIRECTION OUTPUT ;
    USE SIGNAL ;
    PORT
      LAYER M3 ;
        RECT  48.996 56.016 49.014 56.16 ;
    END
  END o[484]
  PIN o[485]
    DIRECTION OUTPUT ;
    USE SIGNAL ;
    PORT
      LAYER M5 ;
        RECT  49.104 55.968 49.128 56.16 ;
    END
  END o[485]
  PIN o[486]
    DIRECTION OUTPUT ;
    USE SIGNAL ;
    PORT
      LAYER M3 ;
        RECT  49.212 56.016 49.23 56.16 ;
    END
  END o[486]
  PIN o[487]
    DIRECTION OUTPUT ;
    USE SIGNAL ;
    PORT
      LAYER M5 ;
        RECT  49.296 55.968 49.32 56.16 ;
    END
  END o[487]
  PIN o[488]
    DIRECTION OUTPUT ;
    USE SIGNAL ;
    PORT
      LAYER M3 ;
        RECT  49.392 56.016 49.41 56.16 ;
    END
  END o[488]
  PIN o[489]
    DIRECTION OUTPUT ;
    USE SIGNAL ;
    PORT
      LAYER M5 ;
        RECT  49.488 55.968 49.512 56.16 ;
    END
  END o[489]
  PIN o[48]
    DIRECTION OUTPUT ;
    USE SIGNAL ;
    PORT
      LAYER M3 ;
        RECT  6.84 56.016 6.858 56.16 ;
    END
  END o[48]
  PIN o[490]
    DIRECTION OUTPUT ;
    USE SIGNAL ;
    PORT
      LAYER M3 ;
        RECT  49.608 56.016 49.626 56.16 ;
    END
  END o[490]
  PIN o[491]
    DIRECTION OUTPUT ;
    USE SIGNAL ;
    PORT
      LAYER M5 ;
        RECT  49.68 55.968 49.704 56.16 ;
    END
  END o[491]
  PIN o[492]
    DIRECTION OUTPUT ;
    USE SIGNAL ;
    PORT
      LAYER M3 ;
        RECT  49.788 56.016 49.806 56.16 ;
    END
  END o[492]
  PIN o[493]
    DIRECTION OUTPUT ;
    USE SIGNAL ;
    PORT
      LAYER M5 ;
        RECT  49.872 55.968 49.896 56.16 ;
    END
  END o[493]
  PIN o[494]
    DIRECTION OUTPUT ;
    USE SIGNAL ;
    PORT
      LAYER M3 ;
        RECT  49.968 56.016 49.986 56.16 ;
    END
  END o[494]
  PIN o[495]
    DIRECTION OUTPUT ;
    USE SIGNAL ;
    PORT
      LAYER M5 ;
        RECT  50.064 55.968 50.088 56.16 ;
    END
  END o[495]
  PIN o[496]
    DIRECTION OUTPUT ;
    USE SIGNAL ;
    PORT
      LAYER M3 ;
        RECT  50.184 56.016 50.202 56.16 ;
    END
  END o[496]
  PIN o[497]
    DIRECTION OUTPUT ;
    USE SIGNAL ;
    PORT
      LAYER M5 ;
        RECT  50.256 55.968 50.28 56.16 ;
    END
  END o[497]
  PIN o[498]
    DIRECTION OUTPUT ;
    USE SIGNAL ;
    PORT
      LAYER M3 ;
        RECT  50.364 56.016 50.382 56.16 ;
    END
  END o[498]
  PIN o[499]
    DIRECTION OUTPUT ;
    USE SIGNAL ;
    PORT
      LAYER M5 ;
        RECT  50.448 55.968 50.472 56.16 ;
    END
  END o[499]
  PIN o[49]
    DIRECTION OUTPUT ;
    USE SIGNAL ;
    PORT
      LAYER M5 ;
        RECT  6.912 55.968 6.936 56.16 ;
    END
  END o[49]
  PIN o[4]
    DIRECTION OUTPUT ;
    USE SIGNAL ;
    PORT
      LAYER M3 ;
        RECT  2.592 56.016 2.61 56.16 ;
    END
  END o[4]
  PIN o[500]
    DIRECTION OUTPUT ;
    USE SIGNAL ;
    PORT
      LAYER M3 ;
        RECT  50.544 56.016 50.562 56.16 ;
    END
  END o[500]
  PIN o[501]
    DIRECTION OUTPUT ;
    USE SIGNAL ;
    PORT
      LAYER M5 ;
        RECT  50.64 55.968 50.664 56.16 ;
    END
  END o[501]
  PIN o[502]
    DIRECTION OUTPUT ;
    USE SIGNAL ;
    PORT
      LAYER M3 ;
        RECT  50.76 56.016 50.778 56.16 ;
    END
  END o[502]
  PIN o[503]
    DIRECTION OUTPUT ;
    USE SIGNAL ;
    PORT
      LAYER M5 ;
        RECT  50.832 55.968 50.856 56.16 ;
    END
  END o[503]
  PIN o[504]
    DIRECTION OUTPUT ;
    USE SIGNAL ;
    PORT
      LAYER M3 ;
        RECT  50.94 56.016 50.958 56.16 ;
    END
  END o[504]
  PIN o[505]
    DIRECTION OUTPUT ;
    USE SIGNAL ;
    PORT
      LAYER M5 ;
        RECT  51.024 55.968 51.048 56.16 ;
    END
  END o[505]
  PIN o[506]
    DIRECTION OUTPUT ;
    USE SIGNAL ;
    PORT
      LAYER M3 ;
        RECT  51.12 56.016 51.138 56.16 ;
    END
  END o[506]
  PIN o[507]
    DIRECTION OUTPUT ;
    USE SIGNAL ;
    PORT
      LAYER M5 ;
        RECT  51.216 55.968 51.24 56.16 ;
    END
  END o[507]
  PIN o[508]
    DIRECTION OUTPUT ;
    USE SIGNAL ;
    PORT
      LAYER M3 ;
        RECT  51.336 56.016 51.354 56.16 ;
    END
  END o[508]
  PIN o[509]
    DIRECTION OUTPUT ;
    USE SIGNAL ;
    PORT
      LAYER M5 ;
        RECT  51.408 55.968 51.432 56.16 ;
    END
  END o[509]
  PIN o[50]
    DIRECTION OUTPUT ;
    USE SIGNAL ;
    PORT
      LAYER M3 ;
        RECT  7.02 56.016 7.038 56.16 ;
    END
  END o[50]
  PIN o[510]
    DIRECTION OUTPUT ;
    USE SIGNAL ;
    PORT
      LAYER M3 ;
        RECT  51.516 56.016 51.534 56.16 ;
    END
  END o[510]
  PIN o[511]
    DIRECTION OUTPUT ;
    USE SIGNAL ;
    PORT
      LAYER M5 ;
        RECT  51.6 55.968 51.624 56.16 ;
    END
  END o[511]
  PIN o[512]
    DIRECTION OUTPUT ;
    USE SIGNAL ;
    PORT
      LAYER M3 ;
        RECT  51.732 56.016 51.75 56.16 ;
    END
  END o[512]
  PIN o[513]
    DIRECTION OUTPUT ;
    USE SIGNAL ;
    PORT
      LAYER M5 ;
        RECT  51.792 55.968 51.816 56.16 ;
    END
  END o[513]
  PIN o[514]
    DIRECTION OUTPUT ;
    USE SIGNAL ;
    PORT
      LAYER M3 ;
        RECT  51.912 56.016 51.93 56.16 ;
    END
  END o[514]
  PIN o[515]
    DIRECTION OUTPUT ;
    USE SIGNAL ;
    PORT
      LAYER M5 ;
        RECT  51.984 55.968 52.008 56.16 ;
    END
  END o[515]
  PIN o[516]
    DIRECTION OUTPUT ;
    USE SIGNAL ;
    PORT
      LAYER M3 ;
        RECT  52.092 56.016 52.11 56.16 ;
    END
  END o[516]
  PIN o[517]
    DIRECTION OUTPUT ;
    USE SIGNAL ;
    PORT
      LAYER M5 ;
        RECT  52.176 55.968 52.2 56.16 ;
    END
  END o[517]
  PIN o[518]
    DIRECTION OUTPUT ;
    USE SIGNAL ;
    PORT
      LAYER M3 ;
        RECT  52.308 56.016 52.326 56.16 ;
    END
  END o[518]
  PIN o[519]
    DIRECTION OUTPUT ;
    USE SIGNAL ;
    PORT
      LAYER M5 ;
        RECT  52.416 55.968 52.44 56.16 ;
    END
  END o[519]
  PIN o[51]
    DIRECTION OUTPUT ;
    USE SIGNAL ;
    PORT
      LAYER M5 ;
        RECT  7.152 55.968 7.176 56.16 ;
    END
  END o[51]
  PIN o[520]
    DIRECTION OUTPUT ;
    USE SIGNAL ;
    PORT
      LAYER M3 ;
        RECT  52.488 56.016 52.506 56.16 ;
    END
  END o[520]
  PIN o[521]
    DIRECTION OUTPUT ;
    USE SIGNAL ;
    PORT
      LAYER M5 ;
        RECT  52.608 55.968 52.632 56.16 ;
    END
  END o[521]
  PIN o[522]
    DIRECTION OUTPUT ;
    USE SIGNAL ;
    PORT
      LAYER M3 ;
        RECT  52.668 56.016 52.686 56.16 ;
    END
  END o[522]
  PIN o[523]
    DIRECTION OUTPUT ;
    USE SIGNAL ;
    PORT
      LAYER M5 ;
        RECT  52.8 55.968 52.824 56.16 ;
    END
  END o[523]
  PIN o[524]
    DIRECTION OUTPUT ;
    USE SIGNAL ;
    PORT
      LAYER M3 ;
        RECT  52.884 56.016 52.902 56.16 ;
    END
  END o[524]
  PIN o[525]
    DIRECTION OUTPUT ;
    USE SIGNAL ;
    PORT
      LAYER M5 ;
        RECT  52.992 55.968 53.016 56.16 ;
    END
  END o[525]
  PIN o[526]
    DIRECTION OUTPUT ;
    USE SIGNAL ;
    PORT
      LAYER M3 ;
        RECT  53.064 56.016 53.082 56.16 ;
    END
  END o[526]
  PIN o[527]
    DIRECTION OUTPUT ;
    USE SIGNAL ;
    PORT
      LAYER M5 ;
        RECT  53.184 55.968 53.208 56.16 ;
    END
  END o[527]
  PIN o[528]
    DIRECTION OUTPUT ;
    USE SIGNAL ;
    PORT
      LAYER M3 ;
        RECT  53.28 56.016 53.298 56.16 ;
    END
  END o[528]
  PIN o[529]
    DIRECTION OUTPUT ;
    USE SIGNAL ;
    PORT
      LAYER M5 ;
        RECT  53.376 55.968 53.4 56.16 ;
    END
  END o[529]
  PIN o[52]
    DIRECTION OUTPUT ;
    USE SIGNAL ;
    PORT
      LAYER M3 ;
        RECT  7.236 56.016 7.254 56.16 ;
    END
  END o[52]
  PIN o[530]
    DIRECTION OUTPUT ;
    USE SIGNAL ;
    PORT
      LAYER M3 ;
        RECT  53.46 56.016 53.478 56.16 ;
    END
    PORT
      LAYER M3 ;
        RECT  53.424 56.028 53.55 56.093 ;
    END
  END o[530]
  PIN o[531]
    DIRECTION OUTPUT ;
    USE SIGNAL ;
    PORT
      LAYER M5 ;
        RECT  53.568 55.968 53.592 56.16 ;
    END
  END o[531]
  PIN o[532]
    DIRECTION OUTPUT ;
    USE SIGNAL ;
    PORT
      LAYER M3 ;
        RECT  53.64 56.016 53.658 56.16 ;
    END
  END o[532]
  PIN o[533]
    DIRECTION OUTPUT ;
    USE SIGNAL ;
    PORT
      LAYER M5 ;
        RECT  53.76 55.968 53.784 56.16 ;
    END
  END o[533]
  PIN o[534]
    DIRECTION OUTPUT ;
    USE SIGNAL ;
    PORT
      LAYER M3 ;
        RECT  53.856 56.016 53.874 56.16 ;
    END
  END o[534]
  PIN o[535]
    DIRECTION OUTPUT ;
    USE SIGNAL ;
    PORT
      LAYER M5 ;
        RECT  53.952 55.968 53.976 56.16 ;
    END
  END o[535]
  PIN o[53]
    DIRECTION OUTPUT ;
    USE SIGNAL ;
    PORT
      LAYER M5 ;
        RECT  7.344 55.968 7.368 56.16 ;
    END
  END o[53]
  PIN o[54]
    DIRECTION OUTPUT ;
    USE SIGNAL ;
    PORT
      LAYER M3 ;
        RECT  7.416 56.016 7.434 56.16 ;
    END
  END o[54]
  PIN o[55]
    DIRECTION OUTPUT ;
    USE SIGNAL ;
    PORT
      LAYER M5 ;
        RECT  7.536 55.968 7.56 56.16 ;
    END
  END o[55]
  PIN o[56]
    DIRECTION OUTPUT ;
    USE SIGNAL ;
    PORT
      LAYER M3 ;
        RECT  7.632 56.016 7.65 56.16 ;
    END
  END o[56]
  PIN o[57]
    DIRECTION OUTPUT ;
    USE SIGNAL ;
    PORT
      LAYER M5 ;
        RECT  7.728 55.968 7.752 56.16 ;
    END
  END o[57]
  PIN o[58]
    DIRECTION OUTPUT ;
    USE SIGNAL ;
    PORT
      LAYER M3 ;
        RECT  7.812 56.016 7.83 56.16 ;
    END
  END o[58]
  PIN o[59]
    DIRECTION OUTPUT ;
    USE SIGNAL ;
    PORT
      LAYER M5 ;
        RECT  7.92 55.968 7.944 56.16 ;
    END
  END o[59]
  PIN o[5]
    DIRECTION OUTPUT ;
    USE SIGNAL ;
    PORT
      LAYER M5 ;
        RECT  2.688 55.968 2.712 56.16 ;
    END
  END o[5]
  PIN o[60]
    DIRECTION OUTPUT ;
    USE SIGNAL ;
    PORT
      LAYER M3 ;
        RECT  7.992 56.016 8.01 56.16 ;
    END
  END o[60]
  PIN o[61]
    DIRECTION OUTPUT ;
    USE SIGNAL ;
    PORT
      LAYER M5 ;
        RECT  8.112 55.968 8.136 56.16 ;
    END
  END o[61]
  PIN o[62]
    DIRECTION OUTPUT ;
    USE SIGNAL ;
    PORT
      LAYER M3 ;
        RECT  8.208 56.016 8.226 56.16 ;
    END
  END o[62]
  PIN o[63]
    DIRECTION OUTPUT ;
    USE SIGNAL ;
    PORT
      LAYER M5 ;
        RECT  8.304 55.968 8.328 56.16 ;
    END
  END o[63]
  PIN o[64]
    DIRECTION OUTPUT ;
    USE SIGNAL ;
    PORT
      LAYER M3 ;
        RECT  8.388 56.016 8.406 56.16 ;
    END
  END o[64]
  PIN o[65]
    DIRECTION OUTPUT ;
    USE SIGNAL ;
    PORT
      LAYER M5 ;
        RECT  8.496 55.968 8.52 56.16 ;
    END
  END o[65]
  PIN o[66]
    DIRECTION OUTPUT ;
    USE SIGNAL ;
    PORT
      LAYER M3 ;
        RECT  8.568 56.016 8.586 56.16 ;
    END
  END o[66]
  PIN o[67]
    DIRECTION OUTPUT ;
    USE SIGNAL ;
    PORT
      LAYER M5 ;
        RECT  8.688 55.968 8.712 56.16 ;
    END
  END o[67]
  PIN o[68]
    DIRECTION OUTPUT ;
    USE SIGNAL ;
    PORT
      LAYER M3 ;
        RECT  8.784 56.016 8.802 56.16 ;
    END
  END o[68]
  PIN o[69]
    DIRECTION OUTPUT ;
    USE SIGNAL ;
    PORT
      LAYER M5 ;
        RECT  8.88 55.968 8.904 56.16 ;
    END
  END o[69]
  PIN o[6]
    DIRECTION OUTPUT ;
    USE SIGNAL ;
    PORT
      LAYER M3 ;
        RECT  2.772 56.016 2.79 56.16 ;
    END
  END o[6]
  PIN o[70]
    DIRECTION OUTPUT ;
    USE SIGNAL ;
    PORT
      LAYER M3 ;
        RECT  8.964 56.016 8.982 56.16 ;
    END
  END o[70]
  PIN o[71]
    DIRECTION OUTPUT ;
    USE SIGNAL ;
    PORT
      LAYER M5 ;
        RECT  9.072 55.968 9.096 56.16 ;
    END
  END o[71]
  PIN o[72]
    DIRECTION OUTPUT ;
    USE SIGNAL ;
    PORT
      LAYER M3 ;
        RECT  9.18 56.016 9.198 56.16 ;
    END
  END o[72]
  PIN o[73]
    DIRECTION OUTPUT ;
    USE SIGNAL ;
    PORT
      LAYER M5 ;
        RECT  9.264 55.968 9.288 56.16 ;
    END
  END o[73]
  PIN o[74]
    DIRECTION OUTPUT ;
    USE SIGNAL ;
    PORT
      LAYER M3 ;
        RECT  9.36 56.016 9.378 56.16 ;
    END
  END o[74]
  PIN o[75]
    DIRECTION OUTPUT ;
    USE SIGNAL ;
    PORT
      LAYER M5 ;
        RECT  9.456 55.968 9.48 56.16 ;
    END
  END o[75]
  PIN o[76]
    DIRECTION OUTPUT ;
    USE SIGNAL ;
    PORT
      LAYER M3 ;
        RECT  9.54 56.016 9.558 56.16 ;
    END
  END o[76]
  PIN o[77]
    DIRECTION OUTPUT ;
    USE SIGNAL ;
    PORT
      LAYER M5 ;
        RECT  9.648 55.968 9.672 56.16 ;
    END
  END o[77]
  PIN o[78]
    DIRECTION OUTPUT ;
    USE SIGNAL ;
    PORT
      LAYER M3 ;
        RECT  9.756 56.016 9.774 56.16 ;
    END
  END o[78]
  PIN o[79]
    DIRECTION OUTPUT ;
    USE SIGNAL ;
    PORT
      LAYER M5 ;
        RECT  9.84 55.968 9.864 56.16 ;
    END
  END o[79]
  PIN o[7]
    DIRECTION OUTPUT ;
    USE SIGNAL ;
    PORT
      LAYER M5 ;
        RECT  2.88 55.968 2.904 56.16 ;
    END
  END o[7]
  PIN o[80]
    DIRECTION OUTPUT ;
    USE SIGNAL ;
    PORT
      LAYER M3 ;
        RECT  9.936 56.016 9.954 56.16 ;
    END
  END o[80]
  PIN o[81]
    DIRECTION OUTPUT ;
    USE SIGNAL ;
    PORT
      LAYER M5 ;
        RECT  10.032 55.968 10.056 56.16 ;
    END
  END o[81]
  PIN o[82]
    DIRECTION OUTPUT ;
    USE SIGNAL ;
    PORT
      LAYER M3 ;
        RECT  10.116 56.016 10.134 56.16 ;
    END
  END o[82]
  PIN o[83]
    DIRECTION OUTPUT ;
    USE SIGNAL ;
    PORT
      LAYER M5 ;
        RECT  10.224 55.968 10.248 56.16 ;
    END
  END o[83]
  PIN o[84]
    DIRECTION OUTPUT ;
    USE SIGNAL ;
    PORT
      LAYER M3 ;
        RECT  10.332 56.016 10.35 56.16 ;
    END
  END o[84]
  PIN o[85]
    DIRECTION OUTPUT ;
    USE SIGNAL ;
    PORT
      LAYER M5 ;
        RECT  10.416 55.968 10.44 56.16 ;
    END
  END o[85]
  PIN o[86]
    DIRECTION OUTPUT ;
    USE SIGNAL ;
    PORT
      LAYER M3 ;
        RECT  10.512 56.016 10.53 56.16 ;
    END
  END o[86]
  PIN o[87]
    DIRECTION OUTPUT ;
    USE SIGNAL ;
    PORT
      LAYER M5 ;
        RECT  10.608 55.968 10.632 56.16 ;
    END
  END o[87]
  PIN o[88]
    DIRECTION OUTPUT ;
    USE SIGNAL ;
    PORT
      LAYER M3 ;
        RECT  10.728 56.016 10.746 56.16 ;
    END
  END o[88]
  PIN o[89]
    DIRECTION OUTPUT ;
    USE SIGNAL ;
    PORT
      LAYER M5 ;
        RECT  10.8 55.968 10.824 56.16 ;
    END
  END o[89]
  PIN o[8]
    DIRECTION OUTPUT ;
    USE SIGNAL ;
    PORT
      LAYER M3 ;
        RECT  2.988 56.016 3.006 56.16 ;
    END
  END o[8]
  PIN o[90]
    DIRECTION OUTPUT ;
    USE SIGNAL ;
    PORT
      LAYER M3 ;
        RECT  10.908 56.016 10.926 56.16 ;
    END
  END o[90]
  PIN o[91]
    DIRECTION OUTPUT ;
    USE SIGNAL ;
    PORT
      LAYER M5 ;
        RECT  10.992 55.968 11.016 56.16 ;
    END
  END o[91]
  PIN o[92]
    DIRECTION OUTPUT ;
    USE SIGNAL ;
    PORT
      LAYER M3 ;
        RECT  11.088 56.016 11.106 56.16 ;
    END
  END o[92]
  PIN o[93]
    DIRECTION OUTPUT ;
    USE SIGNAL ;
    PORT
      LAYER M5 ;
        RECT  11.184 55.968 11.208 56.16 ;
    END
  END o[93]
  PIN o[94]
    DIRECTION OUTPUT ;
    USE SIGNAL ;
    PORT
      LAYER M3 ;
        RECT  11.304 56.016 11.322 56.16 ;
    END
  END o[94]
  PIN o[95]
    DIRECTION OUTPUT ;
    USE SIGNAL ;
    PORT
      LAYER M5 ;
        RECT  11.376 55.968 11.4 56.16 ;
    END
  END o[95]
  PIN o[96]
    DIRECTION OUTPUT ;
    USE SIGNAL ;
    PORT
      LAYER M3 ;
        RECT  11.484 56.016 11.502 56.16 ;
    END
  END o[96]
  PIN o[97]
    DIRECTION OUTPUT ;
    USE SIGNAL ;
    PORT
      LAYER M5 ;
        RECT  11.568 55.968 11.592 56.16 ;
    END
  END o[97]
  PIN o[98]
    DIRECTION OUTPUT ;
    USE SIGNAL ;
    PORT
      LAYER M3 ;
        RECT  11.664 56.016 11.682 56.16 ;
    END
  END o[98]
  PIN o[99]
    DIRECTION OUTPUT ;
    USE SIGNAL ;
    PORT
      LAYER M5 ;
        RECT  11.76 55.968 11.784 56.16 ;
    END
  END o[99]
  PIN o[9]
    DIRECTION OUTPUT ;
    USE SIGNAL ;
    PORT
      LAYER M5 ;
        RECT  3.072 55.968 3.096 56.16 ;
    END
  END o[9]
  PIN rs
    DIRECTION INPUT ;
    USE SIGNAL ;
    PORT
      LAYER M4 ;
        RECT  55.968 41.04 56.16 41.064 ;
    END
    PORT
      LAYER M4 ;
        RECT  54.004 41.04 55.98 41.064 ;
    END
  END rs
  PIN VDD
    DIRECTION INOUT ;
    USE POWER ;
    PORT
      LAYER M5 ;
        RECT  53.892 2.151 54.012 54.009 ;
        RECT  51.192 2.151 51.312 54.009 ;
        RECT  48.492 2.151 48.612 54.009 ;
        RECT  45.792 2.151 45.912 54.009 ;
        RECT  43.092 2.151 43.212 54.009 ;
        RECT  40.392 2.151 40.512 54.009 ;
        RECT  37.692 2.151 37.812 54.009 ;
        RECT  34.992 2.151 35.112 54.009 ;
        RECT  32.292 2.151 32.412 54.009 ;
        RECT  29.592 2.151 29.712 54.009 ;
        RECT  26.892 2.151 27.012 54.009 ;
        RECT  24.192 2.151 24.312 54.009 ;
        RECT  21.492 2.151 21.612 54.009 ;
        RECT  18.792 2.151 18.912 54.009 ;
        RECT  16.092 2.151 16.212 54.009 ;
        RECT  13.392 2.151 13.512 54.009 ;
        RECT  10.692 2.151 10.812 54.009 ;
        RECT  7.992 2.151 8.112 54.009 ;
        RECT  5.292 2.151 5.412 54.009 ;
        RECT  2.592 2.151 2.712 54.009 ;
    END
  END VDD
  PIN VSS
    DIRECTION INOUT ;
    USE GROUND ;
    PORT
      LAYER M5 ;
        RECT  53.7 2.137 53.82 54.023 ;
        RECT  51 2.137 51.12 54.023 ;
        RECT  48.3 2.137 48.42 54.023 ;
        RECT  45.6 2.137 45.72 54.023 ;
        RECT  42.9 2.137 43.02 54.023 ;
        RECT  40.2 2.137 40.32 54.023 ;
        RECT  37.5 2.137 37.62 54.023 ;
        RECT  34.8 2.137 34.92 54.023 ;
        RECT  32.1 2.137 32.22 54.023 ;
        RECT  29.4 2.137 29.52 54.023 ;
        RECT  26.7 2.137 26.82 54.023 ;
        RECT  24 2.137 24.12 54.023 ;
        RECT  21.3 2.137 21.42 54.023 ;
        RECT  18.6 2.137 18.72 54.023 ;
        RECT  15.9 2.137 16.02 54.023 ;
        RECT  13.2 2.137 13.32 54.023 ;
        RECT  10.5 2.137 10.62 54.023 ;
        RECT  7.8 2.137 7.92 54.023 ;
        RECT  5.1 2.137 5.22 54.023 ;
        RECT  2.4 2.137 2.52 54.023 ;
    END
  END VSS
  # OT_OBS_CLOSED layer=M5 d_um=1.536 added=97
  OBS
    LAYER RVTN ;
     RECT  2.16 2.16 54 2.295 ;
     RECT  2.16 2.565 54 2.835 ;
     RECT  2.16 3.105 54 3.375 ;
     RECT  2.16 3.645 54 3.915 ;
     RECT  2.16 4.185 54 4.455 ;
     RECT  2.16 4.725 54 4.995 ;
     RECT  2.16 5.265 54 5.535 ;
     RECT  2.16 5.805 54 6.075 ;
     RECT  2.16 6.345 54 6.615 ;
     RECT  2.16 6.885 54 7.155 ;
     RECT  2.16 7.425 54 7.695 ;
     RECT  2.16 7.965 54 8.235 ;
     RECT  2.16 8.505 54 8.775 ;
     RECT  2.16 9.045 54 9.315 ;
     RECT  2.16 9.585 54 9.855 ;
     RECT  2.16 10.125 54 10.395 ;
     RECT  2.16 10.665 54 10.935 ;
     RECT  2.16 11.205 54 11.475 ;
     RECT  2.16 11.745 54 12.015 ;
     RECT  2.16 12.285 54 12.555 ;
     RECT  2.16 12.825 54 13.095 ;
     RECT  2.16 13.365 54 13.635 ;
     RECT  2.16 13.905 54 14.175 ;
     RECT  2.16 14.445 54 14.715 ;
     RECT  2.16 14.985 54 15.255 ;
     RECT  2.16 15.525 54 15.795 ;
     RECT  2.16 16.065 54 16.335 ;
     RECT  2.16 16.605 54 16.875 ;
     RECT  2.16 17.145 54 17.415 ;
     RECT  2.16 17.685 54 17.955 ;
     RECT  2.16 18.225 54 18.495 ;
     RECT  2.16 18.765 54 19.035 ;
     RECT  2.16 19.305 54 19.575 ;
     RECT  2.16 19.845 54 20.115 ;
     RECT  2.16 20.385 54 20.655 ;
     RECT  2.16 20.925 54 21.195 ;
     RECT  2.16 21.465 54 21.735 ;
     RECT  2.16 22.005 54 22.275 ;
     RECT  2.16 22.545 54 22.815 ;
     RECT  2.16 23.085 54 23.355 ;
     RECT  2.16 23.625 54 23.895 ;
     RECT  2.16 24.165 54 24.435 ;
     RECT  2.16 24.705 54 24.975 ;
     RECT  2.16 25.245 54 25.515 ;
     RECT  2.16 25.785 54 26.055 ;
     RECT  2.16 26.325 54 26.595 ;
     RECT  2.16 26.865 54 27.135 ;
     RECT  2.16 27.405 54 27.675 ;
     RECT  2.16 27.945 54 28.215 ;
     RECT  2.16 28.485 54 28.755 ;
     RECT  2.16 29.025 54 29.295 ;
     RECT  2.16 29.565 54 29.835 ;
     RECT  2.16 30.105 54 30.375 ;
     RECT  2.16 30.645 54 30.915 ;
     RECT  2.16 31.185 54 31.455 ;
     RECT  2.16 31.725 54 31.995 ;
     RECT  2.16 32.265 54 32.535 ;
     RECT  2.16 32.805 54 33.075 ;
     RECT  2.16 33.345 54 33.615 ;
     RECT  2.16 33.885 54 34.155 ;
     RECT  2.16 34.425 54 34.695 ;
     RECT  2.16 34.965 54 35.235 ;
     RECT  2.16 35.505 54 35.775 ;
     RECT  2.16 36.045 54 36.315 ;
     RECT  2.16 36.585 54 36.855 ;
     RECT  2.16 37.125 54 37.395 ;
     RECT  2.16 37.665 54 37.935 ;
     RECT  2.16 38.205 54 38.475 ;
     RECT  2.16 38.745 54 39.015 ;
     RECT  2.16 39.285 54 39.555 ;
     RECT  2.16 39.825 54 40.095 ;
     RECT  2.16 40.365 54 40.635 ;
     RECT  2.16 40.905 54 41.175 ;
     RECT  2.16 41.445 54 41.715 ;
     RECT  2.16 41.985 54 42.255 ;
     RECT  2.16 42.525 54 42.795 ;
     RECT  2.16 43.065 54 43.335 ;
     RECT  2.16 43.605 54 43.875 ;
     RECT  2.16 44.145 54 44.415 ;
     RECT  2.16 44.685 54 44.955 ;
     RECT  2.16 45.225 54 45.495 ;
     RECT  2.16 45.765 54 46.035 ;
     RECT  2.16 46.305 54 46.575 ;
     RECT  2.16 46.845 54 47.115 ;
     RECT  2.16 47.385 54 47.655 ;
     RECT  2.16 47.925 54 48.195 ;
     RECT  2.16 48.465 54 48.735 ;
     RECT  2.16 49.005 54 49.275 ;
     RECT  2.16 49.545 54 49.815 ;
     RECT  2.16 50.085 54 50.355 ;
     RECT  2.16 50.625 54 50.895 ;
     RECT  2.16 51.165 54 51.435 ;
     RECT  2.16 51.705 54 51.975 ;
     RECT  2.16 52.245 54 52.515 ;
     RECT  2.16 52.785 54 53.055 ;
     RECT  2.16 53.325 54 53.595 ;
     RECT  2.16 53.865 54 54 ;
    LAYER RVTP ;
     RECT  2.16 2.295 54 2.565 ;
     RECT  2.16 2.835 54 3.105 ;
     RECT  2.16 3.375 54 3.645 ;
     RECT  2.16 3.915 54 4.185 ;
     RECT  2.16 4.455 54 4.725 ;
     RECT  2.16 4.995 54 5.265 ;
     RECT  2.16 5.535 54 5.805 ;
     RECT  2.16 6.075 54 6.345 ;
     RECT  2.16 6.615 54 6.885 ;
     RECT  2.16 7.155 54 7.425 ;
     RECT  2.16 7.695 54 7.965 ;
     RECT  2.16 8.235 54 8.505 ;
     RECT  2.16 8.775 54 9.045 ;
     RECT  2.16 9.315 54 9.585 ;
     RECT  2.16 9.855 54 10.125 ;
     RECT  2.16 10.395 54 10.665 ;
     RECT  2.16 10.935 54 11.205 ;
     RECT  2.16 11.475 54 11.745 ;
     RECT  2.16 12.015 54 12.285 ;
     RECT  2.16 12.555 54 12.825 ;
     RECT  2.16 13.095 54 13.365 ;
     RECT  2.16 13.635 54 13.905 ;
     RECT  2.16 14.175 54 14.445 ;
     RECT  2.16 14.715 54 14.985 ;
     RECT  2.16 15.255 54 15.525 ;
     RECT  2.16 15.795 54 16.065 ;
     RECT  2.16 16.335 54 16.605 ;
     RECT  2.16 16.875 54 17.145 ;
     RECT  2.16 17.415 54 17.685 ;
     RECT  2.16 17.955 54 18.225 ;
     RECT  2.16 18.495 54 18.765 ;
     RECT  2.16 19.035 54 19.305 ;
     RECT  2.16 19.575 54 19.845 ;
     RECT  2.16 20.115 54 20.385 ;
     RECT  2.16 20.655 54 20.925 ;
     RECT  2.16 21.195 54 21.465 ;
     RECT  2.16 21.735 54 22.005 ;
     RECT  2.16 22.275 54 22.545 ;
     RECT  2.16 22.815 54 23.085 ;
     RECT  2.16 23.355 54 23.625 ;
     RECT  2.16 23.895 54 24.165 ;
     RECT  2.16 24.435 54 24.705 ;
     RECT  2.16 24.975 54 25.245 ;
     RECT  2.16 25.515 54 25.785 ;
     RECT  2.16 26.055 54 26.325 ;
     RECT  2.16 26.595 54 26.865 ;
     RECT  2.16 27.135 54 27.405 ;
     RECT  2.16 27.675 54 27.945 ;
     RECT  2.16 28.215 54 28.485 ;
     RECT  2.16 28.755 54 29.025 ;
     RECT  2.16 29.295 54 29.565 ;
     RECT  2.16 29.835 54 30.105 ;
     RECT  2.16 30.375 54 30.645 ;
     RECT  2.16 30.915 54 31.185 ;
     RECT  2.16 31.455 54 31.725 ;
     RECT  2.16 31.995 54 32.265 ;
     RECT  2.16 32.535 54 32.805 ;
     RECT  2.16 33.075 54 33.345 ;
     RECT  2.16 33.615 54 33.885 ;
     RECT  2.16 34.155 54 34.425 ;
     RECT  2.16 34.695 54 34.965 ;
     RECT  2.16 35.235 54 35.505 ;
     RECT  2.16 35.775 54 36.045 ;
     RECT  2.16 36.315 54 36.585 ;
     RECT  2.16 36.855 54 37.125 ;
     RECT  2.16 37.395 54 37.665 ;
     RECT  2.16 37.935 54 38.205 ;
     RECT  2.16 38.475 54 38.745 ;
     RECT  2.16 39.015 54 39.285 ;
     RECT  2.16 39.555 54 39.825 ;
     RECT  2.16 40.095 54 40.365 ;
     RECT  2.16 40.635 54 40.905 ;
     RECT  2.16 41.175 54 41.445 ;
     RECT  2.16 41.715 54 41.985 ;
     RECT  2.16 42.255 54 42.525 ;
     RECT  2.16 42.795 54 43.065 ;
     RECT  2.16 43.335 54 43.605 ;
     RECT  2.16 43.875 54 44.145 ;
     RECT  2.16 44.415 54 44.685 ;
     RECT  2.16 44.955 54 45.225 ;
     RECT  2.16 45.495 54 45.765 ;
     RECT  2.16 46.035 54 46.305 ;
     RECT  2.16 46.575 54 46.845 ;
     RECT  2.16 47.115 54 47.385 ;
     RECT  2.16 47.655 54 47.925 ;
     RECT  2.16 48.195 54 48.465 ;
     RECT  2.16 48.735 54 49.005 ;
     RECT  2.16 49.275 54 49.545 ;
     RECT  2.16 49.815 54 50.085 ;
     RECT  2.16 50.355 54 50.625 ;
     RECT  2.16 50.895 54 51.165 ;
     RECT  2.16 51.435 54 51.705 ;
     RECT  2.16 51.975 54 52.245 ;
     RECT  2.16 52.515 54 52.785 ;
     RECT  2.16 53.055 54 53.325 ;
     RECT  2.16 53.595 54 53.865 ;
    LAYER M1 ;
     RECT  2.16 2.151 54 54.009 ;
    LAYER M2 ;
     RECT  2.16 2.151 2.371 54.009 ;
     RECT  2.371 2.151 2.587 54.702 ;
     RECT  2.587 0.144 2.759 0.162 ;
     RECT  2.587 2.151 2.767 55.314 ;
     RECT  2.767 2.151 2.975 55.359 ;
     RECT  2.975 2.151 3.227 55.314 ;
     RECT  3.227 55.296 3.739 55.314 ;
     RECT  3.227 2.151 3.919 54.009 ;
     RECT  3.919 1.656 4.055 54.009 ;
     RECT  3.739 55.296 4.235 55.44 ;
     RECT  4.423 55.998 4.523 56.088 ;
     RECT  4.523 55.998 4.559 56.016 ;
     RECT  4.055 2.106 4.999 54.009 ;
     RECT  4.459 0.144 5.135 0.162 ;
     RECT  4.999 2.106 5.287 54.09 ;
     RECT  5.287 1.728 5.459 54.702 ;
     RECT  5.459 1.728 6.215 54.009 ;
     RECT  6.215 2.151 6.259 54.009 ;
     RECT  6.259 2.151 6.439 54.702 ;
     RECT  6.439 2.151 7.079 55.314 ;
     RECT  7.079 2.151 7.627 54.702 ;
     RECT  7.807 0.144 7.979 0.162 ;
     RECT  7.627 1.728 8.383 54.702 ;
     RECT  8.383 1.728 8.483 55.314 ;
     RECT  8.483 2.151 8.879 55.314 ;
     RECT  8.879 2.151 9.347 54.702 ;
     RECT  9.355 0.144 9.419 0.162 ;
     RECT  9.347 2.151 10.111 54.009 ;
     RECT  10.111 2.151 10.211 54.702 ;
     RECT  10.211 2.151 10.327 54.09 ;
     RECT  10.255 0.216 10.435 0.234 ;
     RECT  10.327 1.728 10.535 54.09 ;
     RECT  10.435 0.144 10.751 0.234 ;
     RECT  10.535 1.728 11.867 54.009 ;
     RECT  11.867 2.151 12.235 54.009 ;
     RECT  12.235 2.151 12.443 54.702 ;
     RECT  10.751 0.144 12.479 0.162 ;
     RECT  12.451 55.296 12.947 55.314 ;
     RECT  12.443 2.151 13.207 54.009 ;
     RECT  13.207 2.151 13.559 54.702 ;
     RECT  13.559 2.151 13.603 54.009 ;
     RECT  13.603 1.728 13.703 54.009 ;
     RECT  13.207 0.144 13.883 0.162 ;
     RECT  14.179 55.296 14.315 55.314 ;
     RECT  13.703 2.106 14.855 54.009 ;
     RECT  13.999 0.576 14.971 0.594 ;
     RECT  14.971 0.306 14.999 0.594 ;
     RECT  14.999 0.306 15.079 0.324 ;
     RECT  15.079 0.144 15.179 0.324 ;
     RECT  14.855 2.151 15.547 54.009 ;
     RECT  15.547 2.151 15.619 54.702 ;
     RECT  15.619 2.106 16.259 54.702 ;
     RECT  15.179 0.144 16.475 0.162 ;
     RECT  16.259 2.151 16.907 54.702 ;
     RECT  16.907 2.151 16.943 54.594 ;
     RECT  16.943 2.151 17.095 54.009 ;
     RECT  17.095 1.728 17.663 54.009 ;
     RECT  17.419 0.144 18.095 0.162 ;
     RECT  17.663 2.151 18.247 54.009 ;
     RECT  18.247 2.151 19.391 54.702 ;
     RECT  19.391 2.151 19.399 54.009 ;
     RECT  19.399 1.728 20.147 54.009 ;
     RECT  20.147 2.151 20.587 54.009 ;
     RECT  19.399 55.296 20.587 55.314 ;
     RECT  20.623 0.216 20.767 0.234 ;
     RECT  20.587 2.151 20.867 55.314 ;
     RECT  20.767 0.144 20.975 0.234 ;
     RECT  20.867 2.151 21.479 54.702 ;
     RECT  21.479 2.151 21.551 54.234 ;
     RECT  20.975 0.144 21.659 0.162 ;
     RECT  21.551 2.151 22.135 54.009 ;
     RECT  22.135 1.728 22.307 54.009 ;
     RECT  22.307 2.151 22.315 54.009 ;
     RECT  22.315 2.151 23.287 54.702 ;
     RECT  23.287 2.151 23.315 55.314 ;
     RECT  23.315 55.296 23.675 55.314 ;
     RECT  22.711 0.576 23.683 0.594 ;
     RECT  23.683 0.144 23.711 0.594 ;
     RECT  23.315 2.151 24.043 54.009 ;
     RECT  24.043 2.151 24.259 54.126 ;
     RECT  23.711 0.144 24.359 0.162 ;
     RECT  24.259 2.151 24.791 54.702 ;
     RECT  24.791 2.151 24.835 54.009 ;
     RECT  25.195 0.144 25.295 0.162 ;
     RECT  24.835 1.728 25.799 54.009 ;
     RECT  25.799 2.151 26.671 54.009 ;
     RECT  26.671 2.151 26.771 54.09 ;
     RECT  26.771 2.151 27.535 54.009 ;
     RECT  26.383 0.144 28.247 0.162 ;
     RECT  27.535 2.151 28.571 54.054 ;
     RECT  28.571 2.151 29.479 54.009 ;
     RECT  29.479 2.151 29.651 54.09 ;
     RECT  29.659 0.144 29.831 0.162 ;
     RECT  29.839 0.216 29.939 0.234 ;
     RECT  29.651 2.151 30.451 54.009 ;
     RECT  30.451 2.151 30.767 54.054 ;
     RECT  30.767 2.151 31.207 54.009 ;
     RECT  31.207 1.728 32.035 54.009 ;
     RECT  32.035 1.728 32.207 54.09 ;
     RECT  32.207 1.728 33.151 54.009 ;
     RECT  33.331 0.144 33.467 0.162 ;
     RECT  33.151 1.728 33.467 54.702 ;
     RECT  33.467 1.728 34.123 54.009 ;
     RECT  34.123 1.692 34.223 54.009 ;
     RECT  34.223 1.728 34.879 54.009 ;
     RECT  34.879 1.728 34.979 54.09 ;
     RECT  34.483 0.144 35.555 0.162 ;
     RECT  36.031 55.386 36.167 55.404 ;
     RECT  34.979 1.728 36.707 54.009 ;
     RECT  36.391 0.144 36.743 0.162 ;
     RECT  36.707 2.106 37.579 54.009 ;
     RECT  37.579 1.728 37.679 54.09 ;
     RECT  38.371 0.144 38.615 0.162 ;
     RECT  38.767 1.152 38.903 1.17 ;
     RECT  37.679 2.151 39.047 54.09 ;
     RECT  39.047 2.151 39.271 54.009 ;
     RECT  38.767 55.296 39.515 55.314 ;
     RECT  39.919 1.152 40.055 1.17 ;
     RECT  39.271 2.106 40.135 54.009 ;
     RECT  40.135 2.106 40.315 54.09 ;
     RECT  40.315 2.07 40.343 54.09 ;
     RECT  40.495 0.144 40.595 0.162 ;
     RECT  40.343 2.07 40.675 54.009 ;
     RECT  40.675 1.728 41.071 54.009 ;
     RECT  41.071 1.728 41.351 54.702 ;
     RECT  41.351 1.728 41.459 54.009 ;
     RECT  42.619 55.26 42.755 55.278 ;
     RECT  41.459 2.151 42.799 54.009 ;
     RECT  43.015 55.998 43.051 56.016 ;
     RECT  43.051 55.998 43.151 56.088 ;
     RECT  43.015 0.144 43.295 0.162 ;
     RECT  42.799 2.151 43.475 54.738 ;
     RECT  43.475 2.151 43.771 54.702 ;
     RECT  43.771 1.728 43.907 54.702 ;
     RECT  43.907 2.151 44.267 54.702 ;
     RECT  44.267 2.151 44.743 54.009 ;
     RECT  44.347 55.296 45.239 55.314 ;
     RECT  44.743 1.728 45.715 54.009 ;
     RECT  45.715 0.144 46.319 0.162 ;
     RECT  45.715 1.728 46.319 54.702 ;
     RECT  46.319 2.151 46.687 54.702 ;
     RECT  46.687 2.151 46.823 55.314 ;
     RECT  46.823 2.151 47.147 54.702 ;
     RECT  47.147 2.151 48.199 54.009 ;
     RECT  48.199 2.151 48.443 54.09 ;
     RECT  49.747 1.152 49.783 1.17 ;
     RECT  48.443 2.151 49.783 54.009 ;
     RECT  49.783 1.152 49.847 54.009 ;
     RECT  49.847 1.728 49.963 54.009 ;
     RECT  49.387 55.296 49.963 55.314 ;
     RECT  49.747 0.144 49.991 0.162 ;
     RECT  49.963 1.728 50.935 55.314 ;
     RECT  50.935 1.728 51.179 55.404 ;
     RECT  51.179 1.728 51.683 55.314 ;
     RECT  51.683 1.728 52.151 54.702 ;
     RECT  52.151 1.728 52.763 54.009 ;
     RECT  52.763 2.151 53.059 54.009 ;
     RECT  52.663 0.144 53.159 0.162 ;
     RECT  53.059 2.151 53.159 54.702 ;
     RECT  53.419 56.07 53.455 56.088 ;
     RECT  53.455 55.998 53.555 56.088 ;
     RECT  53.159 2.151 54 54.009 ;
     RECT  54 2.268 54.012 53.739 ;
     RECT  54.012 2.268 54.059 3.204 ;
     RECT  54.012 8.172 54.059 8.19 ;
     RECT  54.012 11.826 54.059 12.384 ;
     RECT  54.012 19.818 54.059 21.024 ;
     RECT  54.012 25.182 54.059 25.344 ;
     RECT  54.012 28.422 54.059 29.556 ;
     RECT  54.012 50.796 54.059 50.814 ;
     RECT  54.012 5.31 54.095 5.328 ;
     RECT  54.012 13.446 54.095 13.464 ;
     RECT  54.059 20.358 54.095 21.024 ;
     RECT  54.012 27.306 54.095 27.396 ;
     RECT  54.059 28.422 54.095 28.746 ;
     RECT  54.059 29.538 54.095 29.556 ;
     RECT  54.012 42.732 54.095 42.75 ;
     RECT  54.059 12.024 54.131 12.384 ;
     RECT  54.095 20.358 54.131 20.718 ;
     RECT  54.059 25.326 54.131 25.344 ;
     RECT  54.095 28.656 54.131 28.746 ;
     RECT  54.012 32.976 54.131 33.066 ;
     RECT  54.012 34.938 54.131 34.956 ;
     RECT  54.012 10.251 54.167 10.764 ;
     RECT  54.012 23.67 54.167 23.688 ;
     RECT  54.012 7.236 54.203 7.254 ;
     RECT  54.012 18.738 54.203 18.756 ;
     RECT  54.059 2.268 54.239 3.132 ;
     RECT  54.167 10.251 54.239 10.35 ;
     RECT  54.239 3.114 54.275 3.132 ;
     RECT  54.239 10.251 54.275 10.269 ;
     RECT  54.239 2.268 54.311 2.286 ;
     RECT  54.131 12.024 54.311 12.042 ;
     RECT  54.012 41.148 54.743 41.166 ;
    LAYER M3 ;
     RECT  2.214 0.108 2.376 0.144 ;
     RECT  2.394 0.108 2.592 0.144 ;
     RECT  2.61 0.108 2.772 0.144 ;
     RECT  2.79 0.108 2.988 0.144 ;
     RECT  3.006 0.108 3.168 0.144 ;
     RECT  3.186 0.108 3.348 0.144 ;
     RECT  3.366 0.108 3.564 0.144 ;
     RECT  3.582 0.108 3.744 0.144 ;
     RECT  3.762 0.108 3.924 0.144 ;
     RECT  3.942 0.108 4.14 0.144 ;
     RECT  4.158 0.108 4.32 0.144 ;
     RECT  4.338 0.108 4.536 0.144 ;
     RECT  4.554 0.108 4.716 0.144 ;
     RECT  4.734 0.108 4.896 0.144 ;
     RECT  4.914 0.108 5.112 0.144 ;
     RECT  5.13 0.108 5.292 0.144 ;
     RECT  5.31 0.108 5.472 0.144 ;
     RECT  5.49 0.108 5.688 0.144 ;
     RECT  5.706 0.108 5.868 0.144 ;
     RECT  5.886 0.108 6.084 0.144 ;
     RECT  6.102 0.108 6.264 0.144 ;
     RECT  6.282 0.108 6.444 0.144 ;
     RECT  6.462 0.108 6.66 0.144 ;
     RECT  6.678 0.108 6.84 0.144 ;
     RECT  6.858 0.108 7.02 0.144 ;
     RECT  7.038 0.108 7.236 0.144 ;
     RECT  7.254 0.108 7.416 0.144 ;
     RECT  7.434 0.108 7.632 0.144 ;
     RECT  7.65 0.108 7.812 0.144 ;
     RECT  7.83 0.108 7.992 0.144 ;
     RECT  8.01 0.108 8.208 0.144 ;
     RECT  8.226 0.108 8.388 0.144 ;
     RECT  8.406 0.108 8.568 0.144 ;
     RECT  8.586 0.108 8.784 0.144 ;
     RECT  8.802 0.108 8.964 0.144 ;
     RECT  8.982 0.108 9.18 0.144 ;
     RECT  9.198 0.108 9.36 0.144 ;
     RECT  9.378 0.108 9.54 0.144 ;
     RECT  9.558 0.108 9.756 0.144 ;
     RECT  9.774 0.108 9.936 0.144 ;
     RECT  9.954 0.108 10.116 0.144 ;
     RECT  10.134 0.108 10.332 0.144 ;
     RECT  10.35 0.108 10.512 0.144 ;
     RECT  10.53 0.108 10.728 0.144 ;
     RECT  10.746 0.108 10.908 0.144 ;
     RECT  10.926 0.108 11.088 0.144 ;
     RECT  11.106 0.108 11.304 0.144 ;
     RECT  11.322 0.108 11.484 0.144 ;
     RECT  11.502 0.108 11.664 0.144 ;
     RECT  11.682 0.108 11.88 0.144 ;
     RECT  11.898 0.108 12.06 0.144 ;
     RECT  12.078 0.108 12.24 0.144 ;
     RECT  12.258 0.108 12.456 0.144 ;
     RECT  12.474 0.108 12.636 0.144 ;
     RECT  12.654 0.108 12.852 0.144 ;
     RECT  12.87 0.108 13.032 0.144 ;
     RECT  13.05 0.108 13.212 0.144 ;
     RECT  13.23 0.108 13.428 0.144 ;
     RECT  13.446 0.108 13.608 0.144 ;
     RECT  13.626 0.108 13.788 0.144 ;
     RECT  13.806 0.108 14.004 0.144 ;
     RECT  14.022 0.108 14.184 0.144 ;
     RECT  14.202 0.108 14.4 0.144 ;
     RECT  14.418 0.108 14.58 0.144 ;
     RECT  14.598 0.108 14.76 0.144 ;
     RECT  14.778 0.108 14.976 0.144 ;
     RECT  14.994 0.108 15.156 0.144 ;
     RECT  15.174 0.108 15.336 0.144 ;
     RECT  15.354 0.108 15.552 0.144 ;
     RECT  15.57 0.108 15.732 0.144 ;
     RECT  15.75 0.108 15.948 0.144 ;
     RECT  15.966 0.108 16.128 0.144 ;
     RECT  16.146 0.108 16.308 0.144 ;
     RECT  16.326 0.108 16.524 0.144 ;
     RECT  16.542 0.108 16.704 0.144 ;
     RECT  16.722 0.108 16.884 0.144 ;
     RECT  16.902 0.108 17.1 0.144 ;
     RECT  17.118 0.108 17.28 0.144 ;
     RECT  17.298 0.108 17.496 0.144 ;
     RECT  17.514 0.108 17.676 0.144 ;
     RECT  17.694 0.108 17.856 0.144 ;
     RECT  17.874 0.108 18.072 0.144 ;
     RECT  18.09 0.108 18.252 0.144 ;
     RECT  18.27 0.108 18.432 0.144 ;
     RECT  18.45 0.108 18.648 0.144 ;
     RECT  18.666 0.108 18.828 0.144 ;
     RECT  18.846 0.108 19.044 0.144 ;
     RECT  19.062 0.108 19.224 0.144 ;
     RECT  19.242 0.108 19.404 0.144 ;
     RECT  19.422 0.108 19.62 0.144 ;
     RECT  19.638 0.108 19.8 0.144 ;
     RECT  19.818 0.108 19.98 0.144 ;
     RECT  19.998 0.108 20.196 0.144 ;
     RECT  20.214 0.108 20.376 0.144 ;
     RECT  20.394 0.108 20.592 0.144 ;
     RECT  20.61 0.108 20.772 0.144 ;
     RECT  20.79 0.108 20.952 0.144 ;
     RECT  20.97 0.108 21.168 0.144 ;
     RECT  21.186 0.108 21.348 0.144 ;
     RECT  21.366 0.108 21.528 0.144 ;
     RECT  21.546 0.108 21.744 0.144 ;
     RECT  21.762 0.108 21.924 0.144 ;
     RECT  21.942 0.108 22.14 0.144 ;
     RECT  22.158 0.108 22.32 0.144 ;
     RECT  22.338 0.108 22.5 0.144 ;
     RECT  22.518 0.108 22.716 0.144 ;
     RECT  22.734 0.108 22.896 0.144 ;
     RECT  22.914 0.108 23.076 0.144 ;
     RECT  23.094 0.108 23.292 0.144 ;
     RECT  23.31 0.108 23.472 0.144 ;
     RECT  23.49 0.108 23.688 0.144 ;
     RECT  23.706 0.108 23.868 0.144 ;
     RECT  23.886 0.108 24.048 0.144 ;
     RECT  24.066 0.108 24.264 0.144 ;
     RECT  24.282 0.108 24.444 0.144 ;
     RECT  24.462 0.108 24.624 0.144 ;
     RECT  24.642 0.108 24.84 0.144 ;
     RECT  24.858 0.108 25.02 0.144 ;
     RECT  25.038 0.108 25.2 0.144 ;
     RECT  25.218 0.108 25.416 0.144 ;
     RECT  25.434 0.108 25.596 0.144 ;
     RECT  25.614 0.108 25.812 0.144 ;
     RECT  25.83 0.108 25.992 0.144 ;
     RECT  26.01 0.108 26.172 0.144 ;
     RECT  26.19 0.108 26.388 0.144 ;
     RECT  26.406 0.108 26.568 0.144 ;
     RECT  26.586 0.108 26.748 0.144 ;
     RECT  26.766 0.108 26.964 0.144 ;
     RECT  26.982 0.108 27.144 0.144 ;
     RECT  27.162 0.108 27.36 0.144 ;
     RECT  27.378 0.108 27.54 0.144 ;
     RECT  27.558 0.108 27.72 0.144 ;
     RECT  27.738 0.108 27.936 0.144 ;
     RECT  27.954 0.108 28.116 0.144 ;
     RECT  28.134 0.108 28.296 0.144 ;
     RECT  28.314 0.108 28.512 0.144 ;
     RECT  28.53 0.108 28.692 0.144 ;
     RECT  28.71 0.108 28.908 0.144 ;
     RECT  28.926 0.108 29.088 0.144 ;
     RECT  29.106 0.108 29.268 0.144 ;
     RECT  29.286 0.108 29.484 0.144 ;
     RECT  29.502 0.108 29.664 0.144 ;
     RECT  29.682 0.108 29.844 0.144 ;
     RECT  29.862 0.108 30.06 0.144 ;
     RECT  30.078 0.108 30.24 0.144 ;
     RECT  30.258 0.108 30.456 0.144 ;
     RECT  30.474 0.108 30.636 0.144 ;
     RECT  30.654 0.108 30.816 0.144 ;
     RECT  30.834 0.108 31.032 0.144 ;
     RECT  31.05 0.108 31.212 0.144 ;
     RECT  31.23 0.108 31.392 0.144 ;
     RECT  31.41 0.108 31.608 0.144 ;
     RECT  31.626 0.108 31.788 0.144 ;
     RECT  31.806 0.108 32.004 0.144 ;
     RECT  32.022 0.108 32.184 0.144 ;
     RECT  32.202 0.108 32.364 0.144 ;
     RECT  32.382 0.108 32.58 0.144 ;
     RECT  32.598 0.108 32.76 0.144 ;
     RECT  32.778 0.108 32.94 0.144 ;
     RECT  32.958 0.108 33.156 0.144 ;
     RECT  33.174 0.108 33.336 0.144 ;
     RECT  33.354 0.108 33.552 0.144 ;
     RECT  33.57 0.108 33.732 0.144 ;
     RECT  33.75 0.108 33.912 0.144 ;
     RECT  33.93 0.108 34.128 0.144 ;
     RECT  34.146 0.108 34.308 0.144 ;
     RECT  34.326 0.108 34.488 0.144 ;
     RECT  34.506 0.108 34.704 0.144 ;
     RECT  34.722 0.108 34.884 0.144 ;
     RECT  34.902 0.108 35.1 0.144 ;
     RECT  35.118 0.108 35.28 0.144 ;
     RECT  35.298 0.108 35.46 0.144 ;
     RECT  35.478 0.108 35.676 0.144 ;
     RECT  35.694 0.108 35.856 0.144 ;
     RECT  35.874 0.108 36.036 0.144 ;
     RECT  36.054 0.108 36.252 0.144 ;
     RECT  36.27 0.108 36.432 0.144 ;
     RECT  36.45 0.108 36.648 0.144 ;
     RECT  36.666 0.108 36.828 0.144 ;
     RECT  36.846 0.108 37.008 0.144 ;
     RECT  37.026 0.108 37.224 0.144 ;
     RECT  37.242 0.108 37.404 0.144 ;
     RECT  37.422 0.108 37.584 0.144 ;
     RECT  37.602 0.108 37.8 0.144 ;
     RECT  37.818 0.108 37.98 0.144 ;
     RECT  37.998 0.108 38.16 0.144 ;
     RECT  38.178 0.108 38.376 0.144 ;
     RECT  38.394 0.108 38.556 0.144 ;
     RECT  38.574 0.108 38.772 0.144 ;
     RECT  38.79 0.108 38.952 0.144 ;
     RECT  38.97 0.108 39.132 0.144 ;
     RECT  39.15 0.108 39.348 0.144 ;
     RECT  39.366 0.108 39.528 0.144 ;
     RECT  39.546 0.108 39.708 0.144 ;
     RECT  39.726 0.108 39.924 0.144 ;
     RECT  39.942 0.108 40.104 0.144 ;
     RECT  40.122 0.108 40.32 0.144 ;
     RECT  40.338 0.108 40.5 0.144 ;
     RECT  40.518 0.108 40.68 0.144 ;
     RECT  40.698 0.108 40.896 0.144 ;
     RECT  40.914 0.108 41.076 0.144 ;
     RECT  41.094 0.108 41.256 0.144 ;
     RECT  41.274 0.108 41.472 0.144 ;
     RECT  41.49 0.108 41.652 0.144 ;
     RECT  41.67 0.108 41.868 0.144 ;
     RECT  41.886 0.108 42.048 0.144 ;
     RECT  42.066 0.108 42.228 0.144 ;
     RECT  42.246 0.108 42.444 0.144 ;
     RECT  42.462 0.108 42.624 0.144 ;
     RECT  42.642 0.108 42.804 0.144 ;
     RECT  42.822 0.108 43.02 0.144 ;
     RECT  43.038 0.108 43.2 0.144 ;
     RECT  43.218 0.108 43.416 0.144 ;
     RECT  43.434 0.108 43.596 0.144 ;
     RECT  43.614 0.108 43.776 0.144 ;
     RECT  43.794 0.108 43.992 0.144 ;
     RECT  44.01 0.108 44.172 0.144 ;
     RECT  44.19 0.108 44.352 0.144 ;
     RECT  44.37 0.108 44.568 0.144 ;
     RECT  44.586 0.108 44.748 0.144 ;
     RECT  44.766 0.108 44.964 0.144 ;
     RECT  44.982 0.108 45.144 0.144 ;
     RECT  45.162 0.108 45.324 0.144 ;
     RECT  45.342 0.108 45.54 0.144 ;
     RECT  45.558 0.108 45.72 0.144 ;
     RECT  45.738 0.108 45.9 0.144 ;
     RECT  45.918 0.108 46.116 0.144 ;
     RECT  46.134 0.108 46.296 0.144 ;
     RECT  46.314 0.108 46.512 0.144 ;
     RECT  46.53 0.108 46.692 0.144 ;
     RECT  46.71 0.108 46.872 0.144 ;
     RECT  46.89 0.108 47.088 0.144 ;
     RECT  47.106 0.108 47.268 0.144 ;
     RECT  47.286 0.108 47.448 0.144 ;
     RECT  47.466 0.108 47.664 0.144 ;
     RECT  47.682 0.108 47.844 0.144 ;
     RECT  47.862 0.108 48.06 0.144 ;
     RECT  48.078 0.108 48.24 0.144 ;
     RECT  48.258 0.108 48.42 0.144 ;
     RECT  48.438 0.108 48.636 0.144 ;
     RECT  48.654 0.108 48.816 0.144 ;
     RECT  48.834 0.108 48.996 0.144 ;
     RECT  49.014 0.108 49.212 0.144 ;
     RECT  49.23 0.108 49.392 0.144 ;
     RECT  49.41 0.108 49.608 0.144 ;
     RECT  49.626 0.108 49.788 0.144 ;
     RECT  49.806 0.108 49.968 0.144 ;
     RECT  49.986 0.108 50.184 0.144 ;
     RECT  50.202 0.108 50.364 0.144 ;
     RECT  50.382 0.108 50.544 0.144 ;
     RECT  50.562 0.108 50.76 0.144 ;
     RECT  50.778 0.108 50.94 0.144 ;
     RECT  50.958 0.108 51.12 0.144 ;
     RECT  51.138 0.108 51.336 0.144 ;
     RECT  51.354 0.108 51.516 0.144 ;
     RECT  51.534 0.108 51.732 0.144 ;
     RECT  51.75 0.108 51.912 0.144 ;
     RECT  51.93 0.108 52.092 0.144 ;
     RECT  52.11 0.108 52.308 0.144 ;
     RECT  52.326 0.108 52.488 0.144 ;
     RECT  52.506 0.108 52.668 0.144 ;
     RECT  52.686 0.108 52.884 0.144 ;
     RECT  52.902 0.108 53.064 0.144 ;
     RECT  53.082 0.108 53.28 0.144 ;
     RECT  53.298 0.108 53.46 0.144 ;
     RECT  53.478 0.108 53.64 0.144 ;
     RECT  53.658 0.108 53.856 0.144 ;
     RECT  2.196 0.144 53.874 0.173 ;
     RECT  2.196 0.173 53.658 0.269 ;
     RECT  2.196 0.269 48.834 0.317 ;
     RECT  19.224 0.317 48.834 0.557 ;
     RECT  2.196 0.317 18.45 1.147 ;
     RECT  19.224 0.557 48.078 1.147 ;
     RECT  48.816 0.557 48.834 1.723 ;
     RECT  49.608 0.269 53.658 1.723 ;
     RECT  2.196 1.147 48.078 2.011 ;
     RECT  48.816 1.723 54.09 2.011 ;
     RECT  2.196 2.011 54.09 2.263 ;
     RECT  2.196 2.263 54.306 2.525 ;
     RECT  2.304 2.525 54.306 5.225 ;
     RECT  2.376 5.225 54.306 6.809 ;
     RECT  2.415 6.809 54.306 12.047 ;
     RECT  2.415 12.047 54.198 18.761 ;
     RECT  2.415 18.761 54.162 23.693 ;
     RECT  2.415 23.693 54.126 30.991 ;
     RECT  2.196 30.991 54.126 34.961 ;
     RECT  2.196 34.961 54.09 41.035 ;
     RECT  2.196 41.035 54.738 41.171 ;
     RECT  2.196 41.171 54.09 42.755 ;
     RECT  2.196 42.755 53.997 50.791 ;
     RECT  2.196 50.791 54.054 55.325 ;
     RECT  2.196 55.325 53.874 56.016 ;
     RECT  2.214 56.016 2.376 56.028 ;
     RECT  2.394 56.016 2.592 56.028 ;
     RECT  2.61 56.016 2.772 56.028 ;
     RECT  2.79 56.016 2.988 56.028 ;
     RECT  3.006 56.016 3.168 56.028 ;
     RECT  3.186 56.016 3.348 56.028 ;
     RECT  3.366 56.016 3.564 56.028 ;
     RECT  3.582 56.016 3.744 56.028 ;
     RECT  3.762 56.016 3.924 56.028 ;
     RECT  3.942 56.016 4.14 56.028 ;
     RECT  4.158 56.016 4.32 56.028 ;
     RECT  4.338 56.016 4.536 56.028 ;
     RECT  4.554 56.016 4.716 56.028 ;
     RECT  4.734 56.016 4.896 56.028 ;
     RECT  4.914 56.016 5.112 56.028 ;
     RECT  5.13 56.016 5.292 56.028 ;
     RECT  5.31 56.016 5.472 56.028 ;
     RECT  5.49 56.016 5.688 56.028 ;
     RECT  5.706 56.016 5.868 56.028 ;
     RECT  5.886 56.016 6.084 56.028 ;
     RECT  6.102 56.016 6.264 56.028 ;
     RECT  6.282 56.016 6.444 56.028 ;
     RECT  6.462 56.016 6.66 56.028 ;
     RECT  6.678 56.016 6.84 56.028 ;
     RECT  6.858 56.016 7.02 56.028 ;
     RECT  7.038 56.016 7.236 56.028 ;
     RECT  7.254 56.016 7.416 56.028 ;
     RECT  7.434 56.016 7.632 56.028 ;
     RECT  7.65 56.016 7.812 56.028 ;
     RECT  7.83 56.016 7.992 56.028 ;
     RECT  8.01 56.016 8.208 56.028 ;
     RECT  8.226 56.016 8.388 56.028 ;
     RECT  8.406 56.016 8.568 56.028 ;
     RECT  8.586 56.016 8.784 56.028 ;
     RECT  8.802 56.016 8.964 56.028 ;
     RECT  8.982 56.016 9.18 56.028 ;
     RECT  9.198 56.016 9.36 56.028 ;
     RECT  9.378 56.016 9.54 56.028 ;
     RECT  9.558 56.016 9.756 56.028 ;
     RECT  9.774 56.016 9.936 56.028 ;
     RECT  9.954 56.016 10.116 56.028 ;
     RECT  10.134 56.016 10.332 56.028 ;
     RECT  10.35 56.016 10.512 56.028 ;
     RECT  10.53 56.016 10.728 56.028 ;
     RECT  10.746 56.016 10.908 56.028 ;
     RECT  10.926 56.016 11.088 56.028 ;
     RECT  11.106 56.016 11.304 56.028 ;
     RECT  11.322 56.016 11.484 56.028 ;
     RECT  11.502 56.016 11.664 56.028 ;
     RECT  11.682 56.016 11.88 56.028 ;
     RECT  11.898 56.016 12.06 56.028 ;
     RECT  12.078 56.016 12.24 56.028 ;
     RECT  12.258 56.016 12.456 56.028 ;
     RECT  12.474 56.016 12.636 56.028 ;
     RECT  12.654 56.016 12.852 56.028 ;
     RECT  12.87 56.016 13.032 56.028 ;
     RECT  13.05 56.016 13.212 56.028 ;
     RECT  13.23 56.016 13.428 56.028 ;
     RECT  13.446 56.016 13.608 56.028 ;
     RECT  13.626 56.016 13.788 56.028 ;
     RECT  13.806 56.016 14.004 56.028 ;
     RECT  14.022 56.016 14.184 56.028 ;
     RECT  14.202 56.016 14.4 56.028 ;
     RECT  14.418 56.016 14.58 56.028 ;
     RECT  14.598 56.016 14.76 56.028 ;
     RECT  14.778 56.016 14.976 56.028 ;
     RECT  14.994 56.016 15.156 56.028 ;
     RECT  15.174 56.016 15.336 56.028 ;
     RECT  15.354 56.016 15.552 56.028 ;
     RECT  15.57 56.016 15.732 56.028 ;
     RECT  15.75 56.016 15.948 56.028 ;
     RECT  15.966 56.016 16.128 56.028 ;
     RECT  16.146 56.016 16.308 56.028 ;
     RECT  16.326 56.016 16.524 56.028 ;
     RECT  16.542 56.016 16.704 56.028 ;
     RECT  16.722 56.016 16.884 56.028 ;
     RECT  16.902 56.016 17.1 56.028 ;
     RECT  17.118 56.016 17.28 56.028 ;
     RECT  17.298 56.016 17.496 56.028 ;
     RECT  17.514 56.016 17.676 56.028 ;
     RECT  17.694 56.016 17.856 56.028 ;
     RECT  17.874 56.016 18.072 56.028 ;
     RECT  18.09 56.016 18.252 56.028 ;
     RECT  18.27 56.016 18.432 56.028 ;
     RECT  18.45 56.016 18.648 56.028 ;
     RECT  18.666 56.016 18.828 56.028 ;
     RECT  18.846 56.016 19.044 56.028 ;
     RECT  19.062 56.016 19.224 56.028 ;
     RECT  19.242 56.016 19.404 56.028 ;
     RECT  19.422 56.016 19.62 56.028 ;
     RECT  19.638 56.016 19.8 56.028 ;
     RECT  19.818 56.016 19.98 56.028 ;
     RECT  19.998 56.016 20.196 56.028 ;
     RECT  20.214 56.016 20.376 56.028 ;
     RECT  20.394 56.016 20.592 56.028 ;
     RECT  20.61 56.016 20.772 56.028 ;
     RECT  20.79 56.016 20.952 56.028 ;
     RECT  20.97 56.016 21.168 56.028 ;
     RECT  21.186 56.016 21.348 56.028 ;
     RECT  21.366 56.016 21.528 56.028 ;
     RECT  21.546 56.016 21.744 56.028 ;
     RECT  21.762 56.016 21.924 56.028 ;
     RECT  21.942 56.016 22.14 56.028 ;
     RECT  22.158 56.016 22.32 56.028 ;
     RECT  22.338 56.016 22.5 56.028 ;
     RECT  22.518 56.016 22.716 56.028 ;
     RECT  22.734 56.016 22.896 56.028 ;
     RECT  22.914 56.016 23.076 56.028 ;
     RECT  23.094 56.016 23.292 56.028 ;
     RECT  23.31 56.016 23.472 56.028 ;
     RECT  23.49 56.016 23.688 56.028 ;
     RECT  23.706 56.016 23.868 56.028 ;
     RECT  23.886 56.016 24.048 56.028 ;
     RECT  24.066 56.016 24.264 56.028 ;
     RECT  24.282 56.016 24.444 56.028 ;
     RECT  24.462 56.016 24.624 56.028 ;
     RECT  24.642 56.016 24.84 56.028 ;
     RECT  24.858 56.016 25.02 56.028 ;
     RECT  25.038 56.016 25.2 56.028 ;
     RECT  25.218 56.016 25.416 56.028 ;
     RECT  25.434 56.016 25.596 56.028 ;
     RECT  25.614 56.016 25.812 56.028 ;
     RECT  25.83 56.016 25.992 56.028 ;
     RECT  26.01 56.016 26.172 56.028 ;
     RECT  26.19 56.016 26.388 56.028 ;
     RECT  26.406 56.016 26.568 56.028 ;
     RECT  26.586 56.016 26.748 56.028 ;
     RECT  26.766 56.016 26.964 56.028 ;
     RECT  26.982 56.016 27.144 56.028 ;
     RECT  27.162 56.016 27.36 56.028 ;
     RECT  27.378 56.016 27.54 56.028 ;
     RECT  27.558 56.016 27.72 56.028 ;
     RECT  27.738 56.016 27.936 56.028 ;
     RECT  27.954 56.016 28.116 56.028 ;
     RECT  28.134 56.016 28.296 56.028 ;
     RECT  28.314 56.016 28.512 56.028 ;
     RECT  28.53 56.016 28.692 56.028 ;
     RECT  28.71 56.016 28.908 56.028 ;
     RECT  28.926 56.016 29.088 56.028 ;
     RECT  29.106 56.016 29.268 56.028 ;
     RECT  29.286 56.016 29.484 56.028 ;
     RECT  29.502 56.016 29.664 56.028 ;
     RECT  29.682 56.016 29.844 56.028 ;
     RECT  29.862 56.016 30.06 56.028 ;
     RECT  30.078 56.016 30.24 56.028 ;
     RECT  30.258 56.016 30.456 56.028 ;
     RECT  30.474 56.016 30.636 56.028 ;
     RECT  30.654 56.016 30.816 56.028 ;
     RECT  30.834 56.016 31.032 56.028 ;
     RECT  31.05 56.016 31.212 56.028 ;
     RECT  31.23 56.016 31.392 56.028 ;
     RECT  31.41 56.016 31.608 56.028 ;
     RECT  31.626 56.016 31.788 56.028 ;
     RECT  31.806 56.016 32.004 56.028 ;
     RECT  32.022 56.016 32.184 56.028 ;
     RECT  32.202 56.016 32.364 56.028 ;
     RECT  32.382 56.016 32.58 56.028 ;
     RECT  32.598 56.016 32.76 56.028 ;
     RECT  32.778 56.016 32.94 56.028 ;
     RECT  32.958 56.016 33.156 56.028 ;
     RECT  33.174 56.016 33.336 56.028 ;
     RECT  33.354 56.016 33.552 56.028 ;
     RECT  33.57 56.016 33.732 56.028 ;
     RECT  33.75 56.016 33.912 56.028 ;
     RECT  33.93 56.016 34.128 56.028 ;
     RECT  34.146 56.016 34.308 56.028 ;
     RECT  34.326 56.016 34.488 56.028 ;
     RECT  34.506 56.016 34.704 56.028 ;
     RECT  34.722 56.016 34.884 56.028 ;
     RECT  34.902 56.016 35.1 56.028 ;
     RECT  35.118 56.016 35.28 56.028 ;
     RECT  35.298 56.016 35.46 56.028 ;
     RECT  35.478 56.016 35.676 56.028 ;
     RECT  35.694 56.016 35.856 56.028 ;
     RECT  35.874 56.016 36.036 56.028 ;
     RECT  36.054 56.016 36.252 56.028 ;
     RECT  36.27 56.016 36.432 56.028 ;
     RECT  36.45 56.016 36.648 56.028 ;
     RECT  36.666 56.016 36.828 56.028 ;
     RECT  36.846 56.016 37.008 56.028 ;
     RECT  37.026 56.016 37.224 56.028 ;
     RECT  37.242 56.016 37.404 56.028 ;
     RECT  37.422 56.016 37.584 56.028 ;
     RECT  37.602 56.016 37.8 56.028 ;
     RECT  37.818 56.016 37.98 56.028 ;
     RECT  37.998 56.016 38.16 56.028 ;
     RECT  38.178 56.016 38.376 56.028 ;
     RECT  38.394 56.016 38.556 56.028 ;
     RECT  38.574 56.016 38.772 56.028 ;
     RECT  38.79 56.016 38.952 56.028 ;
     RECT  38.97 56.016 39.132 56.028 ;
     RECT  39.15 56.016 39.348 56.028 ;
     RECT  39.366 56.016 39.528 56.028 ;
     RECT  39.546 56.016 39.708 56.028 ;
     RECT  39.726 56.016 39.924 56.028 ;
     RECT  39.942 56.016 40.104 56.028 ;
     RECT  40.122 56.016 40.32 56.028 ;
     RECT  40.338 56.016 40.5 56.028 ;
     RECT  40.518 56.016 40.68 56.028 ;
     RECT  40.698 56.016 40.896 56.028 ;
     RECT  40.914 56.016 41.076 56.028 ;
     RECT  41.094 56.016 41.256 56.028 ;
     RECT  41.274 56.016 41.472 56.028 ;
     RECT  41.49 56.016 41.652 56.028 ;
     RECT  41.67 56.016 41.868 56.028 ;
     RECT  41.886 56.016 42.048 56.028 ;
     RECT  42.066 56.016 42.228 56.028 ;
     RECT  42.246 56.016 42.444 56.028 ;
     RECT  42.462 56.016 42.624 56.028 ;
     RECT  42.642 56.016 42.804 56.028 ;
     RECT  42.822 56.016 43.02 56.028 ;
     RECT  43.038 56.016 43.2 56.028 ;
     RECT  43.218 56.016 43.416 56.028 ;
     RECT  43.434 56.016 43.596 56.028 ;
     RECT  43.614 56.016 43.776 56.028 ;
     RECT  43.794 56.016 43.992 56.028 ;
     RECT  44.01 56.016 44.172 56.028 ;
     RECT  44.19 56.016 44.352 56.028 ;
     RECT  44.37 56.016 44.568 56.028 ;
     RECT  44.586 56.016 44.748 56.028 ;
     RECT  44.766 56.016 44.964 56.028 ;
     RECT  44.982 56.016 45.144 56.028 ;
     RECT  45.162 56.016 45.324 56.028 ;
     RECT  45.342 56.016 45.54 56.028 ;
     RECT  45.558 56.016 45.72 56.028 ;
     RECT  45.738 56.016 45.9 56.028 ;
     RECT  45.918 56.016 46.116 56.028 ;
     RECT  46.134 56.016 46.296 56.028 ;
     RECT  46.314 56.016 46.512 56.028 ;
     RECT  46.53 56.016 46.692 56.028 ;
     RECT  46.71 56.016 46.872 56.028 ;
     RECT  46.89 56.016 47.088 56.028 ;
     RECT  47.106 56.016 47.268 56.028 ;
     RECT  47.286 56.016 47.448 56.028 ;
     RECT  47.466 56.016 47.664 56.028 ;
     RECT  47.682 56.016 47.844 56.028 ;
     RECT  47.862 56.016 48.06 56.028 ;
     RECT  48.078 56.016 48.24 56.028 ;
     RECT  48.258 56.016 48.42 56.028 ;
     RECT  48.438 56.016 48.636 56.028 ;
     RECT  48.654 56.016 48.816 56.028 ;
     RECT  48.834 56.016 48.996 56.028 ;
     RECT  49.014 56.016 49.212 56.028 ;
     RECT  49.23 56.016 49.392 56.028 ;
     RECT  49.41 56.016 49.608 56.028 ;
     RECT  49.626 56.016 49.788 56.028 ;
     RECT  49.806 56.016 49.968 56.028 ;
     RECT  49.986 56.016 50.184 56.028 ;
     RECT  50.202 56.016 50.364 56.028 ;
     RECT  50.382 56.016 50.544 56.028 ;
     RECT  50.562 56.016 50.76 56.028 ;
     RECT  50.778 56.016 50.94 56.028 ;
     RECT  50.958 56.016 51.12 56.028 ;
     RECT  51.138 56.016 51.336 56.028 ;
     RECT  51.354 56.016 51.516 56.028 ;
     RECT  51.534 56.016 51.732 56.028 ;
     RECT  51.75 56.016 51.912 56.028 ;
     RECT  51.93 56.016 52.092 56.028 ;
     RECT  52.11 56.016 52.308 56.028 ;
     RECT  52.326 56.016 52.488 56.028 ;
     RECT  52.506 56.016 52.668 56.028 ;
     RECT  52.686 56.016 52.884 56.028 ;
     RECT  52.902 56.016 53.064 56.028 ;
     RECT  53.082 56.016 53.28 56.028 ;
     RECT  53.298 56.016 53.46 56.028 ;
     RECT  53.478 56.016 53.64 56.028 ;
     RECT  53.658 56.016 53.856 56.028 ;
     RECT  4.428 56.028 4.518 56.093 ;
     RECT  43.056 56.028 43.146 56.093 ;
    LAYER M4 ;
     RECT  2.293 1.728 2.377 1.848 ;
     RECT  2.365 5.184 2.401 5.208 ;
     RECT  2.377 1.824 2.408 1.848 ;
     RECT  2.293 3.408 2.408 3.432 ;
     RECT  2.401 5.184 2.408 6.072 ;
     RECT  2.293 30.144 2.408 30.168 ;
     RECT  2.408 1.824 2.485 54.012 ;
     RECT  2.485 1.824 2.677 54.696 ;
     RECT  2.677 1.824 2.704 55.368 ;
     RECT  2.677 0.192 2.819 0.216 ;
     RECT  2.704 54.672 2.819 55.368 ;
     RECT  2.704 3.312 2.837 7.992 ;
     RECT  2.704 1.824 2.867 2.28 ;
     RECT  2.837 3.408 2.909 7.992 ;
     RECT  2.704 30.144 2.981 31.032 ;
     RECT  2.819 55.296 3.061 55.368 ;
     RECT  2.909 4.56 3.443 7.992 ;
     RECT  2.867 1.824 3.445 1.848 ;
     RECT  2.704 28.32 3.449 28.872 ;
     RECT  2.981 31.008 3.829 31.032 ;
     RECT  3.061 55.296 3.917 55.416 ;
     RECT  3.443 7.44 3.971 7.992 ;
     RECT  3.445 1.728 3.989 1.848 ;
     RECT  3.443 4.56 3.989 6.312 ;
     RECT  3.971 7.68 4.597 7.992 ;
     RECT  3.829 31.008 4.597 31.8 ;
     RECT  3.989 4.944 4.669 6.312 ;
     RECT  3.989 1.728 4.777 1.8 ;
     RECT  3.449 28.32 4.789 28.392 ;
     RECT  3.917 55.296 4.889 55.32 ;
     RECT  2.909 3.408 4.933 3.528 ;
     RECT  4.933 3.312 5.101 3.528 ;
     RECT  4.669 4.944 5.101 6.648 ;
     RECT  4.777 1.104 5.108 1.8 ;
     RECT  5.101 3.312 5.108 6.648 ;
     RECT  4.597 7.68 5.108 8.472 ;
     RECT  4.741 17.088 5.108 17.112 ;
     RECT  4.789 28.32 5.108 29.064 ;
     RECT  4.597 30.672 5.108 31.8 ;
     RECT  4.981 44.976 5.108 45 ;
     RECT  5.108 1.104 5.173 54.012 ;
     RECT  5.173 1.104 5.404 54.696 ;
     RECT  5.404 1.104 5.411 1.752 ;
     RECT  5.404 2.736 5.573 8.52 ;
     RECT  5.404 12 5.617 12.552 ;
     RECT  5.404 46.704 5.645 46.728 ;
     RECT  5.404 16.56 5.699 17.112 ;
     RECT  5.699 17.088 5.717 17.112 ;
     RECT  5.617 12.528 5.725 12.552 ;
     RECT  5.573 4.416 5.789 8.52 ;
     RECT  5.404 53.952 5.941 54.696 ;
     RECT  5.404 29.04 6.005 29.064 ;
     RECT  5.941 53.952 6.005 55.32 ;
     RECT  5.789 4.56 6.581 8.52 ;
     RECT  5.411 1.728 6.661 1.752 ;
     RECT  5.573 2.736 6.661 3.432 ;
     RECT  6.517 30.288 6.709 30.312 ;
     RECT  6.661 1.728 6.761 3.432 ;
     RECT  5.404 18.816 6.761 18.84 ;
     RECT  5.404 26.496 6.865 26.52 ;
     RECT  6.709 30.288 6.901 30.792 ;
     RECT  6.581 4.8 7.153 8.52 ;
     RECT  6.761 2.16 7.333 3.432 ;
     RECT  6.901 30.288 7.333 31.224 ;
     RECT  7.009 0.144 7.475 0.168 ;
     RECT  7.525 44.448 7.621 44.472 ;
     RECT  6.005 53.952 7.621 53.976 ;
     RECT  7.621 53.952 7.669 54.12 ;
     RECT  7.441 1.152 7.763 1.176 ;
     RECT  7.333 2.16 7.808 3.624 ;
     RECT  7.153 4.8 7.808 8.808 ;
     RECT  6.865 26.496 7.808 26.616 ;
     RECT  5.404 27.6 7.808 27.624 ;
     RECT  7.333 30.192 7.808 31.224 ;
     RECT  5.404 34.08 7.808 34.104 ;
     RECT  7.621 44.4 7.808 44.472 ;
     RECT  7.669 53.952 7.808 54.216 ;
     RECT  7.765 0.192 7.955 0.6 ;
     RECT  7.808 2.148 7.955 54.216 ;
     RECT  7.955 2.148 8.104 54.12 ;
     RECT  7.955 0.192 8.243 0.216 ;
     RECT  8.104 44.4 8.309 44.472 ;
     RECT  8.104 3.312 8.381 8.616 ;
     RECT  8.104 2.148 8.387 2.232 ;
     RECT  8.381 4.56 8.417 8.616 ;
     RECT  8.309 44.448 8.489 44.472 ;
     RECT  8.104 26.592 8.705 26.616 ;
     RECT  8.104 30.048 8.705 31.224 ;
     RECT  8.104 54.096 8.741 54.12 ;
     RECT  8.705 30.048 8.885 30.6 ;
     RECT  8.381 3.312 9.116 3.432 ;
     RECT  8.417 4.656 9.169 8.616 ;
     RECT  8.104 27.6 9.245 27.624 ;
     RECT  8.104 42.144 9.253 42.168 ;
     RECT  8.869 1.728 9.377 1.8 ;
     RECT  9.116 2.976 9.377 3.432 ;
     RECT  9.169 4.656 9.421 8.904 ;
     RECT  9.377 1.728 9.565 3.432 ;
     RECT  9.421 4.656 9.565 9.336 ;
     RECT  6.005 55.296 9.677 55.32 ;
     RECT  9.565 1.728 9.929 9.336 ;
     RECT  8.885 30.048 10.213 30.072 ;
     RECT  10.105 0.144 10.261 0.168 ;
     RECT  10.021 53.568 10.261 53.592 ;
     RECT  9.929 2.016 10.309 9.336 ;
     RECT  10.261 43.344 10.309 43.368 ;
     RECT  10.261 53.568 10.309 54.12 ;
     RECT  10.261 0.144 10.355 0.312 ;
     RECT  10.355 0.288 10.357 0.312 ;
     RECT  10.357 0.288 10.451 0.408 ;
     RECT  10.309 2.016 10.508 9.528 ;
     RECT  10.357 17.376 10.508 17.4 ;
     RECT  9.829 28.416 10.508 28.44 ;
     RECT  10.213 30.048 10.508 30.504 ;
     RECT  8.104 33.024 10.508 33.048 ;
     RECT  9.253 41.28 10.508 42.168 ;
     RECT  10.309 43.344 10.508 43.56 ;
     RECT  10.309 53.568 10.508 54.312 ;
     RECT  10.451 0.384 10.643 0.408 ;
     RECT  10.508 2.016 10.804 54.312 ;
     RECT  10.804 54.096 10.835 54.312 ;
     RECT  10.804 2.016 10.973 9.576 ;
     RECT  10.973 2.208 10.979 9.576 ;
     RECT  10.804 18.24 11.053 18.264 ;
     RECT  10.804 29.52 11.153 30.072 ;
     RECT  10.804 26.784 11.189 26.808 ;
     RECT  10.804 33.024 11.441 33.048 ;
     RECT  10.804 41.904 11.441 41.928 ;
     RECT  11.468 0.288 11.555 0.312 ;
     RECT  10.804 45.552 11.801 45.576 ;
     RECT  10.979 2.256 11.869 9.576 ;
     RECT  11.893 17.088 12.053 17.112 ;
     RECT  10.835 54.096 12.161 54.12 ;
     RECT  11.869 2.256 12.229 9.672 ;
     RECT  12.229 2.256 12.325 9.864 ;
     RECT  11.153 29.52 12.517 29.544 ;
     RECT  12.325 55.296 12.709 55.32 ;
     RECT  12.949 14.208 12.985 14.232 ;
     RECT  12.325 1.728 12.997 9.864 ;
     RECT  12.997 1.728 13.208 9.96 ;
     RECT  12.985 13.68 13.208 14.232 ;
     RECT  12.913 17.664 13.208 17.688 ;
     RECT  11.941 21.12 13.208 21.144 ;
     RECT  10.804 28.416 13.208 28.44 ;
     RECT  12.517 29.52 13.208 30.168 ;
     RECT  10.804 43.344 13.208 43.896 ;
     RECT  11.941 44.976 13.208 45 ;
     RECT  12.901 46.224 13.208 46.248 ;
     RECT  12.709 54.72 13.208 55.32 ;
     RECT  13.208 1.728 13.504 55.32 ;
     RECT  13.504 1.728 13.565 9.912 ;
     RECT  13.504 54.096 13.619 55.32 ;
     RECT  13.525 0.192 13.667 0.216 ;
     RECT  13.504 46.224 13.709 46.248 ;
     RECT  13.619 55.296 13.745 55.32 ;
     RECT  13.504 19.392 13.763 20.088 ;
     RECT  13.504 43.344 13.781 43.896 ;
     RECT  13.781 43.344 13.853 43.368 ;
     RECT  13.763 19.392 13.969 19.416 ;
     RECT  13.504 29.52 14.033 30.168 ;
     RECT  13.619 54.096 14.177 54.12 ;
     RECT  13.504 51.84 14.573 51.864 ;
     RECT  14.497 18.816 14.581 18.84 ;
     RECT  14.485 45.552 14.825 45.576 ;
     RECT  14.677 44.448 14.869 44.472 ;
     RECT  14.869 43.872 15.061 44.472 ;
     RECT  14.533 14.784 15.073 14.808 ;
     RECT  13.565 2.256 15.109 9.912 ;
     RECT  13.504 33.264 15.253 33.288 ;
     RECT  15.061 43.824 15.637 44.472 ;
     RECT  15.445 53.568 15.749 53.592 ;
     RECT  15.749 53.568 15.788 54.072 ;
     RECT  15.109 2.256 15.908 10.248 ;
     RECT  15.073 14.256 15.908 14.808 ;
     RECT  14.033 30.144 15.908 30.168 ;
     RECT  15.253 33.264 15.908 33.576 ;
     RECT  13.504 41.808 15.908 41.832 ;
     RECT  15.637 43.344 15.908 44.472 ;
     RECT  15.788 53.568 15.908 54.168 ;
     RECT  15.733 0.192 16.021 0.216 ;
     RECT  15.908 2.148 16.021 54.168 ;
     RECT  16.021 2.148 16.204 54.696 ;
     RECT  16.021 0.192 16.355 0.312 ;
     RECT  16.355 0.288 16.499 0.312 ;
     RECT  16.204 53.568 16.547 54.696 ;
     RECT  16.204 2.148 16.625 9.912 ;
     RECT  16.625 2.148 16.789 9 ;
     RECT  16.547 53.568 16.841 54.12 ;
     RECT  16.204 43.776 17.173 43.896 ;
     RECT  16.204 33.264 17.201 33.576 ;
     RECT  16.789 1.728 17.605 9 ;
     RECT  17.605 1.728 17.653 9.144 ;
     RECT  16.204 42.72 17.749 42.744 ;
     RECT  17.173 43.776 17.749 44.808 ;
     RECT  17.653 1.728 17.797 9.72 ;
     RECT  17.797 1.152 17.845 9.72 ;
     RECT  17.845 1.152 17.849 9.864 ;
     RECT  17.849 1.152 17.885 1.176 ;
     RECT  17.849 2.148 18.061 9.864 ;
     RECT  16.841 53.568 18.133 53.592 ;
     RECT  18.133 53.568 18.421 53.976 ;
     RECT  17.749 42.72 18.469 44.808 ;
     RECT  18.421 53.568 18.469 54.12 ;
     RECT  18.061 2.148 18.608 10.152 ;
     RECT  17.941 32.208 18.608 32.232 ;
     RECT  17.201 33.552 18.608 33.576 ;
     RECT  18.469 42 18.608 44.808 ;
     RECT  18.469 53.568 18.608 54.216 ;
     RECT  18.421 0.192 18.817 0.36 ;
     RECT  18.608 2.148 18.901 54.216 ;
     RECT  18.901 2.148 18.904 54.696 ;
     RECT  18.817 0.144 19.043 0.36 ;
     RECT  18.904 54.672 19.043 54.696 ;
     RECT  19.043 0.192 19.069 0.36 ;
     RECT  19.069 0.192 19.153 1.176 ;
     RECT  18.904 2.148 19.177 9.864 ;
     RECT  19.153 0.192 19.235 0.312 ;
     RECT  19.235 0.288 19.283 0.312 ;
     RECT  18.904 17.088 19.283 17.112 ;
     RECT  19.177 1.728 19.505 9.864 ;
     RECT  18.904 42 19.505 42.168 ;
     RECT  19.477 55.296 19.757 55.32 ;
     RECT  19.505 2.832 19.937 9.864 ;
     RECT  18.904 45.888 20.333 45.912 ;
     RECT  18.904 43.824 20.485 43.896 ;
     RECT  19.505 42.096 20.677 42.168 ;
     RECT  19.505 1.728 20.737 1.752 ;
     RECT  19.937 2.88 20.905 9.864 ;
     RECT  21.109 0.288 21.157 0.312 ;
     RECT  21.116 28.416 21.157 28.44 ;
     RECT  20.977 53.568 21.157 53.592 ;
     RECT  20.905 2.148 21.308 9.864 ;
     RECT  21.013 17.952 21.308 17.976 ;
     RECT  21.157 28.416 21.308 29.016 ;
     RECT  18.904 32.208 21.308 32.232 ;
     RECT  20.677 42 21.308 42.168 ;
     RECT  20.485 43.344 21.308 43.896 ;
     RECT  20.861 45.552 21.308 45.576 ;
     RECT  21.157 53.568 21.308 54.168 ;
     RECT  21.157 0.192 21.491 0.312 ;
     RECT  21.308 2.148 21.604 54.168 ;
     RECT  21.491 0.192 21.779 0.216 ;
     RECT  21.637 54.672 21.779 54.696 ;
     RECT  21.604 30.768 21.809 30.792 ;
     RECT  21.604 22.224 21.875 22.248 ;
     RECT  21.604 19.968 21.961 19.992 ;
     RECT  21.604 2.148 22.013 9.672 ;
     RECT  21.829 55.296 22.021 55.32 ;
     RECT  22.021 55.296 22.133 55.368 ;
     RECT  21.604 43.344 22.169 43.896 ;
     RECT  21.604 34.752 22.241 34.776 ;
     RECT  21.604 51.264 22.241 51.864 ;
     RECT  22.013 1.728 22.492 9.672 ;
     RECT  21.604 42 22.597 42.024 ;
     RECT  22.492 1.728 22.637 7.992 ;
     RECT  22.133 55.296 22.637 55.32 ;
     RECT  22.637 2.256 22.645 7.992 ;
     RECT  22.241 51.84 22.673 51.864 ;
     RECT  22.169 43.824 23.033 43.896 ;
     RECT  22.645 2.256 23.708 7.896 ;
     RECT  23.708 1.728 23.749 7.896 ;
     RECT  22.492 8.976 23.749 9.672 ;
     RECT  23.749 1.152 23.891 9.672 ;
     RECT  23.852 30.768 23.893 30.792 ;
     RECT  22.789 54.096 23.941 54.12 ;
     RECT  23.891 1.728 24.008 9.672 ;
     RECT  21.604 17.856 24.008 17.88 ;
     RECT  23.893 30.672 24.008 30.792 ;
     RECT  22.597 42 24.008 42.744 ;
     RECT  23.033 43.872 24.008 43.896 ;
     RECT  22.981 44.976 24.008 45 ;
     RECT  23.557 50.112 24.008 50.136 ;
     RECT  23.941 54.096 24.008 54.696 ;
     RECT  24.008 1.728 24.304 54.696 ;
     RECT  23.941 0.288 24.325 0.36 ;
     RECT  24.325 0.192 24.419 0.36 ;
     RECT  24.419 0.192 24.467 0.312 ;
     RECT  24.467 0.288 24.515 0.312 ;
     RECT  24.304 43.776 24.545 43.896 ;
     RECT  24.304 1.728 24.761 7.992 ;
     RECT  24.304 54.096 24.761 54.696 ;
     RECT  24.304 42 24.905 42.024 ;
     RECT  24.761 2.64 25.187 7.992 ;
     RECT  24.545 43.824 25.229 43.896 ;
     RECT  25.187 2.736 25.333 7.992 ;
     RECT  24.304 8.976 25.333 9.672 ;
     RECT  25.333 2.736 25.477 9.672 ;
     RECT  24.304 33.6 25.481 34.2 ;
     RECT  24.304 51.84 25.481 51.864 ;
     RECT  25.405 16.56 25.489 16.584 ;
     RECT  25.405 13.68 25.523 13.704 ;
     RECT  25.285 54.72 25.661 54.744 ;
     RECT  25.477 2.736 25.873 10.248 ;
     RECT  25.861 55.296 26.129 55.32 ;
     RECT  26.161 0.144 26.437 0.168 ;
     RECT  25.669 42.72 26.485 42.744 ;
     RECT  25.229 43.824 26.485 43.848 ;
     RECT  25.861 1.728 26.533 1.752 ;
     RECT  25.873 2.736 26.533 10.824 ;
     RECT  26.437 0.144 26.627 0.312 ;
     RECT  26.533 1.728 26.629 10.824 ;
     RECT  26.629 1.68 26.708 10.824 ;
     RECT  26.245 32.208 26.708 32.232 ;
     RECT  25.481 34.176 26.708 34.2 ;
     RECT  26.485 42.72 26.708 43.848 ;
     RECT  26.053 50.544 26.708 50.568 ;
     RECT  26.581 53.904 26.708 54.168 ;
     RECT  26.708 1.68 27.004 54.168 ;
     RECT  26.627 0.192 27.109 0.312 ;
     RECT  27.004 53.904 27.148 54.168 ;
     RECT  27.004 1.68 27.173 10.248 ;
     RECT  27.109 0.192 27.203 0.408 ;
     RECT  27.148 53.904 27.203 54.12 ;
     RECT  27.203 0.288 27.251 0.408 ;
     RECT  27.173 1.728 27.281 10.248 ;
     RECT  27.251 0.384 27.299 0.408 ;
     RECT  27.004 42.72 27.461 45.576 ;
     RECT  27.004 18.24 27.685 18.84 ;
     RECT  27.461 42.72 27.713 43.32 ;
     RECT  27.281 2.208 27.731 10.248 ;
     RECT  27.685 18.24 27.923 18.312 ;
     RECT  27.461 44.688 27.929 45.576 ;
     RECT  27.203 53.904 28.001 53.928 ;
     RECT  27.004 32.208 28.213 32.232 ;
     RECT  27.713 43.296 28.597 43.32 ;
     RECT  27.731 2.208 28.789 10.2 ;
     RECT  27.445 55.296 28.829 55.32 ;
     RECT  28.789 1.728 28.873 10.2 ;
     RECT  28.46 0.144 28.892 0.168 ;
     RECT  28.892 0.144 29.123 0.312 ;
     RECT  29.123 0.192 29.221 0.312 ;
     RECT  27.929 45.552 29.269 45.576 ;
     RECT  28.021 53.568 29.269 53.592 ;
     RECT  28.873 2.016 29.408 10.2 ;
     RECT  28.213 14.976 29.408 15 ;
     RECT  28.597 16.56 29.408 16.584 ;
     RECT  27.923 18.24 29.408 18.264 ;
     RECT  28.645 19.968 29.408 19.992 ;
     RECT  28.789 30.144 29.408 30.168 ;
     RECT  28.213 31.296 29.408 32.232 ;
     RECT  29.173 33.552 29.408 33.576 ;
     RECT  28.597 43.296 29.408 43.368 ;
     RECT  29.269 44.976 29.408 45.576 ;
     RECT  29.269 53.568 29.408 54.168 ;
     RECT  29.408 2.016 29.704 54.168 ;
     RECT  29.704 30.144 29.765 30.168 ;
     RECT  29.704 54.048 29.837 54.168 ;
     RECT  29.837 54.048 29.881 54.12 ;
     RECT  29.704 43.296 29.981 43.896 ;
     RECT  29.704 22.8 30.017 22.824 ;
     RECT  29.704 2.016 30.089 10.104 ;
     RECT  29.881 54.096 30.233 54.12 ;
     RECT  29.221 0.192 30.269 0.552 ;
     RECT  30.089 2.016 30.325 9.96 ;
     RECT  30.269 0.192 30.625 0.312 ;
     RECT  30.325 1.728 30.629 9.96 ;
     RECT  30.629 2.208 30.748 9.96 ;
     RECT  29.704 44.976 30.773 45 ;
     RECT  29.704 18.24 30.845 18.84 ;
     RECT  29.704 40.992 30.845 41.928 ;
     RECT  30.625 0.144 30.851 0.312 ;
     RECT  30.709 13.488 30.949 13.512 ;
     RECT  30.949 20.544 31.033 20.568 ;
     RECT  30.949 15.984 31.043 16.008 ;
     RECT  30.845 18.24 31.061 18.264 ;
     RECT  30.949 13.104 31.133 13.512 ;
     RECT  30.901 54.72 31.169 54.744 ;
     RECT  31.133 13.104 31.381 13.128 ;
     RECT  31.273 17.664 31.765 17.688 ;
     RECT  30.851 0.288 31.949 0.312 ;
     RECT  31.861 53.568 31.957 53.592 ;
     RECT  30.748 2.256 31.993 9.96 ;
     RECT  31.949 0.288 32.053 0.552 ;
     RECT  31.993 2.016 32.108 9.96 ;
     RECT  31.381 12.576 32.108 13.128 ;
     RECT  29.704 14.976 32.108 15 ;
     RECT  31.765 17.088 32.108 17.688 ;
     RECT  31.489 19.392 32.108 19.416 ;
     RECT  29.704 33.552 32.108 34.536 ;
     RECT  30.845 41.472 32.108 41.928 ;
     RECT  29.981 43.344 32.108 43.896 ;
     RECT  31.957 44.976 32.108 45 ;
     RECT  31.957 53.568 32.108 54.168 ;
     RECT  32.053 55.296 32.285 55.32 ;
     RECT  32.108 2.016 32.291 54.168 ;
     RECT  32.291 2.016 32.404 54.12 ;
     RECT  32.404 54.096 32.524 54.12 ;
     RECT  32.053 0.192 32.579 0.552 ;
     RECT  32.404 2.016 32.581 9.624 ;
     RECT  32.404 12.528 32.63 12.6 ;
     RECT  32.404 44.976 32.789 45 ;
     RECT  32.63 12.528 33.041 12.552 ;
     RECT  32.581 1.104 33.185 9.624 ;
     RECT  32.404 41.472 33.185 42.168 ;
     RECT  33.505 29.088 33.589 29.112 ;
     RECT  33.541 0.144 33.779 0.168 ;
     RECT  34.213 0.192 34.355 0.216 ;
     RECT  34.357 0.288 34.643 0.312 ;
     RECT  33.821 54.096 34.789 54.12 ;
     RECT  33.185 1.728 34.808 9.624 ;
     RECT  34.189 12.528 34.808 12.552 ;
     RECT  32.404 14.976 34.808 15 ;
     RECT  34.513 22.8 34.808 22.824 ;
     RECT  33.185 42 34.808 42.168 ;
     RECT  32.404 43.776 34.808 43.896 ;
     RECT  34.405 50.112 34.808 50.136 ;
     RECT  34.213 51.84 34.808 51.864 ;
     RECT  34.789 54.096 34.808 54.744 ;
     RECT  34.808 1.728 35.104 54.744 ;
     RECT  35.104 1.728 35.165 9.672 ;
     RECT  35.165 2.736 35.267 9.672 ;
     RECT  35.104 16.56 35.267 16.92 ;
     RECT  35.104 53.808 35.273 54.744 ;
     RECT  35.267 2.736 35.363 9.336 ;
     RECT  35.104 51.888 35.363 51.912 ;
     RECT  35.273 53.808 35.363 54.216 ;
     RECT  35.104 41.52 35.381 42.024 ;
     RECT  35.363 2.832 35.489 9.336 ;
     RECT  35.381 41.52 35.525 41.544 ;
     RECT  35.165 1.728 35.669 1.752 ;
     RECT  35.104 43.728 35.669 43.752 ;
     RECT  35.104 50.688 35.813 50.712 ;
     RECT  35.363 53.808 35.921 53.832 ;
     RECT  35.267 16.896 36.029 16.92 ;
     RECT  35.941 55.296 36.065 55.32 ;
     RECT  35.665 0.144 36.083 0.168 ;
     RECT  35.104 44.976 36.325 45 ;
     RECT  35.489 2.832 36.349 9.144 ;
     RECT  36.349 2.256 36.493 9.144 ;
     RECT  36.325 44.976 36.497 45.336 ;
     RECT  36.133 53.568 36.497 53.592 ;
     RECT  36.493 2.256 36.661 9.528 ;
     RECT  36.517 43.872 36.901 43.896 ;
     RECT  36.661 2.208 37.093 9.528 ;
     RECT  36.901 43.824 37.093 43.896 ;
     RECT  37.093 1.728 37.285 9.528 ;
     RECT  37.333 0.288 37.349 0.312 ;
     RECT  37.285 1.728 37.508 9.576 ;
     RECT  35.104 14.976 37.508 15 ;
     RECT  36.805 22.8 37.508 22.824 ;
     RECT  37.093 43.632 37.508 43.896 ;
     RECT  36.497 44.976 37.508 45 ;
     RECT  36.709 52.992 37.508 53.016 ;
     RECT  37.381 54.144 37.508 54.168 ;
     RECT  37.508 1.728 37.523 54.168 ;
     RECT  37.349 0.288 37.789 0.552 ;
     RECT  37.523 1.728 37.804 54.12 ;
     RECT  37.804 43.824 37.865 43.896 ;
     RECT  37.789 0.144 37.909 0.552 ;
     RECT  37.804 1.728 37.909 9.768 ;
     RECT  37.804 53.952 37.948 54.12 ;
     RECT  37.948 53.952 37.981 54.024 ;
     RECT  37.909 0.144 38.051 9.768 ;
     RECT  37.804 30.768 38.081 30.792 ;
     RECT  38.051 0.144 38.147 1.176 ;
     RECT  38.147 0.144 38.189 0.552 ;
     RECT  37.981 53.952 38.801 53.976 ;
     RECT  37.865 43.872 39.205 43.896 ;
     RECT  38.051 2.208 39.301 9.768 ;
     RECT  38.189 0.144 39.404 0.312 ;
     RECT  39.404 0.144 39.491 1.128 ;
     RECT  39.301 2.208 39.617 9.96 ;
     RECT  39.013 29.76 39.829 29.784 ;
     RECT  39.491 0.144 39.971 0.312 ;
     RECT  39.617 1.728 40.097 9.96 ;
     RECT  40.097 1.824 40.208 9.96 ;
     RECT  37.804 14.976 40.208 15 ;
     RECT  39.265 16.56 40.208 16.584 ;
     RECT  39.661 25.68 40.208 25.704 ;
     RECT  37.804 26.736 40.208 26.76 ;
     RECT  37.804 28.128 40.208 28.152 ;
     RECT  39.829 29.76 40.208 30.168 ;
     RECT  40.021 33.024 40.208 33.048 ;
     RECT  39.205 43.728 40.208 43.896 ;
     RECT  39.637 53.808 40.208 53.832 ;
     RECT  39.971 0.288 40.259 0.312 ;
     RECT  40.208 1.824 40.405 54.012 ;
     RECT  40.405 1.824 40.504 54.12 ;
     RECT  40.504 5.52 40.529 9.864 ;
     RECT  37.285 55.296 40.597 55.32 ;
     RECT  40.529 5.712 40.643 9.72 ;
     RECT  40.643 5.712 40.673 7.992 ;
     RECT  40.597 55.296 40.684 55.368 ;
     RECT  40.504 1.824 40.753 4.392 ;
     RECT  40.504 33.024 40.889 34.008 ;
     RECT  40.673 5.712 41.357 7.656 ;
     RECT  40.753 2.736 41.497 4.392 ;
     RECT  40.643 8.976 41.713 9.72 ;
     RECT  40.504 54 41.749 54.12 ;
     RECT  41.245 1.728 41.797 1.752 ;
     RECT  41.497 2.736 41.797 4.584 ;
     RECT  41.713 8.976 41.821 10.248 ;
     RECT  41.797 1.728 41.893 4.584 ;
     RECT  41.357 5.712 41.893 7.416 ;
     RECT  40.889 33.984 41.933 34.008 ;
     RECT  40.504 29.76 42.073 30.648 ;
     RECT  42.073 29.088 42.325 30.648 ;
     RECT  40.504 31.872 42.325 31.896 ;
     RECT  41.893 1.728 42.469 7.416 ;
     RECT  41.821 8.496 42.469 10.248 ;
     RECT  42.133 43.872 42.517 43.896 ;
     RECT  40.684 55.296 42.616 55.32 ;
     RECT  42.709 33.936 42.757 33.96 ;
     RECT  41.749 53.904 42.757 54.12 ;
     RECT  42.616 55.248 42.761 55.32 ;
     RECT  42.469 1.728 42.908 10.248 ;
     RECT  40.504 14.976 42.908 15 ;
     RECT  42.325 29.088 42.908 31.896 ;
     RECT  42.757 33.552 42.908 33.96 ;
     RECT  42.517 43.344 42.908 43.896 ;
     RECT  42.757 53.904 42.908 54.168 ;
     RECT  42.908 1.728 42.947 54.168 ;
     RECT  42.947 1.728 43.012 54.012 ;
     RECT  41.852 0.288 43.189 0.312 ;
     RECT  43.012 1.728 43.204 53.742 ;
     RECT  43.204 31.2 43.445 31.752 ;
     RECT  43.204 33.552 43.517 33.96 ;
     RECT  43.204 11.424 43.561 11.448 ;
     RECT  43.204 1.728 43.733 10.44 ;
     RECT  43.517 33.552 43.769 33.576 ;
     RECT  43.189 0.192 43.859 0.36 ;
     RECT  42.761 55.296 43.861 55.32 ;
     RECT  43.859 0.192 43.981 0.216 ;
     RECT  43.861 55.296 44.053 55.368 ;
     RECT  43.204 19.392 44.173 19.416 ;
     RECT  43.981 0.144 44.195 0.216 ;
     RECT  43.204 43.872 44.237 43.896 ;
     RECT  43.204 14.976 44.485 15.384 ;
     RECT  43.733 8.784 44.629 10.44 ;
     RECT  44.485 14.976 44.629 15.432 ;
     RECT  43.445 31.728 44.629 31.752 ;
     RECT  43.733 2.256 44.701 7.704 ;
     RECT  44.629 8.784 44.701 10.824 ;
     RECT  44.053 55.296 44.741 55.416 ;
     RECT  44.437 43.776 44.821 43.8 ;
     RECT  44.701 2.256 44.869 10.824 ;
     RECT  44.629 14.832 44.953 15.432 ;
     RECT  44.869 2.208 45.013 10.824 ;
     RECT  44.195 0.192 45.133 0.216 ;
     RECT  45.013 1.728 45.137 10.824 ;
     RECT  44.953 14.832 45.349 15.96 ;
     RECT  45.137 2.148 45.608 10.824 ;
     RECT  45.349 14.64 45.608 15.96 ;
     RECT  44.945 19.968 45.608 19.992 ;
     RECT  44.629 31.728 45.608 31.8 ;
     RECT  44.245 42 45.608 42.024 ;
     RECT  44.821 43.728 45.608 43.8 ;
     RECT  45.397 44.88 45.608 44.904 ;
     RECT  45.013 52.416 45.608 52.44 ;
     RECT  45.205 54.096 45.608 54.12 ;
     RECT  45.608 2.148 45.781 54.12 ;
     RECT  44.741 55.296 45.781 55.32 ;
     RECT  45.781 2.148 45.785 55.32 ;
     RECT  45.133 0.192 45.877 0.504 ;
     RECT  45.785 2.148 45.904 54.744 ;
     RECT  45.904 44.88 46.037 44.904 ;
     RECT  45.904 50.16 46.073 50.712 ;
     RECT  45.877 0.192 46.115 1.176 ;
     RECT  45.904 42 46.181 42.648 ;
     RECT  45.904 54.096 46.289 54.744 ;
     RECT  46.213 1.728 46.297 1.752 ;
     RECT  46.115 0.192 46.652 0.36 ;
     RECT  46.289 54.72 46.721 54.744 ;
     RECT  45.904 29.376 46.829 29.4 ;
     RECT  46.933 55.296 47.027 55.32 ;
     RECT  46.073 50.16 47.117 50.184 ;
     RECT  45.904 31.728 47.261 31.8 ;
     RECT  45.904 2.784 47.317 10.488 ;
     RECT  45.904 45.888 47.333 45.912 ;
     RECT  46.652 0.144 47.605 0.36 ;
     RECT  47.557 41.568 47.749 41.592 ;
     RECT  46.181 42.624 47.749 42.648 ;
     RECT  47.317 2.784 47.797 10.92 ;
     RECT  47.261 31.776 47.941 31.8 ;
     RECT  47.365 33.024 47.941 33.048 ;
     RECT  47.933 1.728 48.157 1.752 ;
     RECT  47.797 2.736 48.157 10.92 ;
     RECT  47.749 41.568 48.181 42.648 ;
     RECT  48.133 55.296 48.305 55.32 ;
     RECT  48.157 1.728 48.308 10.92 ;
     RECT  45.904 11.952 48.308 11.976 ;
     RECT  45.904 14.976 48.308 15 ;
     RECT  48.133 17.664 48.308 17.688 ;
     RECT  48.181 19.536 48.308 19.56 ;
     RECT  47.653 29.088 48.308 29.112 ;
     RECT  47.941 31.776 48.308 33.048 ;
     RECT  48.181 41.568 48.308 42.744 ;
     RECT  47.173 43.872 48.308 43.896 ;
     RECT  48.181 54.144 48.308 54.168 ;
     RECT  47.605 0.144 48.449 0.552 ;
     RECT  48.308 1.728 48.517 54.168 ;
     RECT  48.517 1.728 48.604 54.696 ;
     RECT  48.604 31.776 48.665 32.328 ;
     RECT  48.604 50.688 48.851 50.808 ;
     RECT  48.604 53.568 48.851 54.696 ;
     RECT  48.604 44.448 48.953 45 ;
     RECT  48.604 1.728 48.989 11.976 ;
     RECT  48.851 50.688 48.989 50.712 ;
     RECT  48.665 32.304 49.025 32.328 ;
     RECT  48.851 53.568 49.601 54.12 ;
     RECT  48.953 44.448 49.709 44.472 ;
     RECT  48.449 0.144 49.957 0.312 ;
     RECT  49.601 53.568 49.961 53.592 ;
     RECT  48.989 2.208 50.101 11.976 ;
     RECT  49.957 0.144 50.195 0.552 ;
     RECT  50.195 0.192 50.387 0.552 ;
     RECT  49.669 19.392 50.437 19.416 ;
     RECT  50.437 19.392 50.581 20.088 ;
     RECT  50.245 40.464 50.629 40.488 ;
     RECT  50.821 55.296 50.965 55.32 ;
     RECT  50.965 55.296 50.969 55.416 ;
     RECT  50.101 2.16 51.008 11.976 ;
     RECT  48.604 14.976 51.008 15 ;
     RECT  50.581 19.392 51.008 20.52 ;
     RECT  50.821 21.696 51.008 21.72 ;
     RECT  50.245 24.912 51.008 24.936 ;
     RECT  50.533 26.784 51.008 26.808 ;
     RECT  50.053 29.616 51.008 29.64 ;
     RECT  50.569 34.8 51.008 34.824 ;
     RECT  50.629 40.464 51.008 40.68 ;
     RECT  48.604 42.096 51.008 42.12 ;
     RECT  50.437 43.296 51.008 43.32 ;
     RECT  50.869 44.88 51.008 44.904 ;
     RECT  49.861 46.128 51.008 46.152 ;
     RECT  50.245 52.416 51.008 52.44 ;
     RECT  50.869 54.144 51.008 54.168 ;
     RECT  50.387 0.288 51.059 0.552 ;
     RECT  51.008 2.148 51.059 54.168 ;
     RECT  51.059 0.336 51.149 0.552 ;
     RECT  51.149 0.336 51.251 0.504 ;
     RECT  50.969 55.392 51.251 55.416 ;
     RECT  51.059 2.148 51.304 54.012 ;
     RECT  51.304 40.656 51.329 40.68 ;
     RECT  51.251 0.48 51.365 0.504 ;
     RECT  51.304 17.664 51.443 17.784 ;
     RECT  51.304 21.696 51.509 21.72 ;
     RECT  51.304 16.56 51.769 16.584 ;
     RECT  51.304 43.44 51.869 44.904 ;
     RECT  51.443 17.76 51.877 17.784 ;
     RECT  51.304 47.856 51.905 47.88 ;
     RECT  51.304 2.148 51.965 11.448 ;
     RECT  51.869 44.88 51.977 44.904 ;
     RECT  51.965 1.728 52.049 11.448 ;
     RECT  51.304 14.976 52.057 15.432 ;
     RECT  51.304 45.888 52.085 46.728 ;
     RECT  52.297 21.648 52.381 21.672 ;
     RECT  51.304 13.632 52.405 13.656 ;
     RECT  52.057 14.976 52.405 15 ;
     RECT  52.049 2.304 52.409 11.448 ;
     RECT  52.409 7.968 52.445 11.448 ;
     RECT  51.869 43.44 52.445 43.464 ;
     RECT  52.085 45.888 52.445 45.912 ;
     RECT  52.409 2.688 52.481 6.888 ;
     RECT  52.405 13.632 52.501 15 ;
     RECT  52.045 54.144 52.577 54.168 ;
     RECT  52.577 53.568 52.661 54.168 ;
     RECT  52.405 42.144 52.697 42.168 ;
     RECT  52.789 55.296 53.089 55.32 ;
     RECT  52.661 54.096 53.132 54.168 ;
     RECT  53.089 55.296 53.132 55.368 ;
     RECT  52.501 13.392 53.161 15 ;
     RECT  53.132 54.096 53.219 55.368 ;
     RECT  52.445 8.448 53.269 11.448 ;
     RECT  53.269 21.12 53.413 21.144 ;
     RECT  53.413 20.544 53.549 21.144 ;
     RECT  52.481 2.784 53.665 6.888 ;
     RECT  53.269 25.104 53.665 25.128 ;
     RECT  53.219 54.096 53.705 54.12 ;
     RECT  53.665 2.016 53.708 6.888 ;
     RECT  53.269 8.448 53.708 11.976 ;
     RECT  53.161 13.296 53.708 15 ;
     RECT  52.981 16.56 53.708 16.584 ;
     RECT  53.305 18.768 53.708 18.792 ;
     RECT  53.549 19.968 53.708 21.144 ;
     RECT  53.665 25.104 53.708 25.224 ;
     RECT  53.017 27.84 53.708 27.864 ;
     RECT  53.233 29.04 53.708 29.064 ;
     RECT  53.708 2.016 53.749 54.012 ;
     RECT  53.219 55.296 53.795 55.368 ;
     RECT  53.749 1.728 53.812 54.012 ;
     RECT  53.812 1.728 54.004 53.742 ;
     RECT  53.795 55.296 54.065 55.32 ;
     RECT  54.004 1.728 54.101 1.752 ;
     RECT  53.845 0.144 54.131 0.168 ;
     RECT  54.004 6.288 54.131 6.312 ;
     RECT  54.004 25.2 54.137 25.224 ;
    LAYER M5 ;
     RECT  7.44 0.133 7.464 0.144 ;
     RECT  10.32 0.133 10.344 0.144 ;
     RECT  19.008 0.133 19.032 0.144 ;
     RECT  26.592 0.133 26.616 0.144 ;
     RECT  28.512 0.133 28.608 0.144 ;
     RECT  28.632 0.133 28.8 0.144 ;
     RECT  28.824 0.133 28.992 0.144 ;
     RECT  29.016 0.133 29.112 0.144 ;
     RECT  30.816 0.133 30.84 0.144 ;
     RECT  33.744 0.133 33.768 0.144 ;
     RECT  36.048 0.133 36.072 0.144 ;
     RECT  38.16 0.133 38.184 0.144 ;
     RECT  39.36 0.133 39.456 0.144 ;
     RECT  39.48 0.133 39.648 0.144 ;
     RECT  39.672 0.133 39.84 0.144 ;
     RECT  39.864 0.133 39.96 0.144 ;
     RECT  44.16 0.133 44.184 0.144 ;
     RECT  46.704 0.133 46.8 0.144 ;
     RECT  46.824 0.133 46.992 0.144 ;
     RECT  47.016 0.133 47.184 0.144 ;
     RECT  47.208 0.133 47.376 0.144 ;
     RECT  47.4 0.133 47.568 0.144 ;
     RECT  47.592 0.133 47.688 0.144 ;
     RECT  49.2 0.133 49.296 0.144 ;
     RECT  49.32 0.133 49.488 0.144 ;
     RECT  49.512 0.133 49.68 0.144 ;
     RECT  49.704 0.133 49.872 0.144 ;
     RECT  49.896 0.133 50.064 0.144 ;
     RECT  50.088 0.133 50.184 0.144 ;
     RECT  54.096 0.133 54.12 0.144 ;
     RECT  2.328 0.144 2.496 0.192 ;
     RECT  2.52 0.144 2.688 0.192 ;
     RECT  2.712 0.144 2.88 0.192 ;
     RECT  2.904 0.144 3.072 0.192 ;
     RECT  3.096 0.144 3.264 0.192 ;
     RECT  3.288 0.144 3.456 0.192 ;
     RECT  3.48 0.144 3.648 0.192 ;
     RECT  3.672 0.144 3.84 0.192 ;
     RECT  3.864 0.144 4.032 0.192 ;
     RECT  4.056 0.144 4.224 0.192 ;
     RECT  4.248 0.144 4.416 0.192 ;
     RECT  4.44 0.144 4.608 0.192 ;
     RECT  4.632 0.144 4.8 0.192 ;
     RECT  4.824 0.144 4.992 0.192 ;
     RECT  5.016 0.144 5.184 0.192 ;
     RECT  5.208 0.144 5.376 0.192 ;
     RECT  5.4 0.144 5.568 0.192 ;
     RECT  5.592 0.144 5.76 0.192 ;
     RECT  5.784 0.144 5.952 0.192 ;
     RECT  5.976 0.144 6.144 0.192 ;
     RECT  6.168 0.144 6.336 0.192 ;
     RECT  6.36 0.144 6.528 0.192 ;
     RECT  6.552 0.144 6.72 0.192 ;
     RECT  6.744 0.144 6.912 0.192 ;
     RECT  6.936 0.144 7.152 0.192 ;
     RECT  7.176 0.144 7.344 0.192 ;
     RECT  7.368 0.144 7.536 0.192 ;
     RECT  7.56 0.144 7.728 0.192 ;
     RECT  7.752 0.144 7.92 0.192 ;
     RECT  7.944 0.144 8.112 0.192 ;
     RECT  8.136 0.144 8.304 0.192 ;
     RECT  8.328 0.144 8.496 0.192 ;
     RECT  8.52 0.144 8.688 0.192 ;
     RECT  8.712 0.144 8.88 0.192 ;
     RECT  8.904 0.144 9.072 0.192 ;
     RECT  9.096 0.144 9.264 0.192 ;
     RECT  9.288 0.144 9.456 0.192 ;
     RECT  9.48 0.144 9.648 0.192 ;
     RECT  9.672 0.144 9.84 0.192 ;
     RECT  9.864 0.144 10.032 0.192 ;
     RECT  10.056 0.144 10.224 0.192 ;
     RECT  10.248 0.144 10.416 0.192 ;
     RECT  10.44 0.144 10.608 0.192 ;
     RECT  10.632 0.144 10.8 0.192 ;
     RECT  10.824 0.144 10.992 0.192 ;
     RECT  11.016 0.144 11.184 0.192 ;
     RECT  11.208 0.144 11.376 0.192 ;
     RECT  11.4 0.144 11.568 0.192 ;
     RECT  11.592 0.144 11.76 0.192 ;
     RECT  11.784 0.144 11.952 0.192 ;
     RECT  11.976 0.144 12.144 0.192 ;
     RECT  12.168 0.144 12.336 0.192 ;
     RECT  12.36 0.144 12.528 0.192 ;
     RECT  12.552 0.144 12.72 0.192 ;
     RECT  12.744 0.144 12.912 0.192 ;
     RECT  12.936 0.144 13.104 0.192 ;
     RECT  13.128 0.144 13.296 0.192 ;
     RECT  13.32 0.144 13.536 0.192 ;
     RECT  13.56 0.144 13.728 0.192 ;
     RECT  13.752 0.144 13.92 0.192 ;
     RECT  13.944 0.144 14.112 0.192 ;
     RECT  14.136 0.144 14.304 0.192 ;
     RECT  14.328 0.144 14.496 0.192 ;
     RECT  14.52 0.144 14.688 0.192 ;
     RECT  14.712 0.144 14.88 0.192 ;
     RECT  14.904 0.144 15.072 0.192 ;
     RECT  15.096 0.144 15.264 0.192 ;
     RECT  15.288 0.144 15.456 0.192 ;
     RECT  15.48 0.144 15.648 0.192 ;
     RECT  15.672 0.144 15.84 0.192 ;
     RECT  15.864 0.144 16.032 0.192 ;
     RECT  16.056 0.144 16.224 0.192 ;
     RECT  16.248 0.144 16.416 0.192 ;
     RECT  16.44 0.144 16.608 0.192 ;
     RECT  16.632 0.144 16.8 0.192 ;
     RECT  16.824 0.144 16.992 0.192 ;
     RECT  17.016 0.144 17.184 0.192 ;
     RECT  17.208 0.144 17.376 0.192 ;
     RECT  17.4 0.144 17.568 0.192 ;
     RECT  17.592 0.144 17.76 0.192 ;
     RECT  17.784 0.144 17.952 0.192 ;
     RECT  17.976 0.144 18.144 0.192 ;
     RECT  18.168 0.144 18.336 0.192 ;
     RECT  18.36 0.144 18.528 0.192 ;
     RECT  18.552 0.144 18.72 0.192 ;
     RECT  18.744 0.144 18.912 0.192 ;
     RECT  18.936 0.144 19.104 0.192 ;
     RECT  19.128 0.144 19.296 0.192 ;
     RECT  19.32 0.144 19.488 0.192 ;
     RECT  19.512 0.144 19.68 0.192 ;
     RECT  19.704 0.144 19.872 0.192 ;
     RECT  19.896 0.144 20.112 0.192 ;
     RECT  20.136 0.144 20.304 0.192 ;
     RECT  20.328 0.144 20.496 0.192 ;
     RECT  20.52 0.144 20.688 0.192 ;
     RECT  20.712 0.144 20.88 0.192 ;
     RECT  20.904 0.144 21.072 0.192 ;
     RECT  21.096 0.144 21.264 0.192 ;
     RECT  21.288 0.144 21.456 0.192 ;
     RECT  21.48 0.144 21.648 0.192 ;
     RECT  21.672 0.144 21.84 0.192 ;
     RECT  21.864 0.144 22.032 0.192 ;
     RECT  22.056 0.144 22.224 0.192 ;
     RECT  22.248 0.144 22.416 0.192 ;
     RECT  22.44 0.144 22.608 0.192 ;
     RECT  22.632 0.144 22.8 0.192 ;
     RECT  22.824 0.144 22.992 0.192 ;
     RECT  23.016 0.144 23.184 0.192 ;
     RECT  23.208 0.144 23.376 0.192 ;
     RECT  23.4 0.144 23.568 0.192 ;
     RECT  23.592 0.144 23.76 0.192 ;
     RECT  23.784 0.144 23.952 0.192 ;
     RECT  23.976 0.144 24.144 0.192 ;
     RECT  24.168 0.144 24.336 0.192 ;
     RECT  24.36 0.144 24.528 0.192 ;
     RECT  24.552 0.144 24.72 0.192 ;
     RECT  24.744 0.144 24.912 0.192 ;
     RECT  24.936 0.144 25.104 0.192 ;
     RECT  25.128 0.144 25.296 0.192 ;
     RECT  25.32 0.144 25.488 0.192 ;
     RECT  25.512 0.144 25.68 0.192 ;
     RECT  25.704 0.144 25.872 0.192 ;
     RECT  25.896 0.144 26.064 0.192 ;
     RECT  26.088 0.144 26.256 0.192 ;
     RECT  26.28 0.144 26.496 0.192 ;
     RECT  26.52 0.144 26.688 0.192 ;
     RECT  26.712 0.144 26.88 0.192 ;
     RECT  26.904 0.144 27.072 0.192 ;
     RECT  27.096 0.144 27.264 0.192 ;
     RECT  27.288 0.144 27.456 0.192 ;
     RECT  27.48 0.144 27.648 0.192 ;
     RECT  27.672 0.144 27.84 0.192 ;
     RECT  27.864 0.144 28.032 0.192 ;
     RECT  28.056 0.144 28.224 0.192 ;
     RECT  28.248 0.144 28.416 0.192 ;
     RECT  28.44 0.144 28.608 0.192 ;
     RECT  28.632 0.144 28.8 0.192 ;
     RECT  28.824 0.144 28.992 0.192 ;
     RECT  29.016 0.144 29.184 0.192 ;
     RECT  29.208 0.144 29.376 0.192 ;
     RECT  29.4 0.144 29.568 0.192 ;
     RECT  29.592 0.144 29.76 0.192 ;
     RECT  29.784 0.144 29.952 0.192 ;
     RECT  29.976 0.144 30.144 0.192 ;
     RECT  30.168 0.144 30.336 0.192 ;
     RECT  30.36 0.144 30.528 0.192 ;
     RECT  30.552 0.144 30.72 0.192 ;
     RECT  30.744 0.144 30.912 0.192 ;
     RECT  30.936 0.144 31.104 0.192 ;
     RECT  31.128 0.144 31.296 0.192 ;
     RECT  31.32 0.144 31.488 0.192 ;
     RECT  31.512 0.144 31.68 0.192 ;
     RECT  31.704 0.144 31.872 0.192 ;
     RECT  31.896 0.144 32.064 0.192 ;
     RECT  32.088 0.144 32.256 0.192 ;
     RECT  32.28 0.144 32.448 0.192 ;
     RECT  32.472 0.144 32.64 0.192 ;
     RECT  32.664 0.144 32.832 0.192 ;
     RECT  32.856 0.144 33.072 0.192 ;
     RECT  33.096 0.144 33.264 0.192 ;
     RECT  33.288 0.144 33.456 0.192 ;
     RECT  33.48 0.144 33.648 0.192 ;
     RECT  33.672 0.144 33.84 0.192 ;
     RECT  33.864 0.144 34.032 0.192 ;
     RECT  34.056 0.144 34.224 0.192 ;
     RECT  34.248 0.144 34.416 0.192 ;
     RECT  34.44 0.144 34.608 0.192 ;
     RECT  34.632 0.144 34.8 0.192 ;
     RECT  34.824 0.144 34.992 0.192 ;
     RECT  35.016 0.144 35.184 0.192 ;
     RECT  35.208 0.144 35.376 0.192 ;
     RECT  35.4 0.144 35.568 0.192 ;
     RECT  35.592 0.144 35.76 0.192 ;
     RECT  35.784 0.144 35.952 0.192 ;
     RECT  35.976 0.144 36.144 0.192 ;
     RECT  36.168 0.144 36.336 0.192 ;
     RECT  36.36 0.144 36.528 0.192 ;
     RECT  36.552 0.144 36.72 0.192 ;
     RECT  36.744 0.144 36.912 0.192 ;
     RECT  36.936 0.144 37.104 0.192 ;
     RECT  37.128 0.144 37.296 0.192 ;
     RECT  37.32 0.144 37.488 0.192 ;
     RECT  37.512 0.144 37.68 0.192 ;
     RECT  37.704 0.144 37.872 0.192 ;
     RECT  37.896 0.144 38.064 0.192 ;
     RECT  38.088 0.144 38.256 0.192 ;
     RECT  38.28 0.144 38.448 0.192 ;
     RECT  38.472 0.144 38.64 0.192 ;
     RECT  38.664 0.144 38.832 0.192 ;
     RECT  38.856 0.144 39.024 0.192 ;
     RECT  39.048 0.144 39.216 0.192 ;
     RECT  39.24 0.144 39.456 0.192 ;
     RECT  39.48 0.144 39.648 0.192 ;
     RECT  39.672 0.144 39.84 0.192 ;
     RECT  39.864 0.144 40.032 0.192 ;
     RECT  40.056 0.144 40.224 0.192 ;
     RECT  40.248 0.144 40.416 0.192 ;
     RECT  40.44 0.144 40.608 0.192 ;
     RECT  40.632 0.144 40.8 0.192 ;
     RECT  40.824 0.144 40.992 0.192 ;
     RECT  41.016 0.144 41.184 0.192 ;
     RECT  41.208 0.144 41.376 0.192 ;
     RECT  41.4 0.144 41.568 0.192 ;
     RECT  41.592 0.144 41.76 0.192 ;
     RECT  41.784 0.144 41.952 0.192 ;
     RECT  41.976 0.144 42.144 0.192 ;
     RECT  42.168 0.144 42.336 0.192 ;
     RECT  42.36 0.144 42.528 0.192 ;
     RECT  42.552 0.144 42.72 0.192 ;
     RECT  42.744 0.144 42.912 0.192 ;
     RECT  42.936 0.144 43.104 0.192 ;
     RECT  43.128 0.144 43.296 0.192 ;
     RECT  43.32 0.144 43.488 0.192 ;
     RECT  43.512 0.144 43.68 0.192 ;
     RECT  43.704 0.144 43.872 0.192 ;
     RECT  43.896 0.144 44.064 0.192 ;
     RECT  44.088 0.144 44.256 0.192 ;
     RECT  44.28 0.144 44.448 0.192 ;
     RECT  44.472 0.144 44.64 0.192 ;
     RECT  44.664 0.144 44.832 0.192 ;
     RECT  44.856 0.144 45.024 0.192 ;
     RECT  45.048 0.144 45.216 0.192 ;
     RECT  45.24 0.144 45.408 0.192 ;
     RECT  45.432 0.144 45.6 0.192 ;
     RECT  45.624 0.144 45.792 0.192 ;
     RECT  45.816 0.144 46.032 0.192 ;
     RECT  46.056 0.144 46.224 0.192 ;
     RECT  46.248 0.144 46.416 0.192 ;
     RECT  46.44 0.144 46.608 0.192 ;
     RECT  46.632 0.144 46.8 0.192 ;
     RECT  46.824 0.144 46.992 0.192 ;
     RECT  47.016 0.144 47.184 0.192 ;
     RECT  47.208 0.144 47.376 0.192 ;
     RECT  47.4 0.144 47.568 0.192 ;
     RECT  47.592 0.144 47.76 0.192 ;
     RECT  47.784 0.144 47.952 0.192 ;
     RECT  47.976 0.144 48.144 0.192 ;
     RECT  48.168 0.144 48.336 0.192 ;
     RECT  48.36 0.144 48.528 0.192 ;
     RECT  48.552 0.144 48.72 0.192 ;
     RECT  48.744 0.144 48.912 0.192 ;
     RECT  48.936 0.144 49.104 0.192 ;
     RECT  49.128 0.144 49.296 0.192 ;
     RECT  49.32 0.144 49.488 0.192 ;
     RECT  49.512 0.144 49.68 0.192 ;
     RECT  49.704 0.144 49.872 0.192 ;
     RECT  49.896 0.144 50.064 0.192 ;
     RECT  50.088 0.144 50.256 0.192 ;
     RECT  50.28 0.144 50.448 0.192 ;
     RECT  50.472 0.144 50.64 0.192 ;
     RECT  50.664 0.144 50.832 0.192 ;
     RECT  50.856 0.144 51.024 0.192 ;
     RECT  51.048 0.144 51.216 0.192 ;
     RECT  51.24 0.144 51.408 0.192 ;
     RECT  51.432 0.144 51.6 0.192 ;
     RECT  51.624 0.144 51.792 0.192 ;
     RECT  51.816 0.144 51.984 0.192 ;
     RECT  52.008 0.144 52.176 0.192 ;
     RECT  52.2 0.144 52.416 0.192 ;
     RECT  52.44 0.144 52.608 0.192 ;
     RECT  52.632 0.144 52.8 0.192 ;
     RECT  52.824 0.144 52.992 0.192 ;
     RECT  53.016 0.144 53.184 0.192 ;
     RECT  53.208 0.144 53.376 0.192 ;
     RECT  53.4 0.144 53.568 0.192 ;
     RECT  53.592 0.144 53.76 0.192 ;
     RECT  53.784 0.144 53.952 0.192 ;
     RECT  53.976 0.144 54.12 0.192 ;
     RECT  2.304 0.192 54.12 1.859 ;
     RECT  2.304 1.859 3.288 3.443 ;
     RECT  4.416 1.859 54.12 3.443 ;
     RECT  2.4 3.443 3.096 4.595 ;
     RECT  4.944 3.443 13.992 5.029 ;
     RECT  14.976 3.443 54.12 5.029 ;
     RECT  4.944 5.029 54.12 5.219 ;
     RECT  4.944 5.219 8.112 5.507 ;
     RECT  5.1 5.507 8.112 6.323 ;
     RECT  9.216 5.219 54.12 6.323 ;
     RECT  9.216 6.323 43.848 6.803 ;
     RECT  2.4 4.595 2.712 6.805 ;
     RECT  3.936 4.933 3.96 6.805 ;
     RECT  9.216 6.803 43.512 6.853 ;
     RECT  9.12 6.853 43.512 7.283 ;
     RECT  5.1 6.323 6.264 7.381 ;
     RECT  7.44 6.323 8.112 7.381 ;
     RECT  2.4 6.805 3.96 7.475 ;
     RECT  9.12 7.283 24.312 7.475 ;
     RECT  2.4 7.475 3.432 7.907 ;
     RECT  5.1 7.381 8.112 7.957 ;
     RECT  4.752 7.957 8.112 8.051 ;
     RECT  10.224 7.475 24.312 8.099 ;
     RECT  10.224 8.099 16.344 8.485 ;
     RECT  6.864 8.051 8.112 8.531 ;
     RECT  7.584 8.531 8.112 8.579 ;
     RECT  9.12 7.475 9.144 8.579 ;
     RECT  10.128 8.485 16.344 8.579 ;
     RECT  45.072 6.323 54.012 8.965 ;
     RECT  10.128 8.579 14.856 9.059 ;
     RECT  17.616 8.099 24.312 9.107 ;
     RECT  25.392 7.283 43.512 9.107 ;
     RECT  17.616 9.107 19.272 9.155 ;
     RECT  21.12 9.107 24.312 9.155 ;
     RECT  10.224 9.059 14.856 9.299 ;
     RECT  21.168 9.155 24.312 9.491 ;
     RECT  10.32 9.299 14.856 9.539 ;
     RECT  25.392 9.107 41.112 9.539 ;
     RECT  21.168 9.491 21.912 9.587 ;
     RECT  23.28 9.491 24.312 9.587 ;
     RECT  17.664 9.155 19.272 9.731 ;
     RECT  25.44 9.539 41.112 9.731 ;
     RECT  15.9 8.579 16.344 9.779 ;
     RECT  26.7 9.731 40.512 9.779 ;
     RECT  42.096 9.107 43.512 9.781 ;
     RECT  10.368 9.539 14.856 9.875 ;
     RECT  45.024 8.965 54.012 9.875 ;
     RECT  13.008 9.875 14.856 9.923 ;
     RECT  45.024 9.875 48.84 9.923 ;
     RECT  18.192 9.731 19.272 10.163 ;
     RECT  15.9 9.779 16.212 10.213 ;
     RECT  42.096 9.781 43.944 10.213 ;
     RECT  45.024 9.923 46.104 10.213 ;
     RECT  42.096 10.213 46.104 10.451 ;
     RECT  47.328 9.923 48.84 10.883 ;
     RECT  47.328 10.883 48.612 10.931 ;
     RECT  50.448 9.875 54.012 11.365 ;
     RECT  42.096 10.451 43.512 11.459 ;
     RECT  44.496 10.451 46.104 11.987 ;
     RECT  4.752 8.051 5.64 12.517 ;
     RECT  26.7 9.779 37.812 12.563 ;
     RECT  25.44 9.731 25.512 13.715 ;
     RECT  13.008 9.923 13.944 14.197 ;
     RECT  15.12 10.213 16.212 14.291 ;
     RECT  12.96 14.197 13.944 14.773 ;
     RECT  44.496 11.987 45.912 14.867 ;
     RECT  42.096 11.459 43.212 15.349 ;
     RECT  44.496 14.867 44.52 15.349 ;
     RECT  42.096 15.349 44.52 15.925 ;
     RECT  45.6 14.867 45.912 15.925 ;
     RECT  4.752 12.517 5.688 16.595 ;
     RECT  25.44 13.715 25.464 16.595 ;
     RECT  39.312 9.779 40.512 16.595 ;
     RECT  34.8 12.563 37.812 16.931 ;
     RECT  4.752 16.595 5.64 17.123 ;
     RECT  18.6 10.163 19.272 17.123 ;
     RECT  10.368 9.875 11.976 17.411 ;
     RECT  12.96 14.773 14.568 17.699 ;
     RECT  49.68 11.365 54.012 17.795 ;
     RECT  21.3 9.587 21.912 17.941 ;
     RECT  10.5 17.411 11.976 18.275 ;
     RECT  26.7 12.563 32.412 18.323 ;
     RECT  5.1 17.123 5.64 18.851 ;
     RECT  13.2 17.699 14.568 18.851 ;
     RECT  26.7 18.323 27.672 18.851 ;
     RECT  28.656 18.323 32.412 18.851 ;
     RECT  13.2 18.851 13.944 19.427 ;
     RECT  30.96 18.851 32.412 19.427 ;
     RECT  42.096 15.925 45.912 19.427 ;
     RECT  49.68 17.795 51.312 19.427 ;
     RECT  21.024 17.941 21.912 20.003 ;
     RECT  28.656 18.851 29.712 20.003 ;
     RECT  44.976 19.427 45.912 20.003 ;
     RECT  13.2 19.427 13.752 20.099 ;
     RECT  50.448 19.427 51.312 20.099 ;
     RECT  30.96 19.427 30.984 20.579 ;
     RECT  11.952 18.275 11.976 21.155 ;
     RECT  52.32 17.795 54.012 21.155 ;
     RECT  52.32 21.155 52.344 21.683 ;
     RECT  21.024 20.003 21.864 22.259 ;
     RECT  36.816 16.931 37.812 22.835 ;
     RECT  50.592 20.099 51.312 24.901 ;
     RECT  39.696 16.595 40.512 25.715 ;
     RECT  5.1 18.851 5.412 26.485 ;
     RECT  37.5 22.835 37.812 26.725 ;
     RECT  37.5 26.725 38.28 28.117 ;
     RECT  2.4 7.907 2.712 28.309 ;
     RECT  2.4 28.309 3.48 28.357 ;
     RECT  10.5 18.275 10.812 28.405 ;
     RECT  2.4 28.357 4.056 29.029 ;
     RECT  5.1 26.485 6.168 29.029 ;
     RECT  33.552 12.563 33.576 29.123 ;
     RECT  42.096 19.427 43.212 29.123 ;
     RECT  47.664 10.931 48.612 29.123 ;
     RECT  45.6 20.003 45.912 29.365 ;
     RECT  9.84 28.405 10.812 29.509 ;
     RECT  50.256 24.901 51.312 29.605 ;
     RECT  37.5 28.117 38.664 29.749 ;
     RECT  7.8 8.579 8.112 30.037 ;
     RECT  2.4 29.029 6.168 30.133 ;
     RECT  13.2 20.099 13.512 30.133 ;
     RECT  29.4 20.003 29.712 30.133 ;
     RECT  37.5 29.749 39.048 30.133 ;
     RECT  40.2 25.715 40.512 30.133 ;
     RECT  7.8 30.037 8.52 30.181 ;
     RECT  2.304 30.133 6.168 30.277 ;
     RECT  7.344 30.181 8.52 30.277 ;
     RECT  37.5 30.133 40.512 30.613 ;
     RECT  24 9.587 24.312 30.661 ;
     RECT  23.904 30.661 24.312 30.803 ;
     RECT  42.9 29.123 43.212 31.189 ;
     RECT  28.8 30.133 29.712 31.285 ;
     RECT  42.336 31.189 43.212 31.717 ;
     RECT  45.6 29.365 46.248 31.765 ;
     RECT  37.5 30.613 41.208 31.861 ;
     RECT  42.336 31.717 43.32 31.861 ;
     RECT  18.6 17.123 18.912 32.197 ;
     RECT  26.7 18.851 27.012 32.197 ;
     RECT  48.3 29.123 48.612 32.293 ;
     RECT  47.952 32.293 48.612 33.013 ;
     RECT  12.528 30.133 13.512 33.253 ;
     RECT  15.9 14.291 16.212 33.541 ;
     RECT  24 30.803 24.312 33.589 ;
     RECT  24 33.589 24.408 34.165 ;
     RECT  28.224 31.285 29.712 34.501 ;
     RECT  32.1 19.427 32.412 34.501 ;
     RECT  2.304 30.277 8.52 41.269 ;
     RECT  9.84 29.509 11.208 41.269 ;
     RECT  31.68 34.501 32.412 41.461 ;
     RECT  34.8 16.931 35.112 41.509 ;
     RECT  28.224 34.501 30.36 41.893 ;
     RECT  31.488 41.461 32.412 41.893 ;
     RECT  21.024 22.259 21.612 41.989 ;
     RECT  24 34.165 24.552 41.989 ;
     RECT  37.5 31.861 43.32 41.989 ;
     RECT  44.64 31.765 46.248 41.989 ;
     RECT  17.952 32.197 18.912 42.085 ;
     RECT  47.376 33.013 48.612 42.085 ;
     RECT  50.064 29.605 51.312 42.085 ;
     RECT  28.224 41.893 32.412 42.133 ;
     RECT  33.456 41.989 33.48 42.133 ;
     RECT  37.5 41.989 46.248 42.613 ;
     RECT  47.376 42.085 51.312 42.613 ;
     RECT  15.264 33.541 16.212 42.709 ;
     RECT  23.184 41.989 24.552 42.709 ;
     RECT  26.256 32.197 27.012 42.709 ;
     RECT  25.68 42.709 27.012 43.285 ;
     RECT  28.224 42.133 33.48 43.285 ;
     RECT  2.304 41.269 11.208 43.333 ;
     RECT  12.528 33.253 13.944 43.333 ;
     RECT  17.952 42.085 19.32 43.333 ;
     RECT  20.688 41.989 21.612 43.333 ;
     RECT  37.5 42.613 51.312 43.429 ;
     RECT  52.416 42.133 52.44 43.429 ;
     RECT  37.5 43.429 52.44 43.621 ;
     RECT  34.8 41.509 35.208 43.717 ;
     RECT  25.68 43.285 33.48 43.765 ;
     RECT  15.264 42.709 16.632 43.813 ;
     RECT  17.76 43.333 19.32 43.813 ;
     RECT  20.496 43.333 21.612 43.813 ;
     RECT  22.608 42.709 24.552 43.813 ;
     RECT  25.68 43.765 33.672 43.813 ;
     RECT  37.104 43.621 52.44 43.813 ;
     RECT  2.304 43.333 13.944 43.861 ;
     RECT  15.072 43.813 19.32 43.861 ;
     RECT  20.304 43.813 21.612 43.861 ;
     RECT  22.608 43.813 33.672 43.861 ;
     RECT  34.8 43.717 35.256 43.861 ;
     RECT  36.912 43.813 52.44 43.861 ;
     RECT  2.304 43.861 35.256 44.965 ;
     RECT  36.528 43.861 52.44 44.965 ;
     RECT  2.304 44.965 52.44 53.557 ;
     RECT  53.7 21.155 54.012 54.009 ;
     RECT  53.7 54.009 53.82 54.023 ;
     RECT  2.304 53.557 52.632 54.085 ;
     RECT  2.304 54.085 53.592 55.285 ;
     RECT  2.304 55.285 53.976 55.968 ;
     RECT  2.328 55.968 2.496 56.016 ;
     RECT  2.52 55.968 2.688 56.016 ;
     RECT  2.712 55.968 2.88 56.016 ;
     RECT  2.904 55.968 3.072 56.016 ;
     RECT  3.096 55.968 3.264 56.016 ;
     RECT  3.288 55.968 3.456 56.016 ;
     RECT  3.48 55.968 3.648 56.016 ;
     RECT  3.672 55.968 3.84 56.016 ;
     RECT  3.864 55.968 4.032 56.016 ;
     RECT  4.056 55.968 4.224 56.016 ;
     RECT  4.248 55.968 4.416 56.016 ;
     RECT  4.44 55.968 4.608 56.016 ;
     RECT  4.632 55.968 4.8 56.016 ;
     RECT  4.824 55.968 4.992 56.016 ;
     RECT  5.016 55.968 5.184 56.016 ;
     RECT  5.208 55.968 5.376 56.016 ;
     RECT  5.4 55.968 5.568 56.016 ;
     RECT  5.592 55.968 5.76 56.016 ;
     RECT  5.784 55.968 5.952 56.016 ;
     RECT  5.976 55.968 6.144 56.016 ;
     RECT  6.168 55.968 6.336 56.016 ;
     RECT  6.36 55.968 6.528 56.016 ;
     RECT  6.552 55.968 6.72 56.016 ;
     RECT  6.744 55.968 6.912 56.016 ;
     RECT  6.936 55.968 7.152 56.016 ;
     RECT  7.176 55.968 7.344 56.016 ;
     RECT  7.368 55.968 7.536 56.016 ;
     RECT  7.56 55.968 7.728 56.016 ;
     RECT  7.752 55.968 7.92 56.016 ;
     RECT  7.944 55.968 8.112 56.016 ;
     RECT  8.136 55.968 8.304 56.016 ;
     RECT  8.328 55.968 8.496 56.016 ;
     RECT  8.52 55.968 8.688 56.016 ;
     RECT  8.712 55.968 8.88 56.016 ;
     RECT  8.904 55.968 9.072 56.016 ;
     RECT  9.096 55.968 9.264 56.016 ;
     RECT  9.288 55.968 9.456 56.016 ;
     RECT  9.48 55.968 9.648 56.016 ;
     RECT  9.672 55.968 9.84 56.016 ;
     RECT  9.864 55.968 10.032 56.016 ;
     RECT  10.056 55.968 10.224 56.016 ;
     RECT  10.248 55.968 10.416 56.016 ;
     RECT  10.44 55.968 10.608 56.016 ;
     RECT  10.632 55.968 10.8 56.016 ;
     RECT  10.824 55.968 10.992 56.016 ;
     RECT  11.016 55.968 11.184 56.016 ;
     RECT  11.208 55.968 11.376 56.016 ;
     RECT  11.4 55.968 11.568 56.016 ;
     RECT  11.592 55.968 11.76 56.016 ;
     RECT  11.784 55.968 11.952 56.016 ;
     RECT  11.976 55.968 12.144 56.016 ;
     RECT  12.168 55.968 12.336 56.016 ;
     RECT  12.36 55.968 12.528 56.016 ;
     RECT  12.552 55.968 12.72 56.016 ;
     RECT  12.744 55.968 12.912 56.016 ;
     RECT  12.936 55.968 13.104 56.016 ;
     RECT  13.128 55.968 13.296 56.016 ;
     RECT  13.32 55.968 13.536 56.016 ;
     RECT  13.56 55.968 13.728 56.016 ;
     RECT  13.752 55.968 13.92 56.016 ;
     RECT  13.944 55.968 14.112 56.016 ;
     RECT  14.136 55.968 14.304 56.016 ;
     RECT  14.328 55.968 14.496 56.016 ;
     RECT  14.52 55.968 14.688 56.016 ;
     RECT  14.712 55.968 14.88 56.016 ;
     RECT  14.904 55.968 15.072 56.016 ;
     RECT  15.096 55.968 15.264 56.016 ;
     RECT  15.288 55.968 15.456 56.016 ;
     RECT  15.48 55.968 15.648 56.016 ;
     RECT  15.672 55.968 15.84 56.016 ;
     RECT  15.864 55.968 16.032 56.016 ;
     RECT  16.056 55.968 16.224 56.016 ;
     RECT  16.248 55.968 16.416 56.016 ;
     RECT  16.44 55.968 16.608 56.016 ;
     RECT  16.632 55.968 16.8 56.016 ;
     RECT  16.824 55.968 16.992 56.016 ;
     RECT  17.016 55.968 17.184 56.016 ;
     RECT  17.208 55.968 17.376 56.016 ;
     RECT  17.4 55.968 17.568 56.016 ;
     RECT  17.592 55.968 17.76 56.016 ;
     RECT  17.784 55.968 17.952 56.016 ;
     RECT  17.976 55.968 18.144 56.016 ;
     RECT  18.168 55.968 18.336 56.016 ;
     RECT  18.36 55.968 18.528 56.016 ;
     RECT  18.552 55.968 18.72 56.016 ;
     RECT  18.744 55.968 18.912 56.016 ;
     RECT  18.936 55.968 19.104 56.016 ;
     RECT  19.128 55.968 19.296 56.016 ;
     RECT  19.32 55.968 19.488 56.016 ;
     RECT  19.512 55.968 19.68 56.016 ;
     RECT  19.704 55.968 19.872 56.016 ;
     RECT  19.896 55.968 20.112 56.016 ;
     RECT  20.136 55.968 20.304 56.016 ;
     RECT  20.328 55.968 20.496 56.016 ;
     RECT  20.52 55.968 20.688 56.016 ;
     RECT  20.712 55.968 20.88 56.016 ;
     RECT  20.904 55.968 21.072 56.016 ;
     RECT  21.096 55.968 21.264 56.016 ;
     RECT  21.288 55.968 21.456 56.016 ;
     RECT  21.48 55.968 21.648 56.016 ;
     RECT  21.672 55.968 21.84 56.016 ;
     RECT  21.864 55.968 22.032 56.016 ;
     RECT  22.056 55.968 22.224 56.016 ;
     RECT  22.248 55.968 22.416 56.016 ;
     RECT  22.44 55.968 22.608 56.016 ;
     RECT  22.632 55.968 22.8 56.016 ;
     RECT  22.824 55.968 22.992 56.016 ;
     RECT  23.016 55.968 23.184 56.016 ;
     RECT  23.208 55.968 23.376 56.016 ;
     RECT  23.4 55.968 23.568 56.016 ;
     RECT  23.592 55.968 23.76 56.016 ;
     RECT  23.784 55.968 23.952 56.016 ;
     RECT  23.976 55.968 24.144 56.016 ;
     RECT  24.168 55.968 24.336 56.016 ;
     RECT  24.36 55.968 24.528 56.016 ;
     RECT  24.552 55.968 24.72 56.016 ;
     RECT  24.744 55.968 24.912 56.016 ;
     RECT  24.936 55.968 25.104 56.016 ;
     RECT  25.128 55.968 25.296 56.016 ;
     RECT  25.32 55.968 25.488 56.016 ;
     RECT  25.512 55.968 25.68 56.016 ;
     RECT  25.704 55.968 25.872 56.016 ;
     RECT  25.896 55.968 26.064 56.016 ;
     RECT  26.088 55.968 26.256 56.016 ;
     RECT  26.28 55.968 26.496 56.016 ;
     RECT  26.52 55.968 26.688 56.016 ;
     RECT  26.712 55.968 26.88 56.016 ;
     RECT  26.904 55.968 27.072 56.016 ;
     RECT  27.096 55.968 27.264 56.016 ;
     RECT  27.288 55.968 27.456 56.016 ;
     RECT  27.48 55.968 27.648 56.016 ;
     RECT  27.672 55.968 27.84 56.016 ;
     RECT  27.864 55.968 28.032 56.016 ;
     RECT  28.056 55.968 28.224 56.016 ;
     RECT  28.248 55.968 28.416 56.016 ;
     RECT  28.44 55.968 28.608 56.016 ;
     RECT  28.632 55.968 28.8 56.016 ;
     RECT  28.824 55.968 28.992 56.016 ;
     RECT  29.016 55.968 29.184 56.016 ;
     RECT  29.208 55.968 29.376 56.016 ;
     RECT  29.4 55.968 29.568 56.016 ;
     RECT  29.592 55.968 29.76 56.016 ;
     RECT  29.784 55.968 29.952 56.016 ;
     RECT  29.976 55.968 30.144 56.016 ;
     RECT  30.168 55.968 30.336 56.016 ;
     RECT  30.36 55.968 30.528 56.016 ;
     RECT  30.552 55.968 30.72 56.016 ;
     RECT  30.744 55.968 30.912 56.016 ;
     RECT  30.936 55.968 31.104 56.016 ;
     RECT  31.128 55.968 31.296 56.016 ;
     RECT  31.32 55.968 31.488 56.016 ;
     RECT  31.512 55.968 31.68 56.016 ;
     RECT  31.704 55.968 31.872 56.016 ;
     RECT  31.896 55.968 32.064 56.016 ;
     RECT  32.088 55.968 32.256 56.016 ;
     RECT  32.28 55.968 32.448 56.016 ;
     RECT  32.472 55.968 32.64 56.016 ;
     RECT  32.664 55.968 32.832 56.016 ;
     RECT  32.856 55.968 33.072 56.016 ;
     RECT  33.096 55.968 33.264 56.016 ;
     RECT  33.288 55.968 33.456 56.016 ;
     RECT  33.48 55.968 33.648 56.016 ;
     RECT  33.672 55.968 33.84 56.016 ;
     RECT  33.864 55.968 34.032 56.016 ;
     RECT  34.056 55.968 34.224 56.016 ;
     RECT  34.248 55.968 34.416 56.016 ;
     RECT  34.44 55.968 34.608 56.016 ;
     RECT  34.632 55.968 34.8 56.016 ;
     RECT  34.824 55.968 34.992 56.016 ;
     RECT  35.016 55.968 35.184 56.016 ;
     RECT  35.208 55.968 35.376 56.016 ;
     RECT  35.4 55.968 35.568 56.016 ;
     RECT  35.592 55.968 35.76 56.016 ;
     RECT  35.784 55.968 35.952 56.016 ;
     RECT  35.976 55.968 36.144 56.016 ;
     RECT  36.168 55.968 36.336 56.016 ;
     RECT  36.36 55.968 36.528 56.016 ;
     RECT  36.552 55.968 36.72 56.016 ;
     RECT  36.744 55.968 36.912 56.016 ;
     RECT  36.936 55.968 37.104 56.016 ;
     RECT  37.128 55.968 37.296 56.016 ;
     RECT  37.32 55.968 37.488 56.016 ;
     RECT  37.512 55.968 37.68 56.016 ;
     RECT  37.704 55.968 37.872 56.016 ;
     RECT  37.896 55.968 38.064 56.016 ;
     RECT  38.088 55.968 38.256 56.016 ;
     RECT  38.28 55.968 38.448 56.016 ;
     RECT  38.472 55.968 38.64 56.016 ;
     RECT  38.664 55.968 38.832 56.016 ;
     RECT  38.856 55.968 39.024 56.016 ;
     RECT  39.048 55.968 39.216 56.016 ;
     RECT  39.24 55.968 39.456 56.016 ;
     RECT  39.48 55.968 39.648 56.016 ;
     RECT  39.672 55.968 39.84 56.016 ;
     RECT  39.864 55.968 40.032 56.016 ;
     RECT  40.056 55.968 40.224 56.016 ;
     RECT  40.248 55.968 40.416 56.016 ;
     RECT  40.44 55.968 40.608 56.016 ;
     RECT  40.632 55.968 40.8 56.016 ;
     RECT  40.824 55.968 40.992 56.016 ;
     RECT  41.016 55.968 41.184 56.016 ;
     RECT  41.208 55.968 41.376 56.016 ;
     RECT  41.4 55.968 41.568 56.016 ;
     RECT  41.592 55.968 41.76 56.016 ;
     RECT  41.784 55.968 41.952 56.016 ;
     RECT  41.976 55.968 42.144 56.016 ;
     RECT  42.168 55.968 42.336 56.016 ;
     RECT  42.36 55.968 42.528 56.016 ;
     RECT  42.552 55.968 42.72 56.016 ;
     RECT  42.744 55.968 42.912 56.016 ;
     RECT  42.936 55.968 43.104 56.016 ;
     RECT  43.128 55.968 43.296 56.016 ;
     RECT  43.32 55.968 43.488 56.016 ;
     RECT  43.512 55.968 43.68 56.016 ;
     RECT  43.704 55.968 43.872 56.016 ;
     RECT  43.896 55.968 44.064 56.016 ;
     RECT  44.088 55.968 44.256 56.016 ;
     RECT  44.28 55.968 44.448 56.016 ;
     RECT  44.472 55.968 44.64 56.016 ;
     RECT  44.664 55.968 44.832 56.016 ;
     RECT  44.856 55.968 45.024 56.016 ;
     RECT  45.048 55.968 45.216 56.016 ;
     RECT  45.24 55.968 45.408 56.016 ;
     RECT  45.432 55.968 45.6 56.016 ;
     RECT  45.624 55.968 45.792 56.016 ;
     RECT  45.816 55.968 46.032 56.016 ;
     RECT  46.056 55.968 46.224 56.016 ;
     RECT  46.248 55.968 46.416 56.016 ;
     RECT  46.44 55.968 46.608 56.016 ;
     RECT  46.632 55.968 46.8 56.016 ;
     RECT  46.824 55.968 46.992 56.016 ;
     RECT  47.016 55.968 47.184 56.016 ;
     RECT  47.208 55.968 47.376 56.016 ;
     RECT  47.4 55.968 47.568 56.016 ;
     RECT  47.592 55.968 47.76 56.016 ;
     RECT  47.784 55.968 47.952 56.016 ;
     RECT  47.976 55.968 48.144 56.016 ;
     RECT  48.168 55.968 48.336 56.016 ;
     RECT  48.36 55.968 48.528 56.016 ;
     RECT  48.552 55.968 48.72 56.016 ;
     RECT  48.744 55.968 48.912 56.016 ;
     RECT  48.936 55.968 49.104 56.016 ;
     RECT  49.128 55.968 49.296 56.016 ;
     RECT  49.32 55.968 49.488 56.016 ;
     RECT  49.512 55.968 49.68 56.016 ;
     RECT  49.704 55.968 49.872 56.016 ;
     RECT  49.896 55.968 50.064 56.016 ;
     RECT  50.088 55.968 50.256 56.016 ;
     RECT  50.28 55.968 50.448 56.016 ;
     RECT  50.472 55.968 50.64 56.016 ;
     RECT  50.664 55.968 50.832 56.016 ;
     RECT  50.856 55.968 51.024 56.016 ;
     RECT  51.048 55.968 51.216 56.016 ;
     RECT  51.24 55.968 51.408 56.016 ;
     RECT  51.432 55.968 51.6 56.016 ;
     RECT  51.624 55.968 51.792 56.016 ;
     RECT  51.816 55.968 51.984 56.016 ;
     RECT  52.008 55.968 52.176 56.016 ;
     RECT  52.2 55.968 52.416 56.016 ;
     RECT  52.44 55.968 52.608 56.016 ;
     RECT  52.632 55.968 52.8 56.016 ;
     RECT  52.824 55.968 52.992 56.016 ;
     RECT  53.016 55.968 53.184 56.016 ;
     RECT  53.208 55.968 53.376 56.016 ;
     RECT  53.4 55.968 53.568 56.016 ;
     RECT  53.592 55.968 53.76 56.016 ;
     RECT  53.784 55.968 53.952 56.016 ;
     RECT  38.184 0.133 38.208 0.144 ;
     RECT  38.328 0.133 38.4 0.144 ;
     RECT  38.52 0.133 38.592 0.144 ;
     RECT  38.712 0.133 38.784 0.144 ;
     RECT  38.904 0.133 38.976 0.144 ;
     RECT  39.096 0.133 39.168 0.144 ;
     RECT  39.288 0.133 39.36 0.144 ;
     RECT  47.688 0.133 47.712 0.144 ;
     RECT  47.832 0.133 47.904 0.144 ;
     RECT  48.024 0.133 48.096 0.144 ;
     RECT  48.216 0.133 48.288 0.144 ;
     RECT  48.408 0.133 48.48 0.144 ;
     RECT  48.6 0.133 48.672 0.144 ;
     RECT  48.792 0.133 48.864 0.144 ;
     RECT  48.984 0.133 49.056 0.144 ;
     RECT  49.176 0.133 49.2 0.144 ;
     RECT  3.288 1.859 4.416 3.443 ;
     RECT  3.096 3.443 4.944 4.595 ;
     RECT  13.992 3.443 14.976 5.029 ;
     RECT  2.712 4.595 4.944 4.933 ;
     RECT  2.712 4.933 3.936 6.805 ;
     RECT  3.96 4.933 4.944 5.507 ;
     RECT  8.112 5.219 9.216 6.853 ;
     RECT  3.96 5.507 5.1 7.475 ;
     RECT  6.264 6.323 7.44 7.381 ;
     RECT  43.848 6.323 45.072 6.803 ;
     RECT  8.112 6.853 9.12 8.579 ;
     RECT  24.312 7.283 25.392 9.539 ;
     RECT  3.432 7.475 5.1 7.907 ;
     RECT  9.144 7.475 10.224 8.485 ;
     RECT  4.752 7.907 5.1 7.957 ;
     RECT  5.64 8.051 6.864 8.531 ;
     RECT  16.344 8.099 17.616 9.155 ;
     RECT  9.144 8.485 10.128 8.579 ;
     RECT  14.856 8.579 15.9 9.923 ;
     RECT  43.512 8.965 45.024 9.781 ;
     RECT  41.112 9.107 42.096 9.731 ;
     RECT  16.344 9.155 17.664 9.731 ;
     RECT  21.912 9.491 23.28 9.587 ;
     RECT  24.312 9.539 25.44 16.595 ;
     RECT  25.512 9.731 26.7 13.715 ;
     RECT  37.812 9.779 39.312 16.595 ;
     RECT  43.944 9.781 45.024 10.213 ;
     RECT  11.976 9.875 13.008 14.197 ;
     RECT  48.84 9.875 50.448 10.883 ;
     RECT  13.944 9.923 15.9 10.213 ;
     RECT  46.104 9.923 47.328 10.931 ;
     RECT  13.944 10.213 15.12 14.291 ;
     RECT  43.512 10.451 44.496 11.459 ;
     RECT  48.612 10.883 50.448 11.365 ;
     RECT  48.612 11.365 49.68 19.427 ;
     RECT  43.212 11.459 44.496 15.349 ;
     RECT  32.412 12.563 33.552 29.123 ;
     RECT  33.576 12.563 34.8 29.123 ;
     RECT  25.464 13.715 26.7 16.595 ;
     RECT  11.976 14.197 12.96 17.699 ;
     RECT  13.944 14.291 15.9 14.773 ;
     RECT  14.568 14.773 15.9 18.851 ;
     RECT  44.52 14.867 45.6 15.925 ;
     RECT  11.976 17.699 13.2 21.155 ;
     RECT  51.312 17.795 52.32 21.683 ;
     RECT  10.812 18.275 11.952 21.155 ;
     RECT  27.672 18.323 28.656 18.851 ;
     RECT  29.712 18.851 30.96 20.579 ;
     RECT  30.984 19.427 32.1 20.579 ;
     RECT  52.344 21.155 53.7 21.683 ;
     RECT  4.056 28.357 5.1 29.029 ;
     RECT  48.612 29.605 50.064 42.085 ;
     RECT  39.048 29.749 40.2 30.133 ;
     RECT  8.52 30.037 9.84 41.269 ;
     RECT  11.208 30.133 12.528 43.333 ;
     RECT  6.168 30.181 7.344 30.277 ;
     RECT  41.208 31.189 42.336 31.861 ;
     RECT  27.012 31.285 28.224 43.285 ;
     RECT  43.32 31.765 44.64 41.989 ;
     RECT  46.248 33.013 47.376 42.613 ;
     RECT  13.944 33.541 15.264 43.813 ;
     RECT  30.36 34.501 31.68 41.461 ;
     RECT  30.36 41.461 31.488 41.893 ;
     RECT  32.412 41.989 33.456 42.133 ;
     RECT  33.48 41.989 34.8 43.765 ;
     RECT  19.32 42.085 20.688 43.333 ;
     RECT  51.312 42.133 52.416 43.429 ;
     RECT  52.44 42.133 53.7 53.557 ;
     RECT  16.632 42.709 17.952 43.333 ;
     RECT  21.612 42.709 22.608 43.861 ;
     RECT  24.552 42.709 25.68 43.813 ;
     RECT  16.632 43.333 17.76 43.813 ;
     RECT  19.32 43.333 20.496 43.813 ;
     RECT  33.672 43.765 34.8 43.861 ;
     RECT  13.944 43.813 15.072 43.861 ;
     RECT  19.32 43.813 20.304 43.861 ;
     RECT  35.256 43.861 36.528 44.965 ;
     RECT  52.632 53.557 53.7 54.023 ;
     RECT  53.82 54.009 53.976 54.023 ;
     RECT  52.632 54.023 53.976 54.085 ;
     RECT  53.592 54.085 53.976 55.285 ;
  END
END dsfd_rly_536_SN
END LIBRARY
